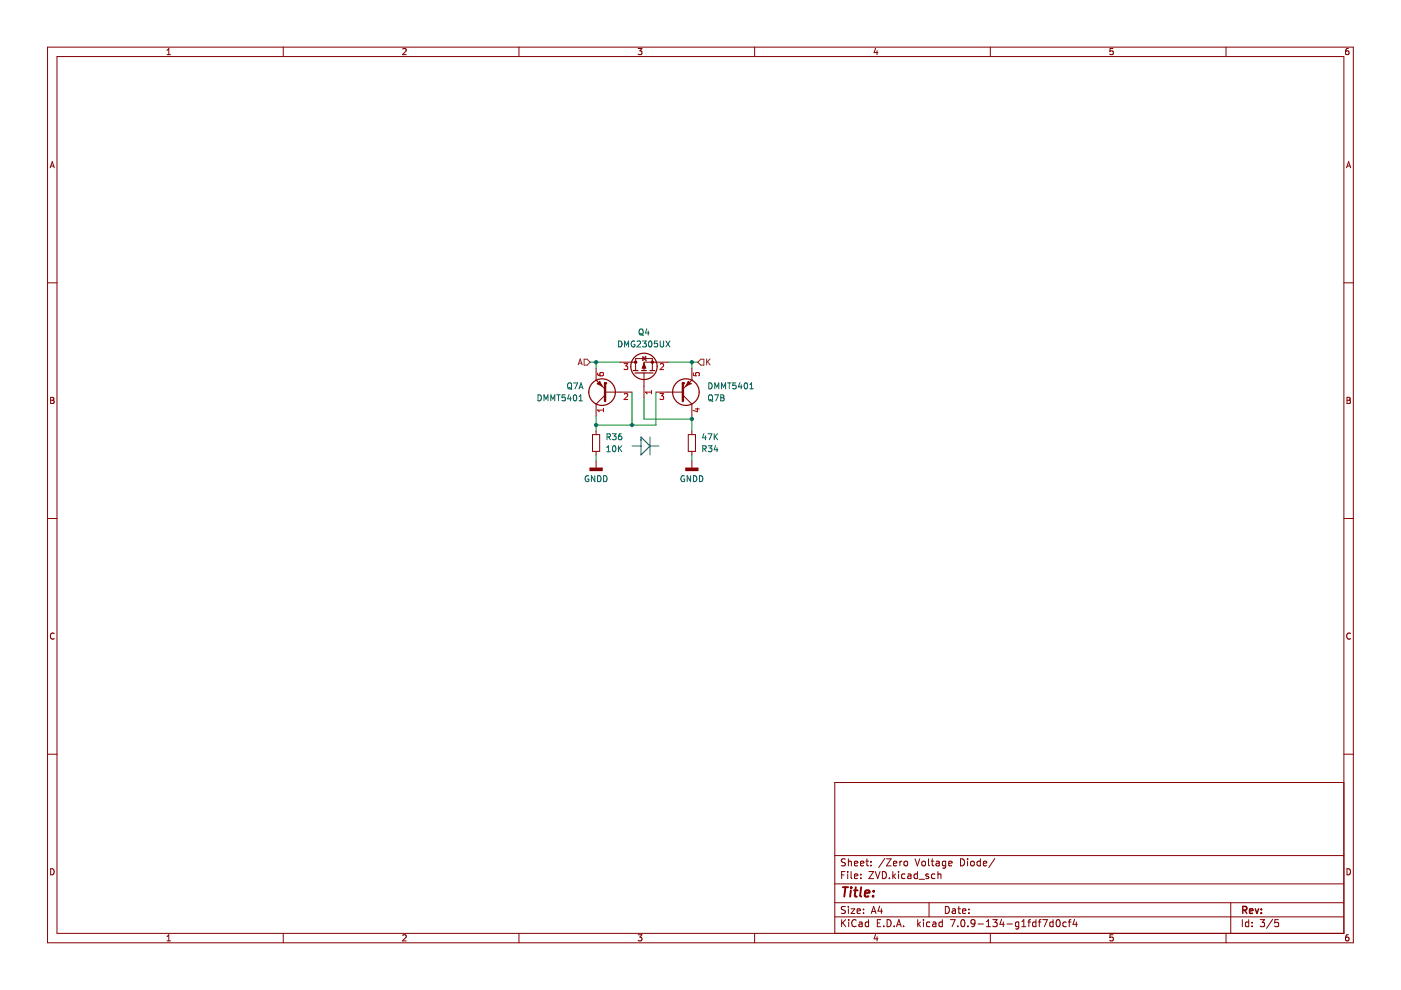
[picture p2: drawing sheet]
<svg xmlns="http://www.w3.org/2000/svg" width="297mm" height="210mm" viewBox="0 0 297 210" stroke-linecap="round" stroke-linejoin="round" font-family="sans-serif">
<g fill="none" stroke="#840000" stroke-width=".21">
<path d="M10.1 10h276.8v189.9h-276.8zM12.1 12h272.8v185.9h-272.8zM35.4 11.6h.8M35.4 10.7l.4-.4v1.3M60.1 10v2M85.4 10.4l.5-.1 .2 .4-.8 .9h.8M110 10v2M135.3 10.3h.8l-.4 .5 .3 .1v.6l-.1 .1-.6-.1M160 10v2M185.6 10.2l-.3 1h.8M185.9 10.7v.9M210 10v2"/>
<path d="M236 10.3h-.6l-.1 .6 .6-.1 .1 .7-.2 .1-.5-.1M259.9 10v2M285.9 10.3h-.4l-.2 .3v.7l.2 .3 .5-.1-.1-.7h-.4l-.2 .2M10.6 35.6l.5-1.3 .4 1.3M10.8 35.2h.6M285.5 35.6l.4-1.3 .5 1.3M285.6 35.2h.6M10.1 60h2M284.9 60h2M134 76.8h.8M134.8 78.6v-2.6h3.5v2.6M136.5 79.1v2.8"/>
<path d="M139.1 76.8h-2.6v1.8M10.7 84.2h.5l.2 .3-.2 .4 .2 .1 .1 .3-.3 .2h-.5zM10.7 84.9h.5M285.6 84.2h.4l.3 .3-.3 .4 .3 .1v.3l-.2 .2h-.5zM285.6 84.9h.4M10.1 109.9h2M284.9 109.9h2M11.5 134.3a.58 .58 0 0 0-.8 .6 .58 .58 0 0 0 .8 .5M286.3 134.3a.58 .58 0 0 0-.8 .6 .58 .58 0 0 0 .8 .5M10.1 159.9h2M284.9 159.9h2M284.9 165.9h-107.9v32"/>
<path d="M10.7 184.2a.66 .66 0 0 1 .8 .6 .66 .66 0 0 1-.8 .7zM35.4 198.6l.4-.4v1.3M35.4 199.5h.8M60.1 197.9v2M85.4 198.3l.5-.1 .2 .4-.8 .9h.8M110 197.9v2M135.3 198.2h.8l-.4 .5 .3 .1v.6l-.1 .1-.6-.1M160 197.9v2M177 194.4h107.9M177 191.4h107.9M177 187.4h107.9M177 181.4h107.9"/>
<path d="M178.4 195v1.5M178.4 185.5h.5M178.7 195.6l.6 .9M179.2 184.8h-.8v1.5M179.2 192.3l-.5-.1-.3 .1v.5l.7 .2 .1 .4-.3 .3-.5-.1M179.2 182.2l-.5-.1-.3 .1v.5l.7 .2 .1 .4-.3 .3-.5-.1M179.3 195l-.9 .8M179.7 184.8v.1M179.7 185.3v1M179.9 182.1v1.5M179.9 192.2v.1M179.9 192.7v1"/>
<path d="M179.9 182.7l.2-.1 .3 .1 .1 .9M179.9 195v.1M179.9 195.5v1M180.4 192.7h.8l-.8 1h.8M180.4 184.8v1.3l.3 .2M181.2 185.8l.7-.2-.1-.2-.4-.1-.2 .2v.7h.6M181.2 183.1l.7-.2-.1-.2-.4-.1-.2 .2v.7h.6M181.5 195.1a.71 .71 0 0 0-1 .5 .71 .71 0 0 0 .7 .9l.3-.2M181.7 193.2l.7-.2v-.2l-.5-.1-.2 .2 .1 .7h.6M182.2 195.6h.5l.1 .9M182.4 183.1l.8-.2-.1-.2-.4-.1-.3 .2 .1 .7h.6M182.5 186.1v.2"/>
<path d="M182.5 185.4v.1M182.8 195.8l-.5 .1-.2 .2 .2 .4 .5-.1M183.1 193.5v.2M183.1 192.8v.1M183.6 182.6h.6M183.8 182.1v1.3l.4 .2M184.2 195.6l-.5-.1-.3 .3 .2 .6h.6M184.2 195v1.5M184.2 184.8h1l-1 1.5h1M184.7 183.4v.2M184.7 182.7v.1M184.7 193.7l.5-1.5 .5 1.5"/>
<path d="M184.9 193.3h.7M185.6 184.8l.5 1.5 .5-1.5M185.6 198.1l-.3 1h.8M185.9 198.6v.9M186 195.7h.5M186.5 192.1l-.3 1.1h.9M186.7 195h-.7v1.5h.7M186.9 192.7v1M187.1 184.8a.76 .76 0 0 1 .8 .7 .76 .76 0 0 1-.8 .8zM187.4 196.3v.2M187.6 182l-1.3 1.9M187.9 182.1h1l-1 1.5h1"/>
<path d="M188.1 195a.76 .76 0 0 1 .8 .7 .76 .76 0 0 1-.8 .8zM188.6 186.1v.2M189.3 184.8v1.5M189.4 183.1l.8-.2-.1-.2-.4-.1-.3 .2 .1 .7h.6M189.4 185.7l.5 .6M189.6 196.3v.2M189.9 185.3l-.6 .6M190.1 196.5l.5-1.5 .5 1.5M190.2 196.1h.7M190.5 184.8v.1M190.5 185.3v1M190.8 182.6v1"/>
<path d="M191.2 182.6l-.4 .3M191.6 196.3v.2M191.7 182.7l.2-.1 .5 .1v.6l-.1 .2-.4 .1-.2-.2zM191.9 185.4l-.5-.1-.2 .3 .1 .6h.6M192.5 185.4h.6l.1 .9M193.2 185.6l-.5 .1-.3 .2 .3 .4 .5-.1M194 182.1l.5 1.5 .5-1.5M194.5 185.4l-.4-.1-.3 .3 .1 .6h.6M194.5 184.8v1.5M194.6 195v1.5M194.7 195.9l.5 .6M194.9 186.4h1.1"/>
<path d="M195.2 195.5l-.6 .6M195.5 182.7l.2-.1 .4 .1 .1 .6-.1 .2-.4 .1-.2-.2zM195.8 195v.1M195.8 195.5v1M196.9 182.1v1.3l.2 .2M196.9 185.4l-.4-.1-.2 .2 .1 .2 .5 .2v.3h-.6M197 191.4v3M197.1 195.6l-.4-.1-.3 .3 .2 .6h.5M197.4 182.6h.6M197.6 182.1v1.3l.4 .2M197.8 195.6h.6v.9M198.2 185.4l-.4-.1-.3 .3 .1 .6h.6"/>
<path d="M198.4 195.8l-.5 .1-.2 .2 .2 .4 .5-.1M198.5 182.7h.6v.9M198.9 185.4l.2-.1 .3 .1 .1 .9M198.9 184.8v1.5M199.1 182.9l-.5 .1-.2 .2 .2 .4 .5-.1M199.8 195.6l-.4-.1-.3 .3 .1 .6h.6M199.8 195v1.5M200.4 192.2a.76 .76 0 0 1 .9 .7 .76 .76 0 0 1-.9 .8zM200.5 182.7l-.4-.1-.3 .3 .1 .6h.6M200.5 182.6v1.2l-.3 .3-.3-.1M201.1 183.1l.8-.2-.1-.2-.4-.1-.3 .2 .1 .7h.6M201.5 195h1l-.6 1.5"/>
<path d="M201.9 192.8h.6l.1 .9M202.6 193l-.5 .1-.2 .2 .2 .4 .5-.1M203.1 192.7h.5M203.1 196.3v.2M203.3 192.2v1.3l.3 .2M203.6 182.1a.76 .76 0 0 1 .9 .7 .76 .76 0 0 1-.9 .8zM203.9 195.1l.2-.1a.8 .8 0 0 1 .5 .7 .8 .8 0 0 1-.5 .8l-.4-.6zM204.1 193.2l.7-.2-.1-.2-.4-.1-.2 .2v.7h.6M205.1 182.1v.1M205.1 182.6v1M205.2 196.3v.2M205.4 193.5v.2"/>
<path d="M205.4 192.8v.1M205.9 182.7l.2-.1 .4 .1 .1 .6-.2 .2-.3 .1-.2-.2zM206.7 195.6l-.3 .3h-.3l-.2-.3v-.3l.2-.3 .5 .1 .1 .2a1 1 0 0 1-.4 1.2h-.3M207.4 195.9h1.1M207.9 182.7l-.5-.1-.3 .3 .2 .6h.6M207.9 182.1v1.5M208.5 183.1l.7-.2-.1-.2-.4-.1-.2 .2 .1 .7h.5M209.1 196.5h.9M209.1 195.4l.5-.4v1.5M210 197.9v2M210.5 195h.9l-.5 .6 .5 .1v.6l-.3 .2-.6-.2M210.9 182l-1.3 1.9"/>
<path d="M212.4 194.9l-.4 1.1h.9M212.7 195.5v1M213.5 195.9h1.1M216 195.6l-.4-.1-.3 .3 .1 .6h.6M216 195.5v1.2l-.3 .3-.3-.1M216.6 196.5h.9M216.6 195.4l.5-.4v1.5M217.9 195.5h.6M218.5 195l-.4 .2v1.3M219.6 195.6l-.4-.1-.3 .3 .2 .6h.5M219.6 195v1.5M220.1 195.5h.6"/>
<path d="M220.7 195l-.3 .2v1.3M221.1 195h1l-.7 1.5M223.3 195.6l-.5-.1-.2 .3 .1 .6h.6M223.3 195v1.5M224.1 195.1l.2-.1a.8 .8 0 0 1 .5 .7 .8 .8 0 0 1-.5 .8l-.4-.6zM226.1 195.6l-.5-.1-.3 .3 .2 .6h.6M226.5 195.5h.6M227.1 195l-.4 .2v1.3M227.8 194.9l-.3 1.1h.9M228.2 195.5v1M236 198.2h-.6l-.1 .6 .6-.1 .1 .7-.2 .1-.5-.1M259.9 197.9v2"/>
<path d="M260.9 191.4v6.5M263.4 195v1.5M264.8 195.6l-.5-.1-.3 .3 .2 .6h.6M264.8 195v1.5M265.5 196.3v.2M265.5 195.6v.1M267.2 195h.9l-.5 .6 .4 .1v.6l-.2 .2-.6-.2M269.8 194.9l-1.3 1.9M271 195h-.7v.7l.2-.1h.5l.1 .2-.1 .5-.2 .2-.5-.2M285.6 184.2a.66 .66 0 0 1 .7 .6 .66 .66 0 0 1-.7 .7zM285.9 198.2l-.4 .1-.2 .2v.7l.2 .3 .5-.1-.1-.7h-.4l-.2 .2"/>
</g>
<path d="M263.5 193l.7-.1 .2-.2-.1-.4-.8-.1v1.5M263.9 193l.5 .7M264.9 193.2l.7-.2v-.3h-.5l-.2 .2 .1 .7h.6M266.1 192.7l.4 1 .4-1M267.4 193.5v.2M267.4 192.7v.2" fill="none" stroke="#840000" stroke-width=".3"/>
<path d="M178.7 188.1h1.1M179.3 188.1l-.3 2M180.4 188.8l-.2 1.3M180.5 188.1v.2M181.1 188.8h.7M181.4 188.1l-.2 1.7 .1 .2 .4 .1M182.6 188.1l-.2 1.7 .2 .3M183.4 189.4l.9-.2v-.3h-.8l-.2 .9 .3 .3 .6-.1M185.1 189.9v.2M185.2 188.9v.2" fill="none" stroke="#840000" stroke-width=".4"/>
<path d="M134 94.6h1.9M135.9 92.7l1.9 1.9-1.9 1.9zM137.8 94.6h1.9M137.8 92.7v3.8" fill="none" stroke="#0000c2" stroke-width=".21"/>
<path d="M125.1 76.8h6.4M126.4 76.8v1.3M141.6 76.8h6.4M146.7 76.8v1.3M126.4 88.2v3.2M126.4 96.5v1.2M134 83.1v7M136.5 84.4v4.4h10.2M139.1 83.1v7h-12.7M146.7 88.2v3.2M146.7 96.5v1.2" fill="none" stroke="#009600" stroke-width=".21"/>
<path d="M122.6 77.4l.4-1.3 .4 1.3M122.7 77h.6M123.8 76.2h.7l.6 .6-.6 .6h-.7zM148.6 76.2h.6v1.2h-.6l-.6-.6zM149.8 76.1v1.3M150 76.6l.5 .8M150.5 76.1l-.7 .7" fill="none" stroke="#725600" stroke-width=".21"/>
<path d="M134.3 78.6h1M134.6 79.1h3.8M136 78.6h1M137.8 78.6h1" fill="none" stroke="#840000" stroke-width=".25"/>
<path d="M136.5 77l.4 1.1h-.7z" fill="#840000"/>
<path d="M136.3 75.6l.6 .4-.6 .4zM136.5 77l.4 1.1h-.7zM136.8 75.5l.2 1" fill="none" stroke="#840000" stroke-width=".21"/>
<circle cx="136.5" cy="77.7" r="2.79" fill="none" stroke="#840000" stroke-width=".25"/>
<circle cx="138.3" cy="76.8" r=".25" fill="#840000"/>
<circle cx="138.3" cy="76.8" r=".25" fill="none" stroke="#840000" stroke-width=".21"/>
<circle cx="134.8" cy="76.8" r=".25" fill="#840000"/>
<g fill="none" stroke="#840000" stroke-width=".21">
<path d="M131.5 76.8h2.5M139.1 76.8h2.5M136.5 81.9v2.5M141.6 83.1h3.2M144.8 83.8l1.9 1.9M146.7 80.6h.1M146.7 80.6l-1.9 1.9"/>
<circle cx="134.8" cy="76.8" r=".25"/>
</g>
<path d="M132.3 77.1h.8l-.4 .5 .3 .1v.5l-.2 .2-.5-.2M140 77.2l.5-.1 .2 .4-.8 .9h.8M138.1 82.8v.7M138.1 83.1h-1.3l.4 .4" fill="none" stroke="#a90000" stroke-width=".21"/>
<g fill="none" stroke="#006464" stroke-width=".21">
<path d="M131.2 72.3a.64 .64 0 0 1 .7 .6 .64 .64 0 0 1-.7 .7zM132.4 73.6v-1.3l.4 .9 .5-.9v1.3M134.5 72.4a.58 .58 0 0 0-.7 .5 .58 .58 0 0 0 .8 .5v-.4h-.2M135.1 72.4l.5-.1 .2 .4-.8 .9h.8M135.6 69.9l.2-.1a.43 .43 0 0 1 .6 .4v.4a.42 .42 0 0 1-.5 .4 .42 .42 0 0 1-.4-.4zM135.8 70.7l.6 .4M136.2 72.3h.8l-.4 .5 .4 .1v.5l-.2 .2-.6-.2M137.1 69.7l-.3 .9h.8M137.4 70.2v.8M137.6 72.4l.2-.1a.68 .68 0 0 1 .4 .6 .68 .68 0 0 1-.4 .7l-.3-.5zM139.4 72.3h-.6l-.1 .6 .6-.1 .1 .6-.2 .2-.5-.2M140 72.3v1l.2 .3 .4-.1 .1-.2v-1"/>
<path d="M141.2 72.3l.8 1.3M142 72.3l-.8 1.3"/>
</g>
<path d="M144.8 81.2v3.8" fill="none" stroke="#840000" stroke-width=".51"/>
<circle cx="144.8" cy="81.2" r=".25" fill="#840000"/>
<path d="M145.9 80.9l.5 .5-1 .5z" fill-rule="evenodd" fill="#840000"/>
<path d="M146.7 78.1v2.5M125.6 92.1h1.5v3.6h-1.5zM126.4 91.4v.7M126.4 95.7v.8M139.1 83.1h2.5M145.9 80.9l.5 .5-1 .5zM146.4 81.4h.1M146.7 85.7v2.5" fill="none" stroke="#840000" stroke-width=".21"/>
<circle cx="145.4" cy="83.1" r="2.82" fill="none" stroke="#840000" stroke-width=".25"/>
<path d="M147 79v.6l.6 .1-.1-.6 .6-.1 .2 .2-.2 .5M139.9 83.4h.8l-.4 .5 .3 .1v.6l-.1 .1-.6-.1M147.4 86.7h.9M147.8 86.5v.8l-.9-.3" fill="none" stroke="#a90000" stroke-width=".21"/>
<g fill="none" stroke="#006464" stroke-width=".21">
<path d="M128.6 95.8h.8M128.6 94.9l.4-.4v1.3M128.7 92.6h.6l.1-.5-.7-.1v1.2M129 92.6l.4 .6M129.8 92h.8l-.4 .5 .4 .1v.5l-.2 .1-.6-.1M130 94.6l.1-.1a.68 .68 0 0 1 .5 .6 .68 .68 0 0 1-.5 .7l-.3-.5zM131.1 94.5v1.3M131.3 95.1l.5 .7M131.7 92h-.3l-.2 .3-.1 .7 .3 .2 .4-.1-.1-.6h-.3l-.3 .2M131.8 94.5l-.7 .7M150.3 83.9l.2-.2a.43 .43 0 0 1 .6 .4v.5a.42 .42 0 0 1-.5 .4 .42 .42 0 0 1-.4-.4zM150.3 81.2a.64 .64 0 0 1 .7 .6 .64 .64 0 0 1-.7 .6z"/>
<path d="M150.5 84.7l.6 .4M151.5 83.7h.8l-.5 1.3M151.5 82.4v-1.2l.5 .9 .4-.9v1.2M152.8 83.7h.4l.3 .3-.3 .3 .3 .1v.3l-.2 .3h-.5zM152.8 84.3h.4M153 82.4v-1.2l.4 .9 .4-.9v1.2M154.3 81.2h.7M154.6 81.2v1.2M156 81.2h-.6v.6l.6-.1v.6l-.2 .1-.4-.1M156.9 81.1l-.3 .9h.7M157.2 81.6v.8M158 81.2h.1a.68 .68 0 0 1 .4 .6 .68 .68 0 0 1-.4 .6 .84 .84 0 0 1-.1-1.2z"/>
<path d="M159 82.4h.7M159 81.5l.3-.3v1.2"/>
</g>
<path d="M125.1 99.3h2.6v.5h-2.6z" fill-rule="evenodd" fill="#840000"/>
<path d="M125.1 99.3h2.6v.5h-2.6z" fill="none" stroke="#840000" stroke-width=".25"/>
<path d="M126.4 80.6h.1M126.4 97.7v1.6M126.4 80.6l1.9 1.9M128.3 83.1h3.2M128.3 83.8l-1.9 1.9" fill="none" stroke="#840000" stroke-width=".21"/>
<path d="M124.8 100.9a.58 .58 0 0 0-.8 .6 .58 .58 0 0 0 .8 .5v-.4h-.2M126.1 100.9v1.2l-.7-1.2v1.2M126.7 100.9a.64 .64 0 0 1 .7 .6 .64 .64 0 0 1-.7 .6zM128 100.9a.64 .64 0 0 1 .7 .6 .64 .64 0 0 1-.7 .6z" fill="none" stroke="#006464" stroke-width=".21"/>
<path d="M128.3 81.2v3.8" fill="none" stroke="#840000" stroke-width=".51"/>
<circle cx="128.3" cy="81.2" r=".25" fill="#840000"/>
<path d="M127.1 80.9l.6 1-1.1-.5z" fill-rule="evenodd" fill="#840000"/>
<path d="M126.4 78.1v2.5M126.4 85.7v2.5M126.6 81.4h.1M127.1 80.9l.6 1-1.1-.5zM131.5 83.1h2.5M145.9 92.1h1.6v3.6h-1.6zM146.7 91.4v.7M146.7 95.7v.8" fill="none" stroke="#840000" stroke-width=".21"/>
<circle cx="127.7" cy="83.1" r="2.82" fill="none" stroke="#840000" stroke-width=".25"/>
<path d="M126.7 79.1v.4l.3 .1 .7 .1 .3-.2-.2-.5-.6 .1v.4l.2 .2M128 86.6v.7M128 86.9h-1.3l.4 .4M132.4 83.6l.4-.2 .3 .4-.8 .9h.8" fill="none" stroke="#a90000" stroke-width=".21"/>
<g fill="none" stroke="#006464" stroke-width=".21">
<path d="M114.1 83.7a.64 .64 0 0 1 .7 .7 .64 .64 0 0 1-.7 .6zM115.3 85v-1.3l.5 .9 .4-.9v1.3M116.8 85v-1.3l.4 .9 .4-.9v1.3M118.1 83.7h.7M118.4 83.7v1.3M119.8 83.7h-.6l-.1 .6h.6l.1 .6-.2 .1-.5-.1M120.4 81.4l.2-.2a.43 .43 0 0 1 .6 .4v.4a.42 .42 0 0 1-.4 .5 .42 .42 0 0 1-.5-.5zM120.6 82.1l.7 .5M120.6 83.7l-.3 .9h.8M121 84.1v.9M121.6 81.2h.9l-.6 1.2M121.7 83.8l.2-.1a.68 .68 0 0 1 .4 .7 .68 .68 0 0 1-.4 .6l-.3-.5z"/>
<path d="M122.8 82.4l.4-1.2 .4 1.2M122.8 85h.7M122.8 84.1l.3-.4v1.3M122.9 82.1h.6M149 95.2l.6-.1 .1-.5-.7-.1v1.3M149.2 91.9l-.3 .9h.8M149.3 95.2l.4 .6M149.6 92.4v.8M150.1 92h.8l-.5 1.2M150.2 94.5h.7l-.4 .5 .4 .1v.6l-.2 .1-.5-.1M151.4 92v1.2M151.6 92.5l.6 .7"/>
<path d="M151.7 94.4l-.3 1h.8M152 94.9v.9M152.2 92l-.8 .7"/>
</g>
<path d="M145.4 99.3h2.6v.5h-2.6z" fill-rule="evenodd" fill="#840000"/>
<path d="M145.4 99.3h2.6v.5h-2.6z" fill="none" stroke="#840000" stroke-width=".25"/>
<path d="M146.7 97.7v1.6" fill="none" stroke="#840000" stroke-width=".21"/>
<path d="M145.1 100.9a.58 .58 0 0 0-.7 .6 .58 .58 0 0 0 .7 .5v-.4h-.2M146.4 100.9v1.2l-.7-1.2v1.2M147 100.9a.64 .64 0 0 1 .8 .6 .64 .64 0 0 1-.8 .6zM148.3 100.9a.64 .64 0 0 1 .7 .6 .64 .64 0 0 1-.7 .6z" fill="none" stroke="#006464" stroke-width=".21"/>
<g fill="#009600">
<circle cx="126.4" cy="90.1" r=".46"/>
<circle cx="134" cy="90.1" r=".46"/>
<circle cx="146.7" cy="88.8" r=".46"/>
<circle cx="146.7" cy="76.8" r=".46"/>
<circle cx="126.4" cy="76.8" r=".46"/>
</g>
</svg>
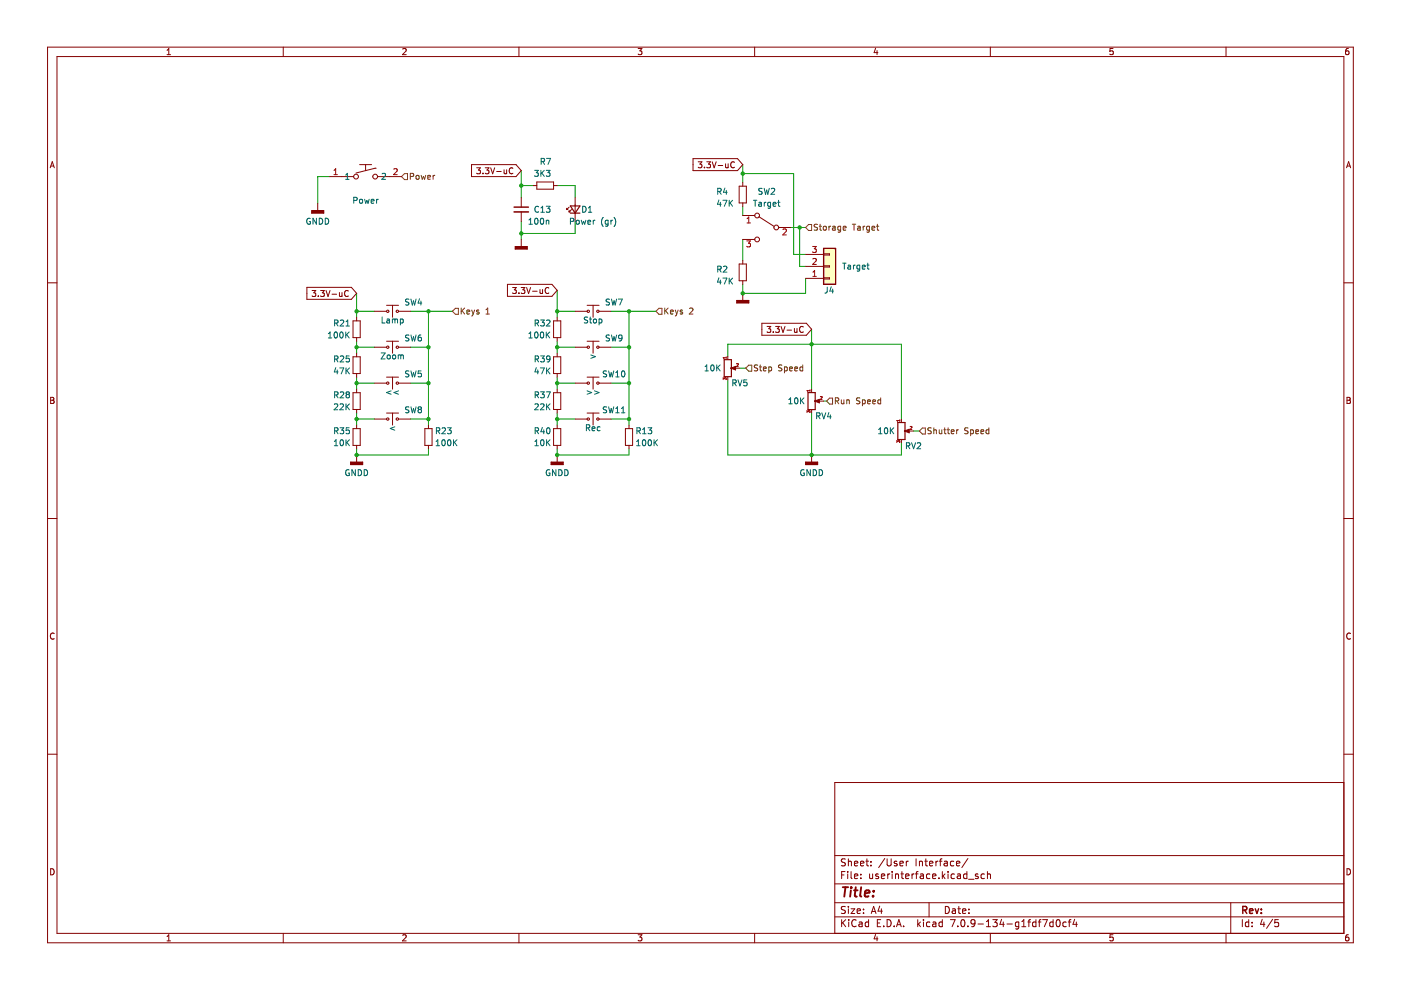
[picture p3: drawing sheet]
<svg xmlns="http://www.w3.org/2000/svg" width="297mm" height="210mm" viewBox="0 0 297 210" stroke-linecap="round" stroke-linejoin="round" font-family="sans-serif">
<g fill="none" stroke="#840000" stroke-width=".21">
<path d="M10.1 10h276.8v189.9h-276.8zM12.1 12h272.8v185.9h-272.8zM35.4 11.6h.8M35.4 10.7l.4-.4v1.3M60.1 10v2M85.4 10.4l.5-.1 .2 .4-.8 .9h.8M110 10v2M135.3 10.3h.8l-.4 .5 .3 .1v.6l-.1 .1-.6-.1M160 10v2M185.6 10.2l-.3 1h.8M185.9 10.7v.9M210 10v2"/>
<path d="M236 10.3h-.6l-.1 .6 .6-.1 .1 .7-.2 .1-.5-.1M259.9 10v2M285.9 10.3h-.4l-.2 .3v.7l.2 .3 .5-.1-.1-.7h-.4l-.2 .2M10.6 35.6l.5-1.3 .4 1.3M10.8 35.2h.6M285.5 35.6l.4-1.3 .5 1.3M285.6 35.2h.6M10.1 60h2M284.9 60h2M10.7 84.2h.5l.2 .3-.2 .4 .2 .1 .1 .3-.3 .2h-.5zM10.7 84.9h.5M285.6 84.2h.4l.3 .3-.3 .4 .3 .1v.3l-.2 .2h-.5z"/>
<path d="M285.6 84.9h.4M10.1 109.9h2M284.9 109.9h2M11.5 134.3a.58 .58 0 0 0-.8 .6 .58 .58 0 0 0 .8 .5M286.3 134.3a.58 .58 0 0 0-.8 .6 .58 .58 0 0 0 .8 .5M10.1 159.9h2M284.9 159.9h2M284.9 165.9h-107.9v32M10.7 184.2a.66 .66 0 0 1 .8 .6 .66 .66 0 0 1-.8 .7zM35.4 198.6l.4-.4v1.3M35.4 199.5h.8M60.1 197.9v2"/>
<path d="M85.4 198.3l.5-.1 .2 .4-.8 .9h.8M110 197.9v2M135.3 198.2h.8l-.4 .5 .3 .1v.6l-.1 .1-.6-.1M160 197.9v2M177 194.4h107.9M177 191.4h107.9M177 187.4h107.9M177 181.4h107.9M178.4 195v1.5M178.4 185.5h.5M178.7 195.6l.6 .9M179.2 184.8h-.8v1.5"/>
<path d="M179.2 192.3l-.5-.1-.3 .1v.5l.7 .2 .1 .4-.3 .3-.5-.1M179.2 182.2l-.5-.1-.3 .1v.5l.7 .2 .1 .4-.3 .3-.5-.1M179.3 195l-.9 .8M179.7 184.8v.1M179.7 185.3v1M179.9 182.1v1.5M179.9 192.2v.1M179.9 192.7v1M179.9 182.7l.2-.1 .3 .1 .1 .9M179.9 195v.1M179.9 195.5v1M180.4 192.7h.8l-.8 1h.8"/>
<path d="M180.4 184.8v1.3l.3 .2M181.2 185.8l.7-.2-.1-.2-.4-.1-.2 .2v.7h.6M181.2 183.1l.7-.2-.1-.2-.4-.1-.2 .2v.7h.6M181.5 195.1a.71 .71 0 0 0-1 .5 .71 .71 0 0 0 .7 .9l.3-.2M181.7 193.2l.7-.2v-.2l-.5-.1-.2 .2 .1 .7h.6M182.2 195.6h.5l.1 .9M182.4 183.1l.8-.2-.1-.2-.4-.1-.3 .2 .1 .7h.6M182.5 186.1v.2M182.5 185.4v.1M182.8 195.8l-.5 .1-.2 .2 .2 .4 .5-.1M183.1 193.5v.2M183.1 192.8v.1"/>
<path d="M183.6 182.6h.6M183.8 182.1v1.3l.4 .2M184.2 195.6l-.5-.1-.3 .3 .2 .6h.6M184.2 195v1.5M184.4 185.3v.9l.4 .1 .2-.2M184.7 183.4v.2M184.7 182.7v.1M184.7 193.7l.5-1.5 .5 1.5M184.9 193.3h.7M185 185.3v1M185.6 198.1l-.3 1h.8M185.9 198.6v.9"/>
<path d="M186 195.7h.5M186.2 185.4l-.3-.1-.2 .2v.2l.5 .2v.3h-.5M186.5 192.1l-.3 1.1h.9M186.7 195h-.7v1.5h.7M186.9 185.8l.7-.2-.1-.2-.4-.1-.2 .2v.7h.6M186.9 192.7v1M187.4 196.3v.2M187.6 182l-1.3 1.9M188.1 195a.76 .76 0 0 1 .8 .7 .76 .76 0 0 1-.8 .8zM188.1 182.1v1.2l.3 .3 .4-.1 .1-.2v-1.2M188.2 185.3v1M188.7 185.3l-.5 .3"/>
<path d="M189.2 184.8v.1M189.2 185.3v1M189.6 196.3v.2M189.9 185.4l.2-.1 .3 .1 .1 .9M189.9 185.3v1M190.1 196.5l.5-1.5 .5 1.5M190.2 182.7l-.4-.1-.2 .2 .1 .2 .5 .2v.3h-.6M190.2 196.1h.7M190.8 183.1l.7-.2-.1-.2-.4-.1-.2 .2 .1 .7h.5M191 185.3h.6M191.2 184.8v1.3l.4 .2M191.6 196.3v.2"/>
<path d="M192 185.8l.7-.2v-.2l-.5-.1-.2 .2 .1 .7h.6M192.2 182.6v1M192.6 182.6l-.4 .3M193.4 185.3v1M193.8 185.3l-.4 .3M194.1 185.3h.6M194.2 182.1v1.5M194.6 195v1.5M194.7 184.8l-.4 .2v1.3M194.7 195.9l.5 .6M194.9 182.7l.3-.1 .3 .1 .1 .9M194.9 182.6v1"/>
<path d="M195.2 185.4h.5l.1 .9M195.2 195.5l-.6 .6M195.8 185.6l-.5 .1-.2 .2 .2 .4 .5-.1M195.8 195v.1M195.8 195.5v1M196.1 182.6h.5M196.3 182.1v1.3l.3 .2M197 191.4v3M197.1 183.1l.7-.2-.1-.2-.4-.1-.2 .2v.7h.6M197.1 185.4l-.4-.1-.3 .3 .2 .6h.5M197.1 195.6l-.4-.1-.3 .3 .2 .6h.5M197.7 185.8l.7-.2v-.2l-.5-.1-.2 .2 .1 .7h.6"/>
<path d="M197.8 195.6h.6v.9M198.4 182.6v1M198.4 195.8l-.5 .1-.2 .2 .2 .4 .5-.1M198.9 182.6l-.5 .3M199.1 186.1v.2M199.1 182.6h.6M199.7 182.1l-.3 .2v1.3M199.8 184.8v1.5M199.8 195.6l-.4-.1-.3 .3 .1 .6h.6M199.8 195v1.5M199.9 185.7l.5 .6M200.2 182.7h.6l.1 .9"/>
<path d="M200.4 185.3l-.6 .6M200.4 192.2a.76 .76 0 0 1 .9 .7 .76 .76 0 0 1-.9 .8zM200.9 182.9l-.5 .1-.3 .2 .3 .4 .5-.1M201 184.8v.1M201 185.3v1M201.5 195h1l-.6 1.5M201.9 192.8h.6l.1 .9M202.2 182.7l-.4-.1-.3 .3 .1 .6h.6M202.4 185.4l-.5-.1-.3 .3 .2 .6h.6M202.6 193l-.5 .1-.2 .2 .2 .4 .5-.1M202.8 183.1l.7-.2-.1-.2-.4-.1-.2 .2 .1 .7h.5M203 185.4h.6v.9"/>
<path d="M203.1 192.7h.5M203.1 196.3v.2M203.3 192.2v1.3l.3 .2M203.6 185.6l-.5 .1-.2 .2 .2 .4 .5-.1M203.9 195.1l.2-.1a.8 .8 0 0 1 .5 .7 .8 .8 0 0 1-.5 .8l-.4-.6zM204.1 193.2l.7-.2-.1-.2-.4-.1-.2 .2v.7h.6M205 185.4l-.4-.1-.3 .3 .1 .6h.6M205 184.8v1.5M205.2 182l-1.3 1.9M205.2 196.3v.2M205.4 186.4h1.1M205.4 193.5v.2"/>
<path d="M205.4 192.8v.1M206.7 195.6l-.3 .3h-.3l-.2-.3v-.3l.2-.3 .5 .1 .1 .2a1 1 0 0 1-.4 1.2h-.3M207.4 185.4l-.4-.1-.2 .2 .1 .2 .5 .2v.3h-.6M207.4 195.9h1.1M208.7 185.4l-.4-.1-.3 .3 .1 .6h.6M209.1 196.5h.9M209.1 195.4l.5-.4v1.5M209.4 185.4l.2-.1 .3 .1 .1 .9M209.4 184.8v1.5M210 197.9v2M210.5 195h.9l-.5 .6 .5 .1v.6l-.3 .2-.6-.2M212.4 194.9l-.4 1.1h.9"/>
<path d="M212.7 195.5v1M213.5 195.9h1.1M216 195.6l-.4-.1-.3 .3 .1 .6h.6M216 195.5v1.2l-.3 .3-.3-.1M216.6 196.5h.9M216.6 195.4l.5-.4v1.5M217.9 195.5h.6M218.5 195l-.4 .2v1.3M219.6 195.6l-.4-.1-.3 .3 .2 .6h.5M219.6 195v1.5M220.1 195.5h.6M220.7 195l-.3 .2v1.3"/>
<path d="M221.1 195h1l-.7 1.5M223.3 195.6l-.5-.1-.2 .3 .1 .6h.6M223.3 195v1.5M224.1 195.1l.2-.1a.8 .8 0 0 1 .5 .7 .8 .8 0 0 1-.5 .8l-.4-.6zM226.1 195.6l-.5-.1-.3 .3 .2 .6h.6M226.5 195.5h.6M227.1 195l-.4 .2v1.3M227.8 194.9l-.3 1.1h.9M228.2 195.5v1M236 198.2h-.6l-.1 .6 .6-.1 .1 .7-.2 .1-.5-.1M259.9 197.9v2M260.9 191.4v6.5"/>
<path d="M263.4 195v1.5M264.8 195.6l-.5-.1-.3 .3 .2 .6h.6M264.8 195v1.5M265.5 196.3v.2M265.5 195.6v.1M267.6 194.9l-.3 1.1h.9M268 195.5v1M269.8 194.9l-1.3 1.9M271 195h-.7v.7l.2-.1h.5l.1 .2-.1 .5-.2 .2-.5-.2M285.6 184.2a.66 .66 0 0 1 .7 .6 .66 .66 0 0 1-.7 .7zM285.9 198.2l-.4 .1-.2 .2v.7l.2 .3 .5-.1-.1-.7h-.4l-.2 .2"/>
</g>
<path d="M263.5 193l.7-.1 .2-.2-.1-.4-.8-.1v1.5M263.9 193l.5 .7M264.9 193.2l.7-.2v-.3h-.5l-.2 .2 .1 .7h.6M266.1 192.7l.4 1 .4-1M267.4 193.5v.2M267.4 192.7v.2" fill="none" stroke="#840000" stroke-width=".3"/>
<path d="M178.7 188.1h1.1M179.3 188.1l-.3 2M180.4 188.8l-.2 1.3M180.5 188.1v.2M181.1 188.8h.7M181.4 188.1l-.2 1.7 .1 .2 .4 .1M182.6 188.1l-.2 1.7 .2 .3M183.4 189.4l.9-.2v-.3h-.8l-.2 .9 .3 .3 .6-.1M185.1 189.9v.2M185.2 188.9v.2" fill="none" stroke="#840000" stroke-width=".4"/>
<path d="M174.6 52.7h2.6v7.6h-2.6z" fill-rule="evenodd" fill="#ffffc2"/>
<path d="M174.6 52.7h2.6v7.6h-2.6z" fill="none" stroke="#840000" stroke-width=".25"/>
<g fill="none" stroke="#009600" stroke-width=".21">
<path d="M69.9 37.4h-2.5v5.8M110.5 36.2v5.7M110.5 39.3h2.6M118.1 39.3h3.8v2.6M157.5 34.9v3.8M157.5 36.8h10.8v17.1h2.5M110.5 47v3.8M121.9 47v2.5h-11.4M157.5 43.8v1.9M157.5 50.8v4.4M167.6 48.2h3.2M169.5 48.2v8.3h1.3"/>
<path d="M170.8 59v3.2h-13.3v-1.9M75.6 62.2v5.1M75.6 72.3v2.6M75.6 80v2.5M75.6 66h3.8M75.6 73.6h3.8M87 66h8.9M87 73.6h3.8M90.8 66v24.1M118.1 66h3.8M118.1 73.6h3.8M118.1 61.6v5.7"/>
<path d="M118.1 72.3v2.6M118.1 80v2.5M129.6 66h9.5M129.6 73.6h3.8M133.4 66v24.1M154.3 75.5v-2.5h36.8v15.8M156.8 78.1h1.3M172.1 69.8v12.7M75.6 87.6v2.5M75.6 95.2v1.3h15.2v-1.3M75.6 81.2h3.8M75.6 88.8h3.8"/>
<path d="M87 81.2h3.8M87 88.8h3.8M118.1 81.2h3.8M118.1 95.2v1.3h15.3v-1.3M118.1 88.8h3.8M118.1 87.6v2.5M129.6 81.2h3.8M129.6 88.8h3.8M154.3 80.6v15.9h36.8v-2.6M172.1 87.6v8.9M174.6 85h.6M193.7 91.4h1.2"/>
</g>
<g fill="none" stroke="#840000" stroke-width=".21">
<path d="M69.9 37.4h5.1M76.2 34.9h2.6M77.5 34.9v1.3M79.5 35.7h.1M79.5 35.7l-4 1M80.1 37.4h5M100 34.9h9.4l1.1 1.3-1.1 1.2h-9.4zM101.1 35.6h.8l-.5 .5 .4 .1v.5l-.2 .1-.5-.1M102.4 36.7v.1M102.9 35.6h.8l-.5 .5 .4 .1v.5l-.2 .1-.5-.1M104 35.6l.5 1.2 .4-1.2M105.3 36.4h1"/>
<path d="M106.9 36v.8l.5-.1M107.4 36v.8M108.7 35.7a.56 .56 0 0 0-.7 .5 .56 .56 0 0 0 .7 .5M146.9 33.6h9.5l1.1 1.3-1.1 1.3h-9.5zM148 34.3h.8l-.4 .5 .4 .1v.6l-.2 .1-.6-.1M149.4 35.5v.1M149.8 34.3h.8l-.4 .5 .4 .1v.6l-.2 .1-.6-.1M151 34.3l.4 1.3 .4-1.3M152.3 35.1h.9M153.8 34.7l.1 .8h.5M154.4 34.7v.9M155.7 34.4a.56 .56 0 0 0-.8 .5 .56 .56 0 0 0 .8 .6"/>
<path d="M65.1 60.9h9.4l1.1 1.3-1.1 1.3h-9.4zM66.2 61.6h.8l-.5 .5 .4 .1v.5l-.2 .2-.5-.2M67.5 62.7v.2M68 61.6h.8l-.5 .5 .4 .1v.5l-.2 .2-.5-.2M69.1 61.6l.4 1.3 .5-1.3M70.4 62.4h1M72 62v.8l.5-.1M72.5 62v.9M73.8 61.7a.56 .56 0 0 0-.8 .5 .56 .56 0 0 0 .8 .5M107.6 60.3h9.4l1.1 1.3-1.1 1.2h-9.4zM108.7 61h.8l-.5 .4 .4 .2v.5l-.2 .1-.5-.1M110 62.1v.1"/>
<path d="M110.5 61h.8l-.4 .4 .3 .2v.5l-.2 .1-.5-.1M111.6 61l.5 1.2 .4-1.2M112.9 61.7h1M114.5 61.4v.8l.5-.1M115 61.4v.8M116.4 61.1a.56 .56 0 0 0-.8 .5 .56 .56 0 0 0 .8 .5M161.5 68.5h9.5l1.1 1.3-1.1 1.3h-9.5zM162.6 69.2h.8l-.4 .5 .4 .1v.6l-.2 .1-.6-.1M164 70.4v.1M164.4 69.2h.8l-.4 .5 .4 .1v.6l-.2 .1-.6-.1M165.6 69.2l.4 1.3 .4-1.3M166.9 70h.9"/>
<path d="M168.4 69.6l.1 .8h.5M169 69.6v.9M170.3 69.3a.56 .56 0 0 0-.8 .5 .56 .56 0 0 0 .8 .6"/>
<circle cx="75.5" cy="37.4" r=".51"/>
<circle cx="79.5" cy="37.4" r=".51"/>
</g>
<g fill="none" stroke="#725600" stroke-width=".21">
<path d="M85.8 36.8h.6v1.3h-.6l-.7-.7zM87 37.4h.6l.1-.5-.7-.1v1.2M88.3 37.3l.1-.1 .4 .1-.1 .7-.4-.1zM89.3 37.2l.2 .8 .3-.6 .2 .6 .3-.8M90.7 37.6l.6-.1-.1-.3h-.3l-.2 .2v.6h.5M91.8 37.2v.8M92.2 37.2l-.4 .2M171.4 47.6h.7v1.3h-.7l-.6-.7zM173.3 47.6l-.6 .1v.3l.5 .3 .1 .3-.2 .2h-.5M173.7 48h.5M173.9 47.5v1.1l.3 .2M174.6 48.1l.2-.1 .3 .1v.7l-.5-.1z"/>
<path d="M175.8 48v.8M176.1 48l-.3 .2M176.5 48h.5l.1 .8M177.1 48.3l-.6 .2 .2 .3h.4M178.2 48h-.3l-.3 .2 .1 .6h.5M178.2 48v1l-.2 .2h-.3M178.8 48.4l.6-.1-.1-.3h-.3l-.2 .1v.7h.5M180.7 47.5h.7M181.1 47.5v1.3M181.9 48h.4l.1 .8M182.4 48.3l-.6 .2 .2 .3h.4M183 48v.8"/>
<path d="M183.4 48l-.4 .2M184.3 48h-.3l-.3 .2 .2 .6h.4M184.3 48v1l-.2 .2h-.3M184.9 48.4l.6-.1-.1-.3h-.3l-.2 .1v.7h.5M185.8 48h.5M186 47.5v1.1l.3 .2M96.6 65.4h.6v1.2h-.6l-.7-.6zM97.8 65.3v1.3M98 65.9l.5 .7M98.5 65.3l-.7 .7M99 66.2l.6-.2-.1-.2-.3-.1-.2 .2 .1 .6h.4M100 65.7l.3 .9"/>
<path d="M100.3 66.6l-.3 .4M100.6 65.7l-.3 .9M101.5 65.8l-.3-.1-.2 .2 .1 .2 .4 .1v.3h-.5M103 66.6h.8M103 65.7l.4-.4v1.3M139.7 65.4h.6v1.2h-.6l-.6-.6zM140.9 65.3v1.3M141.1 65.9l.6 .7M141.7 65.3l-.8 .7M142.1 66.2l.6-.2v-.2l-.4-.1-.2 .2 .1 .6h.5M143.2 65.7l.3 .9M143.5 66.6l-.3 .4"/>
<path d="M143.8 65.7l-.3 .9M144.7 65.8l-.3-.1-.2 .2 .1 .2 .4 .1v.3h-.5M146.2 65.4l.5-.1 .2 .4-.8 .9h.8M158.7 77.4h.7v1.3h-.7l-.6-.6zM160.6 77.4l-.6 .1v.4l.5 .2 .1 .3-.2 .2h-.5M161 77.8h.5M161.2 77.4v1.1l.3 .1M161.8 78.2l.7-.1-.1-.2-.4-.1-.2 .2 .1 .6h.5M163 77.9l.4-.1 .2 .2-.1 .6h-.5M163 77.8v1.3M165.8 77.4l-.7 .1v.4l.6 .2 .1 .3-.3 .2h-.4M166.3 77.9l.4-.1 .2 .2-.1 .6h-.5"/>
<path d="M166.3 77.8v1.3M167.4 78.2l.6-.1v-.2l-.4-.1-.2 .2 .1 .6h.5M168.5 78.2l.6-.1-.1-.2-.3-.1-.2 .2 .1 .6h.4M170.2 77.9l-.4-.1-.2 .2 .1 .6h.5M170.2 77.4v1.2M175.9 84.4h.6v1.3h-.6l-.7-.7zM177.1 85h.6l.1-.5-.7-.1v1.2M177.4 85l.4 .6M178.4 84.8v.8l.5-.1M178.9 84.8v.8M179.5 84.9l.5-.1 .1 .8M179.5 84.8v.8"/>
<path d="M182.3 84.4l-.7 .1v.3l.6 .3 .1 .3-.2 .2h-.5M182.9 84.8h.3l.3 .2-.2 .6h-.4M182.9 84.8v1.2M183.9 85.2l.6-.1v-.3h-.4l-.2 .2 .1 .6h.5M185 85.2l.6-.1v-.3h-.4l-.2 .2 .1 .6h.5M186.7 84.8h-.3l-.3 .2 .1 .6h.5M186.7 84.4v1.2M195.6 90.8h.6v1.2h-.6l-.7-.6zM197.4 90.8h-.6v.4l.5 .2 .1 .3-.2 .3-.5-.1M198 91.2h.5v.8M198 90.7v1.3M199.1 91.1l.1 .8 .5-.1"/>
<path d="M199.7 91.1v.9M200.1 91.1h.5M200.3 90.7v1.1l.3 .2M200.8 91.1h.5M201 90.7v1.1l.3 .2M201.7 91.5l.6-.1-.1-.2-.3-.1-.2 .2v.6h.5M202.8 91.1v.9M203.2 91.1l-.4 .3M205.2 90.8h-.6v.4l.5 .2 .1 .3-.2 .3-.5-.1M205.8 91.2l.4-.1 .2 .3-.1 .5h-.5M205.8 91.1v1.3M206.9 91.5l.6-.1-.1-.2-.3-.1-.2 .2v.6h.5"/>
<path d="M208 91.5l.6-.1-.1-.2-.4-.1-.1 .2v.6h.5M209.7 91.2l-.4-.1-.2 .3 .1 .5h.5M209.7 90.7v1.3"/>
</g>
<path d="M73.3 38h.7M73.3 37.1l.3-.3v1.2M81 36.9l.5-.1 .2 .3-.7 .9h.7M75 42.5l.6-.1 .1-.4-.7-.2v1.3M76.3 42.4l.2-.1 .3 .1v.6h-.5zM77.3 42.3l.2 .8 .3-.6 .2 .6 .3-.8M78.7 42.7l.6-.1-.1-.3h-.3l-.2 .1 .1 .6h.4M79.8 42.3v.8M80.2 42.3l-.4 .2" fill="none" stroke="#006464" stroke-width=".21"/>
<path d="M70.8 37h.7M70.8 36.1l.4-.3v1.2M83.5 35.9l.5-.1 .2 .3-.8 .9h.8" fill="none" stroke="#a90000" stroke-width=".21"/>
<path d="M66.1 44.7h2.5v.5h-2.5z" fill-rule="evenodd" fill="#840000"/>
<path d="M66.1 44.7h2.5v.5h-2.5z" fill="none" stroke="#840000" stroke-width=".25"/>
<g fill="none" stroke="#840000" stroke-width=".21">
<path d="M113.1 39.3h.7M113.8 38.6h3.6v1.5h-3.6zM117.4 39.3h.7M67.4 43.2v1.5M74.8 68h1.6v3.6h-1.6zM74.8 75.6h1.6v3.6h-1.6zM75.6 67.3v.7M75.6 71.6v.7M75.6 74.9v.7M75.6 79.2v.8M79.4 66h2.6M79.4 73.6h2.6"/>
<path d="M82 80h2.5M82 64.7h2.5M82 72.3h2.5M83.2 64.7v2.6M83.2 72.3v2.6M83.2 80v2.5M84.5 66h2.5M84.5 73.6h2.5M79.4 81.2h2.6M79.4 88.8h2.6M82 87.6h2.5M83.2 87.6v2.5"/>
<path d="M84.5 81.2h2.5M84.5 88.8h2.5M90.1 90.9h1.5v3.5h-1.5zM90.8 90.1v.8M90.8 94.4v.8M121.9 88.8h2.6M124.5 87.6h2.5M125.7 87.6v2.5M127 88.8h2.6"/>
<circle cx="82.2" cy="73.6" r=".25"/>
<circle cx="82.2" cy="66" r=".25"/>
<circle cx="84.2" cy="73.6" r=".25"/>
<circle cx="84.2" cy="66" r=".25"/>
<circle cx="82.2" cy="81.2" r=".25"/>
<circle cx="82.2" cy="88.8" r=".25"/>
<circle cx="84.2" cy="81.2" r=".25"/>
<circle cx="84.2" cy="88.8" r=".25"/>
<circle cx="124.7" cy="88.8" r=".25"/>
<circle cx="126.8" cy="88.8" r=".25"/>
</g>
<g fill="none" stroke="#006464" stroke-width=".21">
<path d="M113.3 36.1h.8l-.4 .5 .4 .1v.6l-.2 .1-.6-.1M114.7 36.1v1.3M114.7 34.2h.6l.1-.5-.7-.1v1.2M114.9 36.7l.5 .7M115 34.2l.5 .6M115.4 36.1l-.7 .7M115.8 36.1h.8l-.4 .5 .4 .1v.6l-.2 .1-.6-.1M115.9 33.6h.8l-.5 1.2M65.8 46.3a.58 .58 0 0 0-.8 .6 .58 .58 0 0 0 .8 .5v-.4h-.2M67.1 46.3v1.2l-.7-1.2v1.2M67.7 46.3a.64 .64 0 0 1 .7 .6 .64 .64 0 0 1-.7 .6zM69 46.3a.64 .64 0 0 1 .7 .6 .64 .64 0 0 1-.7 .6z"/>
<path d="M69.6 71.7h.7M69.6 70.8l.4-.4v1.3M70.9 70.5l.2-.1a.68 .68 0 0 1 .5 .6 .68 .68 0 0 1-.5 .7l-.3-.5zM70.9 76.1h.7v-.5l-.7-.1v1.2M70.9 68.5h.7v-.5l-.7-.1v1.2M71.2 77.9l-.3 1h.8M71.2 68.5l.5 .6M71.2 76.1l.5 .6M71.5 78.4v.9M72 78h.9l-.6 1.3M72.2 70.5l.1-.1a.68 .68 0 0 1 .5 .6 .68 .68 0 0 1-.5 .7l-.3-.5zM72.2 68l.4-.1 .3 .3-.8 .9h.8"/>
<path d="M72.2 75.6l.4-.1 .3 .3-.8 .9h.8M73.3 70.4v1.3M73.4 78v1.3M73.4 69.1h.7M73.4 68.2l.3-.3v1.2M73.5 70.9l.5 .8M73.5 78.5l.6 .8M74 70.4l-.7 .7M74 75.5h-.6v.6l.6-.1v.6l-.2 .1-.4-.1M74.1 78l-.7 .7M80.8 74.8h.9l-.9 1.3h.9M81 67.2v1.3h.6"/>
<path d="M82 67.7h.5l.1 .8M82.1 75.4l.2-.1 .4 .1-.1 .6h-.5zM82.6 67.9l-.6 .3 .2 .3 .4-.1M83.2 67.8l.4-.2 .1 .2M83.2 67.6v.9M83.3 75.4l.2-.1 .3 .1v.6h-.5zM83.7 67.8l.2-.2 .3 .1 .1 .8M83.7 67.8v.7M84.4 75.4l.4-.1 .2 .1M84.4 75.3v.8M84.9 67.7l.4-.1 .2 .3-.1 .5h-.5M84.9 67.6v1.3"/>
<path d="M85 75.4l.2-.1h.3v.8M85 75.4v.7M86.7 78.7l-.7 .1v.3l.6 .3 .1 .3-.2 .2-.5-.1M86.7 63.5h-.7v.4l.6 .2 .1 .3-.2 .3-.5-.1M86.7 71.1h-.7v.4l.6 .2 .1 .4-.2 .2-.5-.1M87.1 78.6l.3 1.3 .3-.9 .2 .9 .3-1.3M87.1 63.4l.3 1.3 .3-.9 .2 .9 .3-1.3M87.1 71l.3 1.3 .3-.9 .2 .9 .3-1.3M88.9 63.3l-.3 1h.8M89.2 71l-.3 .1-.2 .2-.1 .8 .3 .2 .4-.1-.1-.6-.3-.1-.3 .2M89.2 63.8v.9M89.3 78.6h-.6l-.1 .6h.6l.1 .6-.2 .1-.5-.1"/>
<path d="M82.9 82.9l-.9 .3 .9 .4M83.7 90.5l-1 .3 1 .4M84.5 82.9l-1 .3 1 .4M86.7 86.3l-.7 .1v.3l.6 .3 .1 .3-.2 .2h-.5M87.1 86.3l.3 1.2 .3-.9 .2 .9 .3-1.2M88.9 86.8l-.3-.2 .3-.3h.2l.3 .2-.3 .3M88.9 86.8l-.3 .2 .1 .4 .2 .1h.3l.2-.2v-.3l-.3-.2M88.9 86.8h.2M92.5 94.5h.7M92.5 93.6l.3-.4v1.3M92.5 91.4l.6-.1 .1-.5-.7-.1v1.3M92.8 91.4l.4 .6"/>
<path d="M93.7 90.8l.5-.1 .3 .4-.8 .9h.8M93.8 93.4l.2-.2a.68 .68 0 0 1 .4 .7 .68 .68 0 0 1-.4 .6l-.3-.5zM94.9 90.7h.8l-.5 .5 .4 .1v.5l-.2 .2-.5-.2M95.1 93.3l.1-.1a.68 .68 0 0 1 .4 .7 .68 .68 0 0 1-.4 .6 .84 .84 0 0 1-.1-1.2zM96.2 93.2v1.3M96.3 93.8l.6 .7M96.9 93.2l-.7 .8M124.3 90.7h.6l.1-.5-.7-.1v1.2M124.6 90.7l.5 .6M125.5 90.9l.6-.1v-.3h-.4l-.2 .2 .1 .6h.5M127.2 90.5h-.3l-.3 .2 .1 .6h.5M128.6 86.3l-.6 .1v.3l.5 .3 .1 .3-.2 .2h-.5"/>
<path d="M129 86.3l.3 1.2 .3-.9 .2 .9 .3-1.2M130.6 87.5h.7M130.6 86.6l.3-.3v1.2M131.8 87.5h.7M131.8 86.6l.3-.3v1.2"/>
</g>
<path d="M116.9 98h2.5v.5h-2.5z" fill-rule="evenodd" fill="#840000"/>
<path d="M116.9 98h2.5v.5h-2.5z" fill="none" stroke="#840000" stroke-width=".25"/>
<path d="M74.8 83.3h1.6v3.5h-1.6zM75.6 82.5v.8M75.6 86.8v.8M118.1 96.5v1.5" fill="none" stroke="#840000" stroke-width=".21"/>
<g fill="none" stroke="#006464" stroke-width=".21">
<path d="M70.9 85.7l.5-.1 .2 .4-.8 .9h.8M70.9 83.7h.7v-.5l-.7-.1v1.3M71.2 83.7l.5 .7M72.1 85.7l.5-.1 .2 .4-.8 .9h.8M72.2 83.2l.4-.1 .3 .3-.8 1h.8M73.4 85.6v1.3M73.5 86.2l.6 .7M73.6 83.6l-.2-.2 .2-.3h.2l.3 .2-.3 .3M73.6 83.6l-.2 .3v.3l.2 .2 .4-.1 .1-.2v-.2l-.3-.3M73.6 83.6h.2M74.1 85.6l-.7 .7M116.5 99.6a.58 .58 0 0 0-.7 .6 .58 .58 0 0 0 .8 .5v-.4h-.3"/>
<path d="M117.9 99.6v1.3l-.8-1.3v1.3M118.5 99.6a.64 .64 0 0 1 .7 .6 .64 .64 0 0 1-.7 .7zM119.7 99.6a.64 .64 0 0 1 .8 .6 .64 .64 0 0 1-.8 .7z"/>
</g>
<path d="M74.3 98h2.6v.5h-2.6z" fill-rule="evenodd" fill="#840000"/>
<path d="M174.6 52.7h2.6v7.6h-2.6zM74.3 98h2.6v.5h-2.6z" fill="none" stroke="#840000" stroke-width=".25"/>
<g fill="none" stroke="#840000" stroke-width=".21">
<path d="M156.7 39.5h1.5v3.5h-1.5zM157.5 38.7v.8M157.5 43v.8M157.5 45.7h2.5M157.5 50.8h2.5M160.9 45.9l3.2 2.1M165.1 48.2h2.5M170.8 59h3.8M170.8 56.5h3.8M170.8 53.9h3.8M174.6 53.8h1.3v.3h-1.3zM174.6 56.4h1.3v.2h-1.3z"/>
<path d="M174.6 58.9h1.3v.2h-1.3zM74.8 90.9h1.6v3.5h-1.6zM75.6 90.1v.8M75.6 94.4v.8M75.6 96.5v1.5M117.4 90.9h1.5v3.5h-1.5zM117.4 83.3h1.5v3.5h-1.5zM118.1 82.5v.8M118.1 86.8v.8M118.1 90.1v.8M118.1 94.4v.8"/>
<circle cx="160.5" cy="50.8" r=".51"/>
<circle cx="160.5" cy="45.7" r=".51"/>
<circle cx="164.6" cy="48.2" r=".51"/>
</g>
<g fill="none" stroke="#006464" stroke-width=".21">
<path d="M153.7 39.9l-.3 .9h.8M161.6 40h-.7v.4l.6 .3 .1 .3-.3 .2-.4-.1M162 39.9l.3 1.3 .3-.9 .2 .9 .3-1.3M152.2 40.6l.6-.1v-.5l-.6-.1v1.3M152.4 42.4l-.3 .9h.8M152.5 40.6l.4 .6M152.7 42.9v.8M153.3 42.5h.8l-.5 1.2M154 40.4v.8M154.6 42.5v1.2M154.8 43l.5 .7M155.3 42.5l-.7 .7"/>
<path d="M159.7 42.5h.8M160.1 42.5v1.2M160.9 42.9h.5v.8M161.4 43.2l-.6 .2 .2 .3h.4M162 42.9v.8M162.4 42.9l-.4 .2M163.4 42.9h-.4l-.2 .2 .1 .6h.5M163.4 42.9v1l-.3 .3-.3-.1M163.5 40l.5-.1 .2 .4-.7 .9h.7M163.9 43.3l.6-.1v-.3h-.4l-.2 .2 .1 .6h.5M164.9 42.9h.5M165.1 42.5v1.1l.3 .1"/>
<path d="M178.7 55.8h.7M179 55.8v1.3M179.8 56.3h.5v.8M180.3 56.5l-.6 .3 .2 .3 .4-.1M181 56.2v.9M181.3 56.2l-.3 .3M182.3 56.3l-.4-.1-.2 .3 .1 .5h.5M182.3 56.2v1l-.3 .3-.3-.1M182.8 56.6l.6-.1v-.2l-.4-.1-.2 .2 .1 .6h.5M183.8 56.2h.5M184 55.8v1.1l.3 .2M175.4 60.9l-.1 1.1-.4 .1"/>
<path d="M176.2 60.8l-.3 .9h.8M176.5 61.3v.8M70.9 94.5h.7M70.9 93.6l.3-.4v1.3M70.9 91.4l.7-.1v-.5l-.7-.1v1.3M71.2 91.4l.5 .6M72.1 90.7h.8l-.4 .5 .3 .1v.5l-.2 .2-.5-.2M72.3 93.3l.1-.1a.68 .68 0 0 1 .4 .7 .68 .68 0 0 1-.4 .6 .84 .84 0 0 1-.1-1.2zM73.4 93.2v1.3M73.5 93.8l.6 .7M74 99.6a.58 .58 0 0 0-.7 .6 .58 .58 0 0 0 .8 .5v-.4h-.3M74 90.7h-.6v.6l.6-.1v.6l-.2 .2-.4-.2"/>
<path d="M74.1 93.2l-.7 .8M75.3 99.6v1.3l-.7-1.3v1.3M75.9 99.6a.64 .64 0 0 1 .8 .6 .64 .64 0 0 1-.8 .7zM77.2 99.6a.64 .64 0 0 1 .7 .6 .64 .64 0 0 1-.7 .7zM113.4 94.5h.7M113.4 85.7l.5-.1 .2 .4-.8 .9h.8M113.4 93.6l.4-.4v1.3M113.5 91.4l.6-.1v-.5l-.6-.1v1.3M113.5 83.7h.6v-.5l-.6-.1v1.3M113.8 83.7l.4 .7M113.8 91.4l.4 .6M114.6 83.1h.8l-.4 .5 .3 .1v.5l-.1 .2-.6-.2"/>
<path d="M114.6 85.7l.5-.1 .2 .4-.7 .9h.7M114.8 93.3l.1-.1a.68 .68 0 0 1 .5 .7 .68 .68 0 0 1-.5 .6 .84 .84 0 0 1-.1-1.2zM115 90.6l-.3 .9h.8M115.3 91.1v.9M115.8 83.1h.9l-.6 1.3M115.9 85.6v1.3M115.9 93.2v1.3M116 90.8l.2-.1a.68 .68 0 0 1 .4 .6 .68 .68 0 0 1-.4 .7l-.3-.5zM116.1 86.2l.5 .7M116.1 93.8l.5 .7M116.6 85.6l-.7 .7M116.6 93.2l-.7 .8"/>
</g>
<path d="M158.3 51.1h.8l-.4 .5 .4 .1v.5l-.2 .1-.6-.1M158.4 47.3h.7M158.4 46.4l.3-.4v1.3M166 48.7l.5-.2 .2 .4-.8 .9h.8M172.3 52.3h.8l-.4 .4 .3 .2v.5l-.2 .1-.5-.1M172.3 58.6h.8M172.3 57.7l.4-.4v1.3M172.3 54.9l.5-.1 .3 .4-.8 .9h.8" fill="none" stroke="#a90000" stroke-width=".21"/>
<path d="M156.2 63.7h2.5v.5h-2.5z" fill-rule="evenodd" fill="#840000"/>
<path d="M156.2 63.7h2.5v.5h-2.5z" fill="none" stroke="#840000" stroke-width=".25"/>
<g fill="none" stroke="#840000" stroke-width=".21">
<path d="M156.7 56h1.5v3.5h-1.5zM157.5 55.2v.8M157.5 59.5v.8M117.4 68h1.5v3.6h-1.5zM117.4 75.6h1.5v3.6h-1.5zM118.1 67.3v.7M118.1 71.6v.7M118.1 74.9v.7M118.1 79.2v.8M121.9 66h2.6M121.9 73.6h2.6M124.5 80h2.5"/>
<path d="M124.5 64.7h2.5M124.5 72.3h2.5M125.7 64.7v2.6M125.7 72.3v2.6M125.7 80v2.5M127 66h2.6M127 73.6h2.6M157.5 62.2v1.5M121.9 81.2h2.6M127 81.2h2.6M132.6 90.9h1.5v3.5h-1.5zM133.4 90.1v.8"/>
<path d="M133.4 94.4v.8"/>
<circle cx="124.7" cy="73.6" r=".25"/>
<circle cx="124.7" cy="66" r=".25"/>
<circle cx="126.8" cy="66" r=".25"/>
<circle cx="126.8" cy="73.6" r=".25"/>
<circle cx="124.7" cy="81.2" r=".25"/>
<circle cx="126.8" cy="81.2" r=".25"/>
</g>
<g fill="none" stroke="#006464" stroke-width=".21">
<path d="M152.2 57.1l.6-.1v-.5l-.6-.1v1.3M152.4 58.9l-.3 .9h.8M152.5 57.1l.4 .6M152.7 59.4v.8M153.3 59h.8l-.5 1.2M153.4 56.5l.5-.1 .2 .4-.8 .9h.8M154.6 59v1.2M154.8 59.5l.5 .7M155.3 59l-.7 .7M112.1 71.7h.8M112.1 70.8l.4-.4v1.3M113.5 68.5h.6v-.5l-.6-.1v1.2"/>
<path d="M113.5 76.1h.6v-.5l-.6-.1v1.2M113.5 70.5l.1-.1a.68 .68 0 0 1 .5 .6 .68 .68 0 0 1-.5 .7l-.3-.5zM113.7 77.9l-.3 1h.8M113.8 68.5l.4 .6M113.8 76.1l.4 .6M114 78.4v.9M114.6 78h.8l-.5 1.3M114.6 67.9h.8l-.4 .4 .3 .2v.5l-.1 .1-.6-.1M114.6 75.5h.8l-.4 .5 .3 .1v.5l-.1 .1-.6-.1M114.7 70.5l.2-.1a.68 .68 0 0 1 .4 .6 .68 .68 0 0 1-.4 .7l-.3-.5zM115.8 70.4v1.3M115.9 78v1.3"/>
<path d="M115.9 68l.5-.1 .2 .3-.8 .9h.8M116 70.9l.5 .8M116.1 78.5l.5 .8M116.5 70.4l-.7 .7M116.6 78l-.7 .7M116.6 76l-.2 .3-.4-.1-.1-.6 .5-.1 .2 .2v.7l-.2 .3h-.4M124.6 67.3h-.7v.4l.6 .2 .1 .3-.2 .3-.5-.1M125 67.6h.4M125.1 67.2v1.1l.3 .2M125.3 75.3l.9 .3-.9 .4M125.9 67.8l.1-.2 .4 .2v.6h-.5zM127 67.7l.4-.1 .2 .3-.1 .5h-.5"/>
<path d="M127 67.6v1.3M128.6 78.7l-.6 .1v.3l.5 .3 .1 .3-.2 .2-.5-.1M129 78.6l.3 1.3 .3-.9 .2 .9 .3-1.3M129.2 63.5h-.6v.4l.5 .2 .1 .3-.2 .3-.5-.1M129.2 71.1h-.6v.4l.5 .2 .1 .4-.2 .2-.5-.1M129.6 63.4l.3 1.3 .3-.9 .2 .9 .3-1.3M129.6 71l.3 1.3 .3-.9 .2 .9 .3-1.3M130.6 79.9h.7M130.6 79l.3-.4v1.3M131.1 63.4h.8l-.5 1.3M131.9 78.8l.2-.2a.68 .68 0 0 1 .4 .7 .68 .68 0 0 1-.4 .6l-.3-.5zM131.9 71.6l-.3 .2-.3-.1-.1-.6 .4-.1 .3 .3-.1 .7-.2 .2-.3 .1"/>
<path d="M124.5 82.9l.9 .3-.9 .4M126 82.9l1 .3-1 .4M135 94.5h.7M135 93.6l.3-.4v1.3M135 91.4l.6-.1 .1-.5-.7-.1v1.3M135.3 91.4l.5 .6M136.3 92h.7M136.3 91.1l.3-.4v1.3M136.4 93.3l.1-.1a.68 .68 0 0 1 .4 .7 .68 .68 0 0 1-.4 .6 .84 .84 0 0 1-.1-1.2zM137.4 90.7h.8l-.4 .5 .3 .1v.5l-.2 .2-.5-.2M137.5 93.4l.2-.2a.68 .68 0 0 1 .4 .7 .68 .68 0 0 1-.4 .6l-.3-.5zM138.7 93.2v1.3"/>
<path d="M138.9 93.8l.5 .7M139.4 93.2l-.7 .8"/>
</g>
<path d="M154.9 78.1l1.1-.4v.7z" fill-rule="evenodd" fill="#840000"/>
<path d="M110.5 41.9v2M110.5 44.9v2.1M154.3 75.5v.7M154.3 80v.6M154.9 78.1h.3M154.9 78.1l1.1-.4v.7zM155.9 78.1h.9" fill="none" stroke="#840000" stroke-width=".21"/>
<path d="M153.5 76.3h1.6v3.6h-1.6z" fill="none" stroke="#840000" stroke-width=".25"/>
<path d="M154 75.7v.3M154 75.8h-.7l.2 .2M156.2 77.1h.2l.1 .2-.4 .4h.4M153.6 80.2v.1l-.3-.2v.4M153.6 80.1v.1M153.6 80.1h.3M153.9 80.1v.1M153.9 80.2v.3" fill="none" stroke="#a90000" stroke-width=".21"/>
<g fill="none" stroke="#006464" stroke-width=".21">
<path d="M112.1 46.6l.4-.3v1.2M112.1 47.5h.8M113.5 46.4l.1-.1a.68 .68 0 0 1 .5 .6 .68 .68 0 0 1-.5 .6l-.3-.4zM114.2 43.9a.56 .56 0 0 0-.8 .5 .56 .56 0 0 0 .8 .5M114.7 46.4l.2-.1a.68 .68 0 0 1 .4 .6 .68 .68 0 0 1-.4 .6l-.3-.4zM114.7 45h.7M114.7 44.1l.3-.4v1.3M115.8 46.7v.8M115.8 46.8h.5l.1 .7M115.8 43.7h.8l-.4 .5 .4 .1v.6l-.2 .1-.6-.1M149.5 78.6h.7M149.5 77.7l.3-.3v1.2"/>
<path d="M150.8 77.5l.2-.1a.68 .68 0 0 1 .4 .6 .68 .68 0 0 1-.4 .6l-.3-.4zM152 77.4v1.2M152.1 77.9l.6 .7M152.7 77.4l-.7 .7M155.4 81.2l.6-.1v-.4l-.6-.2v1.3M155.7 81.2l.4 .6M156.5 80.5l.4 1.3 .4-1.3M158.3 80.5h-.6v.6h.6v.6l-.1 .1-.5-.1"/>
</g>
<path d="M109 44.9h3" fill="none" stroke="#840000" stroke-width=".33"/>
<path d="M109 43.9h3" fill="none" stroke="#840000" stroke-width=".3"/>
<path d="M109.2 52.3h2.6v.5h-2.6z" fill-rule="evenodd" fill="#840000"/>
<path d="M109.2 52.3h2.6v.5h-2.6zM120.9 45.2h2.1M120.9 43.7h2.1l-1.1 1.5z" fill="none" stroke="#840000" stroke-width=".25"/>
<path d="M110.5 50.8v1.5M120.2 44.2v.2M120.2 44.4h.2M120.7 44.7v.2M120.7 44.9h.2M120.7 43.9l-.5 .5M121.2 44.4l-.5 .5M121.9 41.9v5.1" fill="none" stroke="#840000" stroke-width=".21"/>
<g fill="none" stroke="#006464" stroke-width=".21">
<path d="M120.9 46.9h.6l.1-.5-.7-.1v1.2M122.2 46.8l.2-.1 .4 .1-.1 .7-.5-.1zM123.2 46.7l.3 .8 .2-.6 .3 .6 .2-.8M123.5 43.7a.64 .64 0 0 1 .8 .7 .64 .64 0 0 1-.8 .6zM124.6 47.1l.6-.1v-.2l-.4-.1-.2 .2 .1 .6h.5M124.7 44.1l.4-.4v1.3M124.7 45h.8M125.8 46.7v.8M126.1 46.7l-.3 .2M127.9 46.1a1.46 1.46 0 0 0 0 1.9M128.9 46.8l-.3-.1-.3 .2 .1 .6h.5M128.9 46.7v1l-.2 .3-.3-.1"/>
<path d="M129.5 46.7v.8M129.9 46.7l-.4 .2M130.2 46.1a1.46 1.46 0 0 1 0 1.9"/>
</g>
<path d="M172.7 85l1-.3v.7z" fill-rule="evenodd" fill="#840000"/>
<path d="M172.1 82.5v.6M172.1 86.9v.7M172.7 85h.3M172.7 85l1-.3v.7zM173.6 85h1" fill="none" stroke="#840000" stroke-width=".21"/>
<path d="M171.3 83.2h1.5v3.6h-1.5z" fill="none" stroke="#840000" stroke-width=".25"/>
<path d="M171.7 87.4v-.3h-.3l-.1 .2-.2-.2v.4M171.7 87.4v.1M171.7 82.6v.4M171.7 82.8h-.6l.2 .2M174 84.1h-.1M174 84.1h.2l.1 .1-.4 .5h.4" fill="none" stroke="#a90000" stroke-width=".21"/>
<path d="M167.3 85.6h.7M167.3 84.7l.3-.3v1.2M168.6 84.5l.2-.1a.68 .68 0 0 1 .4 .6 .68 .68 0 0 1-.4 .6l-.3-.5zM169.7 84.4v1.2M169.9 84.9l.6 .7M170.5 84.4l-.8 .7M173.1 88.2l.6-.1 .1-.5-.7-.1v1.3M173.4 88.2l.5 .6M174.2 87.5l.5 1.3 .4-1.3M175.7 87.5l-.3 .9h.8M176 87.9v.9" fill="none" stroke="#006464" stroke-width=".21"/>
<path d="M170.8 98h2.5v.5h-2.5z" fill-rule="evenodd" fill="#840000"/>
<path d="M170.8 98h2.5v.5h-2.5z" fill="none" stroke="#840000" stroke-width=".25"/>
<path d="M172.1 96.5v1.5" fill="none" stroke="#840000" stroke-width=".21"/>
<path d="M170.5 99.6a.58 .58 0 0 0-.8 .6 .58 .58 0 0 0 .8 .5v-.4h-.2M171.8 99.6v1.3l-.7-1.3v1.3M172.4 99.6a.64 .64 0 0 1 .7 .6 .64 .64 0 0 1-.7 .7zM173.7 99.6a.64 .64 0 0 1 .7 .6 .64 .64 0 0 1-.7 .7z" fill="none" stroke="#006464" stroke-width=".21"/>
<path d="M191.7 91.4l1.1-.4v.8z" fill-rule="evenodd" fill="#840000"/>
<path d="M191.1 88.8v.7M191.1 93.3v.6M191.7 91.4h.3M191.7 91.4l1.1-.4v.8zM192.7 91.4h1" fill="none" stroke="#840000" stroke-width=".21"/>
<path d="M190.4 89.6h1.5v3.6h-1.5z" fill="none" stroke="#840000" stroke-width=".25"/>
<path d="M190.1 93.8v-.4l.3 .2v-.1h.3v.3M190.8 89v.3M190.8 89.2h-.7l.2 .1M193 90.5l.2-.1 .1 .2-.4 .4h.4" fill="none" stroke="#a90000" stroke-width=".21"/>
<path d="M186.3 92h.7M186.3 91.1l.4-.4v1.3M187.6 90.8l.2-.1a.68 .68 0 0 1 .4 .6 .68 .68 0 0 1-.4 .7l-.3-.5zM188.8 90.7v1.3M188.9 91.2l.6 .8M189.5 90.7l-.7 .7M192.2 94.5h.6v-.5l-.6-.1v1.2M192.5 94.5l.4 .6M193.3 93.9l.4 1.2 .4-1.2M194.5 94l.5-.1 .2 .3-.8 .9h.8" fill="none" stroke="#006464" stroke-width=".21"/>
<g fill="#009600">
<circle cx="75.6" cy="88.8" r=".46"/>
<circle cx="90.8" cy="73.6" r=".46"/>
<circle cx="90.8" cy="66" r=".46"/>
<circle cx="75.6" cy="66" r=".46"/>
<circle cx="75.6" cy="81.2" r=".46"/>
<circle cx="75.6" cy="73.6" r=".46"/>
<circle cx="110.5" cy="39.3" r=".46"/>
<circle cx="110.5" cy="49.5" r=".46"/>
<circle cx="133.4" cy="88.8" r=".46"/>
<circle cx="90.8" cy="88.8" r=".46"/>
<circle cx="90.8" cy="81.2" r=".46"/>
<circle cx="118.1" cy="96.5" r=".46"/>
<circle cx="75.6" cy="96.5" r=".46"/>
<circle cx="118.1" cy="81.2" r=".46"/>
<circle cx="118.1" cy="88.8" r=".46"/>
<circle cx="157.5" cy="36.8" r=".46"/>
<circle cx="169.5" cy="48.2" r=".46"/>
<circle cx="157.5" cy="62.2" r=".46"/>
<circle cx="133.4" cy="81.2" r=".46"/>
<circle cx="118.1" cy="73.6" r=".46"/>
<circle cx="118.1" cy="66" r=".46"/>
<circle cx="133.4" cy="66" r=".46"/>
<circle cx="133.4" cy="73.6" r=".46"/>
<circle cx="172.1" cy="96.5" r=".46"/>
<circle cx="172.1" cy="73" r=".46"/>
</g>
</svg>
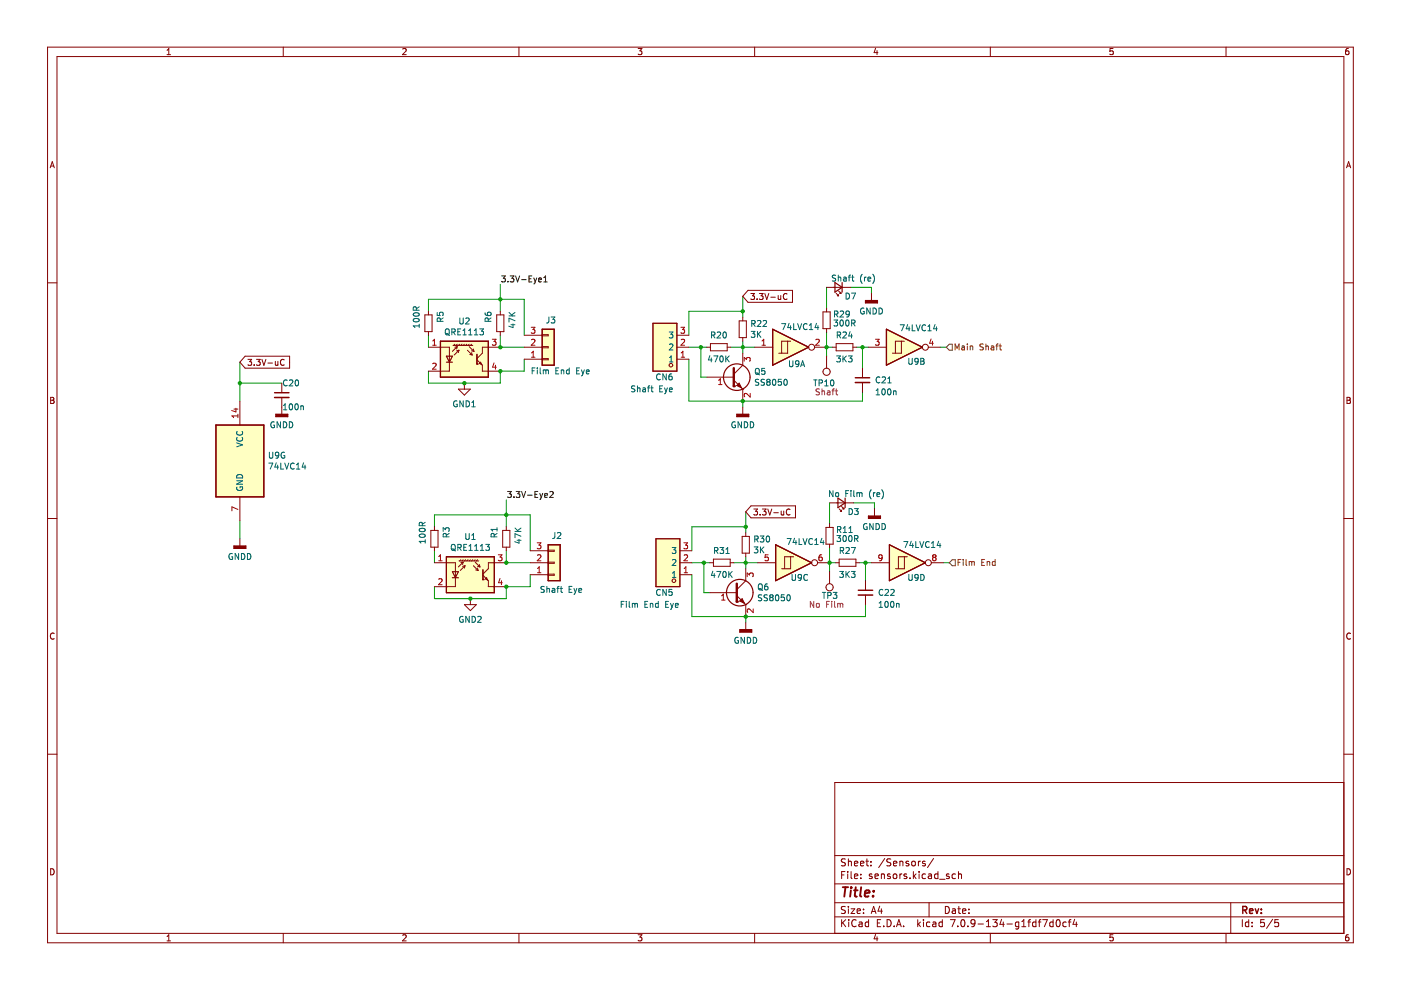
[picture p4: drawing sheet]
<svg xmlns="http://www.w3.org/2000/svg" width="297mm" height="210mm" viewBox="0 0 297 210" stroke-linecap="round" stroke-linejoin="round" font-family="sans-serif">
<g fill="none" stroke="#840000" stroke-width=".21">
<path d="M10.1 10h276.8v189.9h-276.8zM12.1 12h272.8v185.9h-272.8zM35.4 11.6h.8M35.4 10.7l.4-.4v1.3M60.1 10v2M85.4 10.4l.5-.1 .2 .4-.8 .9h.8M110 10v2M135.3 10.3h.8l-.4 .5 .3 .1v.6l-.1 .1-.6-.1M160 10v2M185.6 10.2l-.3 1h.8M185.9 10.7v.9M210 10v2"/>
<path d="M236 10.3h-.6l-.1 .6 .6-.1 .1 .7-.2 .1-.5-.1M259.9 10v2M285.9 10.3h-.4l-.2 .3v.7l.2 .3 .5-.1-.1-.7h-.4l-.2 .2M10.6 35.6l.5-1.3 .4 1.3M10.8 35.2h.6M285.5 35.6l.4-1.3 .5 1.3M285.6 35.2h.6M10.1 60h2M284.9 60h2M10.7 84.2h.5l.2 .3-.2 .4 .2 .1 .1 .3-.3 .2h-.5zM10.7 84.9h.5M285.6 84.2h.4l.3 .3-.3 .4 .3 .1v.3l-.2 .2h-.5z"/>
<path d="M285.6 84.9h.4M10.1 109.9h2M284.9 109.9h2M11.5 134.3a.58 .58 0 0 0-.8 .6 .58 .58 0 0 0 .8 .5M286.3 134.3a.58 .58 0 0 0-.8 .6 .58 .58 0 0 0 .8 .5M10.1 159.9h2M284.9 159.9h2M284.9 165.9h-107.9v32M10.7 184.2a.66 .66 0 0 1 .8 .6 .66 .66 0 0 1-.8 .7zM35.4 198.6l.4-.4v1.3M35.4 199.5h.8M60.1 197.9v2"/>
<path d="M85.4 198.3l.5-.1 .2 .4-.8 .9h.8M110 197.9v2M135.3 198.2h.8l-.4 .5 .3 .1v.6l-.1 .1-.6-.1M160 197.9v2M177 194.4h107.9M177 191.4h107.9M177 187.4h107.9M177 181.4h107.9M178.4 195v1.5M178.4 185.5h.5M178.7 195.6l.6 .9M179.2 184.8h-.8v1.5"/>
<path d="M179.2 192.3l-.5-.1-.3 .1v.5l.7 .2 .1 .4-.3 .3-.5-.1M179.2 182.2l-.5-.1-.3 .1v.5l.7 .2 .1 .4-.3 .3-.5-.1M179.3 195l-.9 .8M179.7 184.8v.1M179.7 185.3v1M179.9 182.1v1.5M179.9 192.2v.1M179.9 192.7v1M179.9 182.7l.2-.1 .3 .1 .1 .9M179.9 195v.1M179.9 195.5v1M180.4 192.7h.8l-.8 1h.8"/>
<path d="M180.4 184.8v1.3l.3 .2M181.2 185.8l.7-.2-.1-.2-.4-.1-.2 .2v.7h.6M181.2 183.1l.7-.2-.1-.2-.4-.1-.2 .2v.7h.6M181.5 195.1a.71 .71 0 0 0-1 .5 .71 .71 0 0 0 .7 .9l.3-.2M181.7 193.2l.7-.2v-.2l-.5-.1-.2 .2 .1 .7h.6M182.2 195.6h.5l.1 .9M182.4 183.1l.8-.2-.1-.2-.4-.1-.3 .2 .1 .7h.6M182.5 186.1v.2M182.5 185.4v.1M182.8 195.8l-.5 .1-.2 .2 .2 .4 .5-.1M183.1 193.5v.2M183.1 192.8v.1"/>
<path d="M183.6 182.6h.6M183.8 182.1v1.3l.4 .2M184.2 195.6l-.5-.1-.3 .3 .2 .6h.6M184.2 195v1.5M184.7 183.4v.2M184.7 182.7v.1M184.7 193.7l.5-1.5 .5 1.5M184.9 185.4l-.4-.1-.2 .2 .1 .2 .5 .2v.3h-.6M184.9 193.3h.7M185.5 185.8l.7-.2v-.2l-.5-.1-.2 .2 .1 .7h.6M185.6 198.1l-.3 1h.8M185.9 198.6v.9"/>
<path d="M186 195.7h.5M186.5 192.1l-.3 1.1h.9M186.7 195h-.7v1.5h.7M186.9 185.3v1M186.9 185.4l.2-.1 .3 .1 .1 .9M186.9 192.7v1M187.4 196.3v.2M187.6 182l-1.3 1.9M188.1 195a.76 .76 0 0 1 .8 .7 .76 .76 0 0 1-.8 .8zM188.7 185.4l-.3-.1-.2 .2v.2l.5 .2v.3h-.5M188.9 182.2l-.6-.1-.2 .1v.5l.6 .2 .2 .4-.3 .3-.6-.1M189.4 185.4l.3-.1 .4 .1 .1 .6-.2 .2-.3 .1-.3-.2z"/>
<path d="M189.4 183.1l.8-.2-.1-.2-.4-.1-.3 .2 .1 .7h.6M189.6 196.3v.2M190.1 196.5l.5-1.5 .5 1.5M190.2 196.1h.7M190.8 182.6v1M190.8 185.3v1M190.8 182.7l.2-.1 .4 .1v.9M191.2 185.3l-.4 .3M191.6 196.3v.2M192.2 185.4l-.3-.1-.2 .2v.2l.5 .2v.3h-.5M192.7 182.7l-.4-.1-.2 .2 .1 .2 .5 .2v.3h-.6M192.9 186.1v.2"/>
<path d="M193.4 182.7l.2-.1 .4 .1 .1 .6-.2 .2-.3 .1-.2-.2zM193.7 184.8v1.5M193.8 185.7l.4 .6M194.2 185.3l-.5 .6M194.6 195v1.5M194.7 182.6v1M194.7 195.9l.5 .6M194.9 184.8v.1M194.9 185.3v1M195.2 182.6l-.5 .3M195.2 195.5l-.6 .6M195.8 195v.1"/>
<path d="M195.8 195.5v1M196.1 182.7l-.3-.1-.2 .2v.2l.5 .2v.3h-.5M196.2 185.4l-.4-.1-.3 .3 .1 .6h.6M196.9 185.4h.5l.1 .9M197 191.4v3M197.1 195.6l-.4-.1-.3 .3 .2 .6h.5M197.5 185.6l-.5 .1-.2 .2 .2 .4 .5-.1M197.8 195.6h.6v.9M197.9 182l-1.3 1.9M198.4 195.8l-.5 .1-.2 .2 .2 .4 .5-.1M198.9 185.4l-.5-.1-.3 .3 .2 .6h.6M198.9 184.8v1.5"/>
<path d="M199.2 186.4h1.2M199.8 195.6l-.4-.1-.3 .3 .1 .6h.6M199.8 195v1.5M200.4 192.2a.76 .76 0 0 1 .9 .7 .76 .76 0 0 1-.9 .8zM201.2 185.4l-.3-.1-.3 .2 .1 .2 .5 .2v.3h-.6M201.5 195h1l-.6 1.5M201.9 192.8h.6l.1 .9M202.6 193l-.5 .1-.2 .2 .2 .4 .5-.1M202.6 185.4l-.5-.1-.2 .3 .1 .6h.6M203.1 192.7h.5M203.1 196.3v.2M203.2 185.4l.2-.1 .4 .1 .1 .9"/>
<path d="M203.2 184.8v1.5M203.3 192.2v1.3l.3 .2M203.9 195.1l.2-.1a.8 .8 0 0 1 .5 .7 .8 .8 0 0 1-.5 .8l-.4-.6zM204.1 193.2l.7-.2-.1-.2-.4-.1-.2 .2v.7h.6M205.2 196.3v.2M205.4 193.5v.2M205.4 192.8v.1M206.7 195.6l-.3 .3h-.3l-.2-.3v-.3l.2-.3 .5 .1 .1 .2a1 1 0 0 1-.4 1.2h-.3M207.4 195.9h1.1M209.1 196.5h.9M209.1 195.4l.5-.4v1.5M210 197.9v2"/>
<path d="M210.5 195h.9l-.5 .6 .5 .1v.6l-.3 .2-.6-.2M212.4 194.9l-.4 1.1h.9M212.7 195.5v1M213.5 195.9h1.1M216 195.6l-.4-.1-.3 .3 .1 .6h.6M216 195.5v1.2l-.3 .3-.3-.1M216.6 196.5h.9M216.6 195.4l.5-.4v1.5M217.9 195.5h.6M218.5 195l-.4 .2v1.3M219.6 195.6l-.4-.1-.3 .3 .2 .6h.5M219.6 195v1.5"/>
<path d="M220.1 195.5h.6M220.7 195l-.3 .2v1.3M221.1 195h1l-.7 1.5M223.3 195.6l-.5-.1-.2 .3 .1 .6h.6M223.3 195v1.5M224.1 195.1l.2-.1a.8 .8 0 0 1 .5 .7 .8 .8 0 0 1-.5 .8l-.4-.6zM226.1 195.6l-.5-.1-.3 .3 .2 .6h.6M226.5 195.5h.6M227.1 195l-.4 .2v1.3M227.8 194.9l-.3 1.1h.9M228.2 195.5v1M236 198.2h-.6l-.1 .6 .6-.1 .1 .7-.2 .1-.5-.1"/>
<path d="M259.9 197.9v2M260.9 191.4v6.5M263.4 195v1.5M264.8 195.6l-.5-.1-.3 .3 .2 .6h.6M264.8 195v1.5M265.5 196.3v.2M265.5 195.6v.1M268 195h-.7v.7l.2-.1h.5l.1 .2-.1 .5-.2 .2-.5-.2M269.8 194.9l-1.3 1.9M271 195h-.7v.7l.2-.1h.5l.1 .2-.1 .5-.2 .2-.5-.2M285.6 184.2a.66 .66 0 0 1 .7 .6 .66 .66 0 0 1-.7 .7zM285.9 198.2l-.4 .1-.2 .2v.7l.2 .3 .5-.1-.1-.7h-.4l-.2 .2"/>
</g>
<path d="M263.5 193l.7-.1 .2-.2-.1-.4-.8-.1v1.5M263.9 193l.5 .7M264.9 193.2l.7-.2v-.3h-.5l-.2 .2 .1 .7h.6M266.1 192.7l.4 1 .4-1M267.4 193.5v.2M267.4 192.7v.2" fill="none" stroke="#840000" stroke-width=".3"/>
<path d="M178.7 188.1h1.1M179.3 188.1l-.3 2M180.4 188.8l-.2 1.3M180.5 188.1v.2M181.1 188.8h.7M181.4 188.1l-.2 1.7 .1 .2 .4 .1M182.6 188.1l-.2 1.7 .2 .3M183.4 189.4l.9-.2v-.3h-.8l-.2 .9 .3 .3 .6-.1M185.1 189.9v.2M185.2 188.9v.2" fill="none" stroke="#840000" stroke-width=".4"/>
<path d="M93.4 72.3h10.1v7.7h-10.1z" fill-rule="evenodd" fill="#ffffc2"/>
<path d="M93.4 72.3h10.1v7.7h-10.1z" fill="none" stroke="#840000" stroke-width=".25"/>
<path d="M45.8 90.1h10.1v15.3h-10.1z" fill-rule="evenodd" fill="#ffffc2"/>
<path d="M45.8 90.1h10.1v15.3h-10.1z" fill="none" stroke="#840000" stroke-width=".25"/>
<path d="M94.6 118h10.2v7.7h-10.2z" fill-rule="evenodd" fill="#ffffc2"/>
<path d="M94.6 118h10.2v7.7h-10.2z" fill="none" stroke="#840000" stroke-width=".25"/>
<path d="M187.9 69.8l7.7 3.8-7.7 3.8z" fill="#ffffc2"/>
<path d="M187.9 69.8l7.7 3.8-7.7 3.8z" fill="none" stroke="#840000" stroke-width=".25"/>
<path d="M163.8 69.8l7.6 3.8-7.6 3.8z" fill="#ffffc2"/>
<path d="M163.8 69.8l7.6 3.8-7.6 3.8z" fill="none" stroke="#840000" stroke-width=".25"/>
<path d="M164.5 115.5l7.6 3.8-7.6 3.8z" fill="#ffffc2"/>
<path d="M164.5 115.5l7.6 3.8-7.6 3.8z" fill="none" stroke="#840000" stroke-width=".25"/>
<path d="M188.6 115.5l7.6 3.8-7.6 3.8z" fill="#ffffc2"/>
<path d="M188.6 115.5l7.6 3.8-7.6 3.8z" fill="none" stroke="#840000" stroke-width=".25"/>
<path d="M115 69.8h2.5v7.6h-2.5z" fill-rule="evenodd" fill="#ffffc2"/>
<path d="M115 69.8h2.5v7.6h-2.5z" fill="none" stroke="#840000" stroke-width=".25"/>
<path d="M138.4 68.5h5.1v10.2h-5.1z" fill-rule="evenodd" fill="#ffffc2"/>
<path d="M138.4 68.5h5.1v10.2h-5.1z" fill="none" stroke="#840000" stroke-width=".21"/>
<path d="M139.1 114.2h5.1v10.2h-5.1z" fill-rule="evenodd" fill="#ffffc2"/>
<path d="M139.1 114.2h5.1v10.2h-5.1z" fill="none" stroke="#840000" stroke-width=".21"/>
<path d="M116.2 115.5h2.6v7.6h-2.6z" fill-rule="evenodd" fill="#ffffc2"/>
<path d="M94.6 76.8h1.3M116.2 115.5h2.6v7.6h-2.6z" fill="none" stroke="#840000" stroke-width=".25"/>
<g fill="none" stroke="#009600" stroke-width=".21">
<path d="M50.9 76.8v8.2M90.8 66v-2.5h20.4v7.6M90.8 71.1v2.5M106.1 60.3v5.7M106.1 71.1v2.5h5.1M111.2 76.2v2.5h-5.1v2.5h-15.3v-2.5M146.1 73.6h3.8M146.1 76.2v8.8h36.8v-1.9M148.6 73.6v6.4h1.3M154.9 73.6h5.1M157.5 62.8v4.5M157.5 72.3v2.6"/>
<path d="M157.5 66h-11.4v5.1M175.2 73.6h1.3M175.2 60.9v4.5M175.2 70.4v5.1M180.3 60.9h4.5v1.3M181.6 73.6h2.5M182.9 73.6v4.5M199.4 73.6h1.2M50.9 81.2h8.8M157.5 85v1.3M50.9 110.4v3.8M92.1 111.7v-2.5h20.3v7.6"/>
<path d="M92.1 116.8v2.5M107.3 106v5.7M107.3 116.8v2.5h5.1M146.7 119.3h3.8M149.2 119.3v6.4h1.3M155.6 119.3h5.1M158.1 108.5v4.5M158.1 118v2.6M158.1 111.7h-11.4v5.1M175.9 119.3h1.3M175.9 106.6v4.5M175.9 116.1v5.1"/>
<path d="M181 106.6h4.4v1.3M182.2 119.3h2.6M183.5 119.3v3.8M200 119.3h1.3M112.4 121.9v2.5h-5.1v2.5h-15.2v-2.5M146.7 121.9v8.8h36.8v-2.5M158.1 130.7v1.3"/>
</g>
<g fill="none" stroke="#0f0f0f" stroke-width=".21">
<path d="M106.4 58.5h.7l-.4 .5 .4 .1v.6l-.2 .1-.5-.1M107.7 59.7v.1M108.2 58.5h.8l-.5 .5 .4 .1v.6l-.2 .1-.5-.1M109.3 58.5l.4 1.3 .5-1.3M110.6 59.3h1M112.2 59.1h.4M112.8 58.5h-.6v1.3h.6M113.2 58.9l.3 .9M113.5 59.8l-.3 .4M113.8 58.9l-.3 .9M114.2 59.4l.6-.2v-.2l-.4-.1-.2 .2 .1 .6h.5M115.3 59.8h.7"/>
<path d="M115.3 58.9l.4-.4v1.3M107.6 104.2h.8l-.4 .5 .3 .1v.6l-.1 .1-.6-.1M109 105.4v.1M109.4 104.2h.8l-.4 .5 .4 .1v.6l-.2 .1-.6-.1M110.6 104.2l.4 1.3 .4-1.3M111.9 105h.9M113.4 104.8h.4M114 104.2h-.6v1.3h.6M114.5 104.6l.3 .9M114.8 105.5l-.3 .4M115.1 104.6l-.3 .9M115.5 105l.6-.1-.1-.2-.3-.1-.2 .2v.6h.5"/>
<path d="M116.6 104.3l.5-.1 .2 .4-.8 .9h.8"/>
</g>
<g fill="none" stroke="#840000" stroke-width=".21">
<path d="M52 75.5h9.4v2.6h-9.4l-1.1-1.3zM52.6 76.2h.8l-.5 .5 .4 .1v.5l-.2 .2-.5-.2M53.9 77.3v.2M54.4 76.2h.8l-.5 .5 .4 .1v.5l-.2 .2-.5-.2M55.5 76.2l.5 1.3 .4-1.3M56.8 77h1M58.4 76.6v.8l.5-.1M58.9 76.6v.9M60.2 76.3a.56 .56 0 0 0-.7 .5 .56 .56 0 0 0 .7 .5M96 73.2h4.2M96.4 73l-.2 .2M96.9 73l-.2 .2"/>
<path d="M96.9 73.5l-.1 .5M96.9 73.5l-1 1M96.9 73.5l-.5 .1M97.3 74.3l-.1 .5M97.3 74.3l-1 1M97.3 74.3l-.5 .1M97.4 73l-.2 .2M97.9 73l-.2 .2M98.5 73l-.3 .2M99 73l-.3 .2M99.1 74.3l1 1M99.5 73l-.3 .2"/>
<path d="M99.5 73.5l1 1M99.6 75.1l.5 .2M100 73l-.3 .2M100 74.4l.5 .1M100 74.8l.1 .5M100.4 74l.1 .5M101.1 76.3l1.2 1.1M102.3 74.9l-1.2 1.1M158.6 61.6h9.4v2.5h-9.4l-1.1-1.3zM159.2 62.2h.8l-.4 .5 .3 .1v.6l-.2 .1-.5-.1M160.5 63.4v.1M161 62.2h.8l-.4 .5 .3 .1v.6l-.2 .1-.5-.1"/>
<path d="M162.2 62.2l.4 1.3 .4-1.3M163.4 63h1M165 62.7l.1 .7h.4M165.5 62.7v.8M166.9 62.4a.56 .56 0 0 0-.8 .5 .56 .56 0 0 0 .8 .5M159.2 107.3h9.5v2.5h-9.5l-1.1-1.3zM159.8 107.9h.8l-.4 .5 .3 .1v.6l-.1 .1-.6-.1M161.2 109.1v.1M161.6 107.9h.8l-.4 .5 .4 .1v.6l-.2 .1-.6-.1M162.8 107.9l.4 1.3 .4-1.3M164.1 108.7h.9M165.6 108.3l.1 .8h.5"/>
<path d="M166.2 108.3v.9M167.5 108a.56 .56 0 0 0-.8 .6 .56 .56 0 0 0 .8 .5"/>
</g>
<g fill="none" stroke="#725600" stroke-width=".21">
<path d="M201.3 73h.6v1.3h-.6l-.7-.7zM202.5 74.2v-1.3l.4 .9 .4-.9v1.3M203.9 73.4h.5l.1 .8M204.5 73.7l-.6 .2 .2 .3 .4-.1M205.1 72.9v.1M205.1 73.4v.8M205.7 73.5l.5-.1v.8M205.7 73.4v.8M208.5 73h-.7v.4l.6 .3 .1 .3-.3 .2-.4-.1M209 73.5l.5-.1 .1 .8M209 72.9v1.3M210.2 73.4h.5v.8"/>
<path d="M210.7 73.7l-.6 .2 .2 .3 .4-.1M211.1 73.4h.5M211.6 72.9l-.3 .2v1.1M211.9 73.4h.4M212 72.9v1.1l.3 .2M201.9 118.7h.6v1.2h-.6l-.6-.6zM203.1 119.2h.5M203.7 118.6h-.6v1.3M204.2 118.6v.1M204.2 119v.9M204.8 118.6v1.1l.2 .2M205.5 119v.9"/>
<path d="M205.5 119.2l.4-.2 .1 .2M206 119.2l.2-.2 .3 .1 .1 .8M206 119.2v.7M208.1 119.2h.5M208.8 118.6h-.7v1.3h.7M209.3 119.2l.5-.1v.8M209.3 119v.9M211 119.1l-.4-.1-.2 .3 .1 .5h.5M211 118.6v1.3"/>
</g>
<path d="M101.1 75.1v2.1" fill="none" stroke="#840000" stroke-width=".36"/>
<circle cx="101.1" cy="77.2" r=".18" fill="#840000"/>
<g fill="none" stroke="#840000" stroke-width=".21">
<path d="M90.1 66.8h1.5v3.5h-1.5zM90.8 73.6h4.5v5.1h-4.5M90.8 66v.8M90.8 70.3v.8M101.9 76.8l.2 .5-.5-.3zM102.3 77.4v1.3h3.8M105.3 66.8h1.5v3.5h-1.5zM106.1 73.6h-3.8v1.3M106.1 66v.8M106.1 70.3v.8M59.7 81.2v2.1M59.7 84.3v2"/>
<path d="M97.2 82.5h2.5l-1.2 1.3zM98.5 81.2v1.3"/>
</g>
<path d="M93.4 72.3h10.1v7.7h-10.1zM94.6 75.5h1.3l-.6 1.3z" fill="none" stroke="#840000" stroke-width=".25"/>
<path d="M91.7 73.2h.8M91.7 72.3l.4-.4v1.3M91.7 77.1l.5-.1 .3 .4-.8 .9h.8M104.4 71.9h.8l-.5 .5 .4 .1v.6l-.2 .1-.5-.1M104.7 76.9l-.3 1h.8M105 77.4v.9" fill="none" stroke="#a90000" stroke-width=".21"/>
<g fill="none" stroke="#006464" stroke-width=".21">
<path d="M87.7 66.5a.75 .75 0 0 1 1.2 .2 .72 .72 0 0 1-1.3-.1zM87.7 67.7a.75 .75 0 0 1 1.2 .2 .72 .72 0 0 1-1.3-.1zM88.3 65.8l-.1-.6-.5-.1-.1 .7h1.3M88.9 68.7v.8M88.9 69.1h-1.3l.4 .4M88.9 65l-.6 .5M92.7 66.3v.6h.6l-.1-.6h.6l.2 .1-.2 .5M93.4 68.1l-.1-.6h-.5l-.1 .6h1.3M94 67.4l-.6 .4M94.5 69.9l.2-.2a.43 .43 0 0 1 .6 .5v.4a.42 .42 0 0 1-.5 .4 .42 .42 0 0 1-.4-.4zM94.6 70.7l.7 .4M95.8 70.4l.6-.1 .1-.4-.7-.2v1.3"/>
<path d="M96.1 70.4l.4 .6M97.1 70.3h.4M97.5 67.4v1l.2 .3 .4-.1 .1-.2v-1M97.7 69.7h-.6v1.3h.6M98.2 71h.7M98.2 70.1l.3-.4v1.3M98.8 67.5l.4-.1 .3 .4-.8 .9h.8M99.4 71h.7M99.4 70.1l.3-.4v1.3M100.6 71h.7M100.6 70.1l.3-.4v1.3M101.7 69.7h.8l-.4 .5 .3 .1v.6l-.1 .1-.6-.1"/>
<path d="M102.8 66.3l.1 .4 .2 .2h.8l.2-.2-.1-.4h-.6l-.1 .4 .3 .2M103.5 68.1l-.1-.6h-.4l-.2 .6h1.3M104.1 67.4l-.6 .4M107.9 67h1.3M107.9 66.3l.7 .7M108.3 68.9h.9M108.8 68.7v.8l-.9-.3M109.2 68l-1.3-.5v.8M109.2 66.3l-.7 .5M60.1 86.9h.7M60.1 86l.4-.4v1.3M60.9 80.7a.56 .56 0 0 0-.8 .5 .56 .56 0 0 0 .8 .5"/>
<path d="M61.4 80.7l.5-.2 .2 .4-.8 .9h.8M61.5 85.7l.1-.1a.68 .68 0 0 1 .4 .7 .68 .68 0 0 1-.4 .6 .84 .84 0 0 1-.1-1.2zM62.7 85.7l.1-.1a.68 .68 0 0 1 .5 .7 .68 .68 0 0 1-.5 .6 .84 .84 0 0 1-.1-1.2zM62.7 80.7l.2-.2a.68 .68 0 0 1 .4 .7 .68 .68 0 0 1-.4 .6l-.3-.5zM63.8 86.2l.5-.1v.8M63.8 86v.9M96.9 85a.58 .58 0 0 0-.7 .6 .58 .58 0 0 0 .7 .5v-.4h-.2M98.2 85v1.3l-.7-1.3v1.3M98.8 85a.64 .64 0 0 1 .8 .6 .64 .64 0 0 1-.8 .7zM100 86.3h.8M100 85.3l.4-.3v1.3"/>
</g>
<path d="M58.2 84.3h3.1" fill="none" stroke="#840000" stroke-width=".33"/>
<path d="M58.2 83.3h3.1" fill="none" stroke="#840000" stroke-width=".3"/>
<path d="M58.5 87.8h2.5v.5h-2.5z" fill-rule="evenodd" fill="#840000"/>
<path d="M45.8 90.1h10.1v15.3h-10.1zM58.5 87.8h2.5v.5h-2.5z" fill="none" stroke="#840000" stroke-width=".25"/>
<path d="M50.9 85v5.1M59.7 86.3v1.5M50.9 105.4v5" fill="none" stroke="#840000" stroke-width=".21"/>
<g fill="none" stroke="#006464" stroke-width=".21">
<path d="M50.2 93.9l1.2 .4-1.2 .4M50.3 92.7a.56 .56 0 0 0 .5 .8 .56 .56 0 0 0 .5-.8M50.3 91.5a.56 .56 0 0 0 .5 .8 .56 .56 0 0 0 .5-.8M57 98.2h.8l-.5 1.3M57.1 95.9v1l.3 .2h.3l.1-.2v-1M58.1 89.5a.58 .58 0 0 0-.7 .6 .58 .58 0 0 0 .8 .5v-.4h-.2M58.6 98.1l-.3 .9h.7M58.9 98.6v.9M59.1 96.4l-.2 .3-.4-.1-.1-.6 .5-.1 .2 .2-.1 .7-.1 .3h-.4M59.5 89.4v1.3l-.8-1.3v1.3M59.5 98.2v1.3h.6M60.1 89.4a.64 .64 0 0 1 .7 .7 .64 .64 0 0 1-.7 .6z"/>
<path d="M60.3 95.9a.58 .58 0 0 0-.7 .6 .58 .58 0 0 0 .8 .5v-.4h-.3M60.4 98.2l.4 1.3 .4-1.3M61.3 89.4a.64 .64 0 0 1 .8 .7 .64 .64 0 0 1-.8 .6zM62.4 98.3a.56 .56 0 0 0-.8 .5 .56 .56 0 0 0 .8 .5M62.9 99.5h.7M62.9 98.5l.3-.3v1.3M64.4 98.1l-.3 .9h.7M64.7 98.6v.9M50.2 101.9h1.2l-1.2 .8h1.2M50.2 100.9a.68 .68 0 0 1 .8-.3 .68 .68 0 0 1 .4 .7h-1.2zM50.2 103.3a.58 .58 0 0 0 .6 .7 .58 .58 0 0 0 .5-.8h-.4v.2"/>
</g>
<path d="M49.6 86.7h.8M50 86.6v.7l-.9-.3M50.4 87.8v.7M50.4 88.2h-1.2l.3 .3M50.4 108l-1.2-.5v.8" fill="none" stroke="#a90000" stroke-width=".21"/>
<path d="M49.6 115.8h2.5v.5h-2.5z" fill-rule="evenodd" fill="#840000"/>
<path d="M49.6 115.8h2.5v.5h-2.5zM95.9 122.5h1.3" fill="none" stroke="#840000" stroke-width=".25"/>
<g fill="none" stroke="#840000" stroke-width=".21">
<path d="M50.9 114.2v1.6M91.3 112.5h1.6v3.5h-1.6zM92.1 111.7v.8M92.1 116v.8M97.3 118.9h4.2M97.7 118.7l-.3 .2M98.2 118.7l-.3 .2M98.2 119.2l-.1 .5M98.2 119.2l-1 1M98.2 119.2l-.5 .1M98.6 119.9l-.1 .6M98.6 119.9l-1 1.1"/>
<path d="M98.6 119.9l-.5 .2M98.7 118.7l-.2 .2M99.2 118.7l-.2 .2M99.7 118.7l-.2 .2M100.2 118.7l-.2 .2M100.4 119.9l1 1.1M100.7 118.7l-.2 .2M100.7 119.2l1.1 1M101.2 118.7l-.2 .2M101.6 119.7l.2 .5M106.6 112.5h1.5v3.5h-1.5zM107.3 111.7v.8"/>
<path d="M107.3 116v.8M100.9 120.8l.5 .2M101.2 120.1l.6 .1M101.2 120.5l.2 .5M102.4 122l1.1 1.1M103.5 120.6l-1.1 1.1"/>
</g>
<g fill="none" stroke="#006464" stroke-width=".21">
<path d="M49.3 117.4a.58 .58 0 0 0-.8 .6 .58 .58 0 0 0 .8 .5v-.4h-.2M50.6 117.4v1.2l-.7-1.2v1.2M51.2 117.4a.64 .64 0 0 1 .7 .6 .64 .64 0 0 1-.7 .6zM52.5 117.4a.64 .64 0 0 1 .7 .6 .64 .64 0 0 1-.7 .6zM88.9 112.2a.75 .75 0 0 1 1.3 .2 .72 .72 0 0 1-1.3-.1zM88.9 113.4a.75 .75 0 0 1 1.3 .2 .72 .72 0 0 1-1.3-.1zM89.5 111.5v-.6l-.5-.1-.1 .7h1.3M90.2 114.4v.8M90.2 114.8h-1.3l.3 .4M90.2 110.7l-.7 .5M94 112.7v-.8l.4 .4 .2-.4h.5l.1 .2-.1 .6M94.6 113.8v-.6h-.5l-.1 .6h1.2"/>
<path d="M95.2 113.1l-.6 .4M104.8 113.8l-.1-.6h-.5l-.1 .6h1.3M105.4 113.1l-.6 .4M105.4 111.9v.7M105.4 112.3h-1.3l.4 .3M109.2 112.7h1.3M109.2 111.9l.7 .8M109.6 114.5h.9M110 114.4v.8l-.9-.4M110.5 113.7l-1.3-.5v.8M110.5 111.9l-.8 .6"/>
</g>
<path d="M102.4 120.8v2.1" fill="none" stroke="#840000" stroke-width=".36"/>
<circle cx="102.4" cy="122.9" r=".18" fill="#840000"/>
<path d="M92.1 119.3h4.5v5.1h-4.5M107.3 119.3h-3.8v1.3M98.5 128.2h2.5l-1.3 1.3zM99.7 126.9v1.3M103.2 122.5l.2 .5-.5-.3zM103.5 123.1v1.3h3.8" fill="none" stroke="#840000" stroke-width=".21"/>
<path d="M94.6 118h10.2v7.7h-10.2zM95.9 121.2h1.3l-.6 1.3z" fill="none" stroke="#840000" stroke-width=".25"/>
<path d="M93 118.9h.7M93 118l.4-.4v1.3M105.7 117.6h.7l-.4 .5 .4 .1v.6l-.2 .1-.5-.1M93 122.8l.5-.1 .2 .4-.7 .9h.7M106 122.6l-.3 .9h.8M106.3 123.1v.9" fill="none" stroke="#a90000" stroke-width=".21"/>
<g fill="none" stroke="#006464" stroke-width=".21">
<path d="M95.7 115.6l.3-.2a.43 .43 0 0 1 .5 .4v.5a.42 .42 0 0 1-.4 .4 .42 .42 0 0 1-.4-.4zM95.9 116.4l.7 .4M97.1 116.1l.6-.1v-.5l-.6-.1v1.3M97.4 116.1l.4 .6M98.3 116h.5M98.8 113.1v1l.2 .3 .4-.1 .1-.2v-1M98.9 115.4h-.6v1.3h.6M99.4 116.7h.7M99.4 115.8l.4-.4v1.3M100 114.4h.8M100 113.5l.4-.4v1.3M100.6 116.7h.8"/>
<path d="M100.6 115.8l.4-.4v1.3M101.8 116.7h.8M101.8 115.8l.4-.4v1.3M103 115.4h.8l-.4 .5 .3 .1v.6l-.2 .1-.5-.1M98.2 130.7a.58 .58 0 0 0-.8 .6 .58 .58 0 0 0 .8 .5v-.4h-.2M99.5 130.7v1.2l-.7-1.2v1.2M100.1 130.7a.64 .64 0 0 1 .7 .6 .64 .64 0 0 1-.7 .6zM101.3 130.8l.5-.1 .2 .3-.8 .9h.8"/>
</g>
<path d="M156.2 87.8h2.5v.5h-2.5z" fill-rule="evenodd" fill="#840000"/>
<path d="M187.9 69.8l7.7 3.8-7.7 3.8zM156.2 87.8h2.5v.5h-2.5zM177.7 105.6l1.5 1-1.5 1zM179.2 105.6v2" fill="none" stroke="#840000" stroke-width=".25"/>
<g fill="none" stroke="#840000" stroke-width=".21">
<path d="M157.5 77.4l-1.9 1.9M174.5 66.1h1.5v3.6h-1.5zM175.2 65.4v.7M175.2 69.7v.7M182.9 78.1v2M184.1 73.6h3.8M191.1 72.3v2.6h-1.9M191.7 72.3h-1.9v2.6M196.8 73.6h2.6M155.6 80.6l1.9 1.9M157.5 82.5h.1M157.5 86.3v1.5"/>
<path d="M182.9 81.1v2M175.9 106.6h5.1M177.9 107.9l.5 .5M178.2 108.4h.2M178.4 107.4l.5 .5M178.4 108.1v.3M178.7 107.9h.2M178.9 107.6v.3"/>
<circle cx="196.2" cy="73.6" r=".63"/>
</g>
<g fill="none" stroke="#006464" stroke-width=".21">
<path d="M176.8 67.9h.8l-.4 .4 .3 .2v.5l-.1 .1-.6-.1M176.9 66.6h.6l.1-.5-.7-.2v1.3M177.2 66.6l.5 .6M178.1 66.1l.5-.2 .3 .4-.8 .9h.8M178.3 67.9h.1a.68 .68 0 0 1 .4 .6 .68 .68 0 0 1-.4 .6 .84 .84 0 0 1-.1-1.2zM179.4 68l.2-.1a.68 .68 0 0 1 .4 .6 .68 .68 0 0 1-.4 .6l-.3-.5zM180.1 66.5l-.3 .2h-.3l-.1-.6 .4-.2 .3 .3-.1 .7-.2 .3h-.3M180.6 68.5h.6v-.5l-.6-.1v1.2M180.9 68.5l.4 .6M190.9 68.9h.8l-.5 1.2M192.4 68.8l-.3 .9h.8M192.7 76v1l.2 .2h.4l.1-.2v-1"/>
<path d="M192.7 69.3v.8M193.4 68.9v1.2h.6M194.3 68.9l.4 1.2 .4-1.2M194.7 76.5l-.3 .3-.3-.1-.1-.6 .4-.1 .3 .2-.1 .7-.2 .3h-.3M195.2 76h.4l.3 .2-.3 .4 .3 .1 .1 .3-.3 .2h-.5zM195.2 76.6h.4M196.2 69a.56 .56 0 0 0-.7 .5 .56 .56 0 0 0 .7 .5M196.7 70.1h.8M196.7 69.2l.4-.3v1.2M198.2 68.8l-.3 .9h.8M198.5 69.3v.8M155.9 89.5a.58 .58 0 0 0-.8 .6 .58 .58 0 0 0 .8 .5v-.4h-.2"/>
<path d="M157.2 89.4v1.3l-.7-1.3v1.3M157.8 89.4a.64 .64 0 0 1 .7 .7 .64 .64 0 0 1-.7 .6zM159.1 89.4a.64 .64 0 0 1 .7 .7 .64 .64 0 0 1-.7 .6zM185.8 83.7h.7M185.8 82.8l.3-.4v1.3M186.5 80a.56 .56 0 0 0-.8 .5 .56 .56 0 0 0 .8 .6M187 80l.5-.1 .3 .4-.8 .9h.8M187.1 82.6l.2-.2a.68 .68 0 0 1 .4 .7 .68 .68 0 0 1-.4 .6l-.3-.5zM188.2 81.2h.8M188.2 80.3l.4-.4v1.3M188.3 82.6l.2-.2a.68 .68 0 0 1 .4 .7 .68 .68 0 0 1-.4 .6l-.3-.5zM189.4 82.9v.8"/>
<path d="M189.4 83l.5-.1 .1 .8M176.6 104v1.3l-.7-1.3v1.3M177.2 104.6l.2-.2 .4 .2-.1 .6h-.5zM179.3 104.6h.5M179.9 104h-.6v1.3M180 107.8a.64 .64 0 0 1 .8 .7 .64 .64 0 0 1-.8 .6zM180.4 104v.1M180.4 104.4v.9M181 104v1.1l.2 .2M181.2 107.8h.8l-.5 .5 .4 .1v.6l-.2 .1-.5-.1M181.7 104.6l.3-.2 .2 .2M181.7 104.4v.9"/>
<path d="M182.2 104.6l.2-.2 .3 .1 .1 .8M182.2 104.6v.7M184.7 103.8a1.46 1.46 0 0 0 0 2M185.2 104.4v.9M185.6 104.4l-.4 .3M185.9 104.9l.6-.1v-.3l-.4-.1-.2 .2 .1 .6h.5M186.9 103.8a1.46 1.46 0 0 1 0 2"/>
</g>
<path d="M181.3 81.1h3.1" fill="none" stroke="#840000" stroke-width=".33"/>
<path d="M181.3 80.1h3.1" fill="none" stroke="#840000" stroke-width=".3"/>
<path d="M185.6 71.9h.8l-.4 .5 .3 .1v.6l-.1 .1-.6-.1M197.4 71.9l-.3 .9h.8M197.7 72.4v.8" fill="none" stroke="#a90000" stroke-width=".21"/>
<path d="M155.6 78.1v3.8" fill="none" stroke="#840000" stroke-width=".51"/>
<circle cx="155.6" cy="81.9" r=".25" fill="#840000"/>
<path d="M156.2 81.7l.5-.5 .5 1z" fill-rule="evenodd" fill="#840000"/>
<g fill="none" stroke="#840000" stroke-width=".21">
<path d="M149.9 80h5.7M149.9 73.6h.7M150.6 72.9h3.6v1.5h-3.6zM154.2 73.6h.7M156.7 68h1.5v3.6h-1.5zM157.5 67.3v.7M157.5 71.6v.7M157.5 74.9v2.5M160 73.6h3.8M167 72.3v2.6h-1.9M167.6 72.3h-1.9v2.6M172.7 73.6h2.5"/>
<path d="M175.2 75.5v2.6M175.2 60.9h5.1M176.5 73.6h.8M177.3 72.9h3.5v1.5h-3.5zM177.3 62.2l.5 .5M177.5 62.7h.3M177.8 61.7l.5 .5M177.8 62.4v.3M178 62.2h.3M178.3 61.9v.3M180.8 73.6h.8M156.2 81.7h.1"/>
<path d="M156.7 81.2l.5 1-1-.5zM157.5 82.5v2.5"/>
<circle cx="172.1" cy="73.6" r=".63"/>
<circle cx="175.2" cy="78.8" r=".76"/>
</g>
<g fill="none" stroke="#840000" stroke-width=".25">
<path d="M177 59.9l1.5 1-1.5 1zM178.5 59.9v2M163.8 69.8l7.6 3.8-7.6 3.8z"/>
<circle cx="156.2" cy="80" r="2.82"/>
</g>
<path d="M157.8 76.6v-.8l.5 .4 .1-.3h.5l.2 .1-.2 .6M161.6 73.2h.7M161.6 72.3l.3-.4v1.3M173 72.1l.5-.2 .2 .4-.8 .9h.8M152.4 81.5h.7M152.4 80.6l.3-.3v1.2M159.1 83.4v.8l-1-.8-.3 .3 .1 .4" fill="none" stroke="#a90000" stroke-width=".21"/>
<g fill="none" stroke="#006464" stroke-width=".21">
<path d="M177.2 58.4l-.7 .1v.3l.6 .3 .1 .3-.3 .2-.4-.1M177.7 58.9l.5-.1 .1 .8M177.7 58.3v1.3M178.9 58.8h.5v.8M179.4 59.1l-.6 .2 .2 .3 .4-.1M179.8 58.8h.5M180.3 58.3l-.3 .2v1.1M180.6 58.8h.5M180.7 58.3v1.1l.4 .2M182.8 58.2a1.46 1.46 0 0 0 0 1.9M183.3 58.8v.8M183.7 58.8l-.4 .2"/>
<path d="M184 59.2l.6-.1v-.3h-.4l-.2 .1 .1 .6h.5M185 58.2a1.46 1.46 0 0 1 0 1.9M150.5 75.4l-.3 .9h.8M150.8 75.9v.8M150.9 71.1l.6-.1v-.5l-.6-.1v1.3M151.2 71.1l.4 .6M151.3 75.5h.9l-.6 1.2M152.1 70.5l.5-.1 .2 .4-.8 .9h.8M152.7 75.6l.2-.1a.68 .68 0 0 1 .5 .6 .68 .68 0 0 1-.5 .6l-.3-.4zM153.4 70.5l.2-.1a.68 .68 0 0 1 .4 .6 .68 .68 0 0 1-.4 .7l-.3-.5zM153.9 75.5v1.2M154.1 76l.5 .7"/>
<path d="M154.6 75.5l-.7 .7M159.3 70.3h.8l-.5 .4 .4 .2v.5l-.2 .1-.5-.1M159.4 68.6h.6l.1-.5-.7-.1v1.2M159.7 68.6l.4 .6M160.3 78.2l.1-.1a.43 .43 0 0 1 .6 .4v.5a.42 .42 0 0 1-.4 .4 .42 .42 0 0 1-.5-.4zM160.4 79.1l.6 .4M160.6 70.3v1.2M160.6 68.1l.5-.1 .2 .3-.8 .9h.8M160.8 70.8l.5 .7M161.3 70.3l-.7 .7M161.8 68.1l.5-.1 .2 .3-.8 .9h.8M162.1 78.1h-.6v.6h.6v.6l-.1 .1-.5-.1"/>
<path d="M165.7 68.6h.9l-.6 1.3M167.3 68.6l-.3 .9h.8M167.4 76.5v1l.2 .3 .4-.1 .1-.2v-1M167.6 69v.9M168.3 68.6v1.3h.6M169.1 68.6l.4 1.3 .5-1.3M169.4 77l-.3 .3-.3-.1-.1-.6 .4-.1 .3 .2-.1 .7-.2 .3-.3 .1M169.7 77.8l.5-1.3 .4 1.3M169.9 77.4h.6M171.1 68.7a.56 .56 0 0 0-.8 .5 .56 .56 0 0 0 .8 .6M171.6 69.9h.7M171.6 69l.4-.4v1.3"/>
<path d="M173.1 68.6l-.3 .9h.8M173.4 69v.9M177.4 75.5h.8l-.4 .5 .3 .1v.5l-.2 .1-.5-.1M177.5 71.1l.6-.1 .1-.5-.7-.1v1.3M177.8 71.1l.4 .6M178.7 75.5v1.2M178.7 70.5l.5-.1 .2 .4-.7 .9h.7M178.9 76l.5 .7M179.4 62.1a.64 .64 0 0 1 .7 .7 .64 .64 0 0 1-.7 .6zM179.4 75.5l-.7 .7M179.9 75.5h.8l-.5 .5 .4 .1v.5l-.2 .1-.5-.1M180.2 70.3l-.3 .9h.8"/>
<path d="M180.5 70.8v.9M180.5 62.1h.9l-.6 1.3M160.9 80.5h-.7v.4l.5 .2 .2 .3-.3 .3-.5-.1M162.1 80.5h-.7v.4l.6 .2 .1 .3-.3 .3-.4-.1M162.8 81l-.2 .2v.4l.2 .1 .4-.1 .1-.2v-.2l-.3-.2M162.8 81l-.2-.3 .2-.3h.2l.3 .3-.3 .3M162.8 81h.2M163.9 80.5l.2-.1a.68 .68 0 0 1 .4 .7 .68 .68 0 0 1-.4 .6 .84 .84 0 0 1-.2-1.2zM165.6 80.4h-.6v.6h.6v.6l-.1 .1-.5-.1M166.4 80.5l.1-.1a.68 .68 0 0 1 .4 .7 .68 .68 0 0 1-.4 .6 .84 .84 0 0 1-.1-1.2zM172.5 80.5h.7M172.9 80.5v1.3"/>
<path d="M173.7 81.2l.6-.1v-.4l-.6-.2v1.3M174.9 81.8h.7M174.9 80.9l.3-.4v1.3M176.2 80.7l.2-.2a.68 .68 0 0 1 .4 .7 .68 .68 0 0 1-.4 .6l-.3-.5z"/>
</g>
<path d="M173.7 82.5l-.6 .1v.3l.5 .3 .1 .3-.2 .2h-.5M174.3 83l.5-.1v.8M174.3 82.4v1.3M175.4 82.9h.5l.1 .8M176 83.2l-.6 .2 .2 .3h.4M176.4 82.9h.5M176.9 82.4l-.3 .2v1.1M177.1 82.9h.5M177.3 82.4v1.1l.3 .2" fill="none" stroke="#840084" stroke-width=".21"/>
<path d="M183.5 63.7h2.5v.5h-2.5z" fill-rule="evenodd" fill="#840000"/>
<path d="M183.5 63.7h2.5v.5h-2.5z" fill="none" stroke="#840000" stroke-width=".25"/>
<path d="M184.8 62.2v1.5" fill="none" stroke="#840000" stroke-width=".21"/>
<path d="M183.2 65.4a.58 .58 0 0 0-.8 .6 .58 .58 0 0 0 .8 .5v-.5h-.2M184.5 65.3v1.3l-.7-1.3v1.3M185.1 65.3a.64 .64 0 0 1 .7 .6 .64 .64 0 0 1-.7 .7zM186.4 65.3a.64 .64 0 0 1 .7 .6 .64 .64 0 0 1-.7 .7z" fill="none" stroke="#006464" stroke-width=".21"/>
<path d="M184.1 109.4h2.6v.5h-2.6z" fill-rule="evenodd" fill="#840000"/>
<path d="M184.1 109.4h2.6v.5h-2.6z" fill="none" stroke="#840000" stroke-width=".25"/>
<path d="M175.1 111.8h1.5v3.6h-1.5zM175.9 111.1v.7M175.9 115.4v.7M185.4 107.9v1.5M156.2 126.3l1.9 1.9M158.1 128.2h.1M158.1 123.1l-1.9 1.9" fill="none" stroke="#840000" stroke-width=".21"/>
<g fill="none" stroke="#006464" stroke-width=".21">
<path d="M177.4 113.5h.8l-.4 .5 .4 .1v.6l-.2 .1-.6-.1M177.6 112.3l.6-.1v-.4l-.6-.2v1.3M177.9 112.3l.4 .6M178.8 112.9h.7M178.8 112l.3-.4v1.3M178.8 113.7l.2-.2a.68 .68 0 0 1 .5 .7 .68 .68 0 0 1-.5 .6l-.3-.5zM180 112.9h.7M180 112l.3-.4v1.3M180 113.7l.2-.2a.68 .68 0 0 1 .5 .7 .68 .68 0 0 1-.5 .6l-.3-.5zM181.2 114.2l.6-.1 .1-.4-.7-.2v1.3M181.5 114.2l.4 .6M183.8 111.1a.58 .58 0 0 0-.7 .6 .58 .58 0 0 0 .8 .5v-.5h-.3"/>
<path d="M185.1 111v1.3l-.7-1.3v1.3M185.7 111a.64 .64 0 0 1 .8 .6 .64 .64 0 0 1-.8 .7zM187 111a.64 .64 0 0 1 .7 .6 .64 .64 0 0 1-.7 .7z"/>
</g>
<path d="M156.2 123.8v3.8" fill="none" stroke="#840000" stroke-width=".51"/>
<circle cx="156.2" cy="127.6" r=".25" fill="#840000"/>
<path d="M156.8 127.4l.6-.5 .5 1z" fill-rule="evenodd" fill="#840000"/>
<path d="M150.5 125.7h5.7M156.8 127.4h.1M157.4 126.9l.5 1-1.1-.5zM158.1 120.6v2.5M158.1 128.2v2.5" fill="none" stroke="#840000" stroke-width=".21"/>
<circle cx="156.8" cy="125.7" r="2.82" fill="none" stroke="#840000" stroke-width=".25"/>
<path d="M153 127.2h.7M153 126.3l.4-.3v1.2M158.4 122.3v-.8l.5 .4 .1-.4h.6l.1 .2-.1 .6M159.7 129.1v.8l-.9-.8-.4 .2 .1 .5" fill="none" stroke="#a90000" stroke-width=".21"/>
<path d="M160.8 124l.3-.2a.43 .43 0 0 1 .5 .4v.4a.42 .42 0 0 1-.4 .5 .42 .42 0 0 1-.4-.5zM161 124.8l.7 .4M161.5 126.2h-.7v.4l.6 .2 .1 .3-.2 .3-.5-.1M162.7 123.8l-.4 .1-.1 .2-.1 .7 .2 .3 .5-.2-.1-.6h-.4l-.2 .2M162.7 126.2h-.7v.4l.6 .2 .1 .3-.2 .3-.5-.1M163.4 126.7l-.2 .2 .1 .4 .1 .1 .4-.1 .1-.2v-.2l-.2-.2M163.4 126.7l-.2-.3 .2-.3h.3l.2 .3-.2 .3M163.4 126.7h.3M164.5 126.2l.2-.1a.68 .68 0 0 1 .4 .6 .68 .68 0 0 1-.4 .7l-.3-.5zM166.3 126.1h-.6l-.1 .6h.6l.1 .6-.2 .1-.5-.1M166.9 126.2l.2-.1a.68 .68 0 0 1 .5 .6 .68 .68 0 0 1-.5 .7l-.3-.5z" fill="none" stroke="#006464" stroke-width=".21"/>
<path d="M156.8 133.5h2.6v.5h-2.6z" fill-rule="evenodd" fill="#840000"/>
<path d="M115 69.8h2.5v7.6h-2.5zM116.2 115.5h2.6v7.6h-2.6zM164.5 115.5l7.6 3.8-7.6 3.8zM188.6 115.5l7.6 3.8-7.6 3.8zM156.8 133.5h2.6v.5h-2.6z" fill="none" stroke="#840000" stroke-width=".25"/>
<g fill="none" stroke="#840000" stroke-width=".21">
<path d="M111.2 76.2h3.8M111.2 73.6h3.8M111.2 71.1h3.8M115 71h1.2v.2h-1.2zM115 73.5h1.2v.2h-1.2zM115 76h1.2v.3h-1.2zM138.4 68.5h5.1v10.2h-5.1zM143.5 76.2h2.6M143.5 73.6h2.6M143.5 71.1h2.6M112.4 119.3h3.8M112.4 116.8h3.8"/>
<path d="M116.2 116.6h1.3v.3h-1.3zM116.2 119.2h1.3v.2h-1.3zM139.1 114.2h5.1v10.2h-5.1zM144.2 119.3h2.5M144.2 116.8h2.5M150.5 119.3h.8M151.3 118.6h3.5v1.5h-3.5zM154.8 119.3h.8M157.4 113.7h1.5v3.6h-1.5zM158.1 113v.7M158.1 117.3v.7M160.7 119.3h3.8"/>
<path d="M167.6 118v2.6h-1.9M168.3 118h-1.9v2.6M173.3 119.3h2.6M177.2 119.3h.7M177.9 118.6h3.6v1.5h-3.6zM181.5 119.3h.7M184.8 119.3h3.8M191.7 118v2.6h-1.9M192.4 118h-1.9v2.6M197.5 119.3h2.5M112.4 121.9h3.8M116.2 121.7h1.3v.3h-1.3z"/>
<path d="M144.2 121.9h2.5M158.1 132v1.5M175.9 121.2v2.6M183.5 123.1v2.1M183.5 126.2v2"/>
<circle cx="142.2" cy="77.4" r=".38"/>
<circle cx="172.7" cy="119.3" r=".63"/>
<circle cx="196.8" cy="119.3" r=".63"/>
<circle cx="142.9" cy="123.1" r=".38"/>
<circle cx="175.9" cy="124.5" r=".76"/>
</g>
<g fill="none" stroke="#006464" stroke-width=".21">
<path d="M112.8 78.6h.5M113.4 78h-.6v1.3M113.9 78v.1M113.9 78.4v.9M114.5 78v1.1l.2 .2M115.2 78.4v.9M115.2 78.5l.4-.1 .1 .2M115.7 78.6l.2-.2 .3 .1 .1 .8M115.7 78.6v.7M116.4 67.2l-.1 1.1-.4 .2M116.9 67.2h.7l-.4 .5 .4 .1v.6l-.2 .1-.5-.1M117.8 78.6h.5"/>
<path d="M118.5 78h-.7v1.3h.7M119 78.5h.5v.8M119 78.4v.9M120.7 78.5l-.4-.1-.2 .3 .1 .5h.5M120.7 78v1.3M122.3 78.6h.4M122.9 78h-.6v1.3h.6M123.3 78.4l.3 .9M123.6 79.3l-.3 .4M123.9 78.4l-.3 .9M124.3 78.9l.6-.2v-.2l-.4-.1-.2 .2 .1 .6h.5M140 79.4a.56 .56 0 0 0-.8 .5 .56 .56 0 0 0 .8 .5"/>
<path d="M141.3 79.3v1.2l-.8-1.2v1.2M141.9 70.4h.8l-.5 .5 .4 .1v.5l-.2 .2-.5-.2M141.9 76.7h.8M141.9 75.8l.4-.3v1.2M141.9 73l.5-.1 .3 .4-.8 .9h.8M142.4 79.3h-.4l-.1 .3-.1 .7 .2 .2 .5-.1-.1-.6h-.4l-.2 .2M134.6 81.9h-.7v.4l.6 .2 .1 .3-.2 .3-.5-.1M135.2 82.4l.4-.1 .1 .8M135.2 81.8v1.3M136.3 82.3h.5v.8M136.8 82.5l-.6 .3 .2 .3 .4-.1M137.3 82.2h.5"/>
<path d="M137.8 81.8l-.3 .2v1.1M138 82.2h.5M138.2 81.8v1.1l.3 .2M139.9 82.4h.4M140.5 81.8h-.6v1.3h.6M140.9 82.2l.3 .9M141.2 83.1l-.3 .4M141.5 82.2l-.3 .9M141.9 82.7l.6-.2v-.2l-.4-.1-.2 .2 .1 .6h.5M117.6 112.9v1.1l-.4 .2M118.2 113l.5-.1 .2 .4-.8 .9h.8M142.5 116.1h.8l-.4 .5 .3 .1v.5l-.1 .2-.6-.2"/>
<path d="M142.6 118.7l.5-.1 .2 .4-.8 .9h.8M151.5 116.7h.6l.1-.5-.7-.1v1.3M151.8 116.7l.4 .7M152.6 116.1h.8l-.4 .5 .4 .1v.5l-.2 .2-.6-.2M153.9 117.4h.7M153.9 116.4l.4-.3v1.3M159.9 116h.8l-.4 .4 .3 .2v.5l-.2 .1-.5-.1M160 114.3h.6l.1-.5-.7-.2v1.3M160.3 114.3l.5 .6M161.2 113.6h.8l-.5 .5 .4 .2v.5l-.2 .1-.5-.1M161.2 116v1.2M161.4 116.5l.6 .7"/>
<path d="M162 116l-.8 .7M162.6 113.8l.1-.2a.68 .68 0 0 1 .5 .7 .68 .68 0 0 1-.5 .6l-.3-.5zM166.9 114.2h.8l-.5 1.2M168.4 114.1l-.3 .9h.8M168.8 114.6v.8M169.4 114.2v1.2h.6M170.3 114.2l.4 1.2 .4-1.2M172.3 114.3a.56 .56 0 0 0-.8 .5 .56 .56 0 0 0 .8 .5M172.7 115.4h.8M172.7 114.5l.4-.3v1.2M174.3 114.1l-.4 .9h.8M174.6 114.6v.8"/>
<path d="M178.2 116.7h.6v-.5l-.6-.1v1.3M178.5 116.7l.4 .7M179.4 116.2l.4-.1 .3 .3-.8 1h.8M180.5 116.1h.9l-.6 1.3M191.6 114.8h.9l-.6 1.3M193.2 114.8l-.3 .9h.8M193.5 115.2v.9M194.2 114.8v1.3h.6M195 114.8l.4 1.3 .5-1.3M197 114.9a.56 .56 0 0 0-.8 .5 .56 .56 0 0 0 .8 .6M197.5 116.1h.7M197.5 115.2l.4-.4v1.3"/>
<path d="M199 114.8l-.3 .9h.8M199.3 115.2v.9M115.4 124.4l-.7 .1v.3l.6 .3 .1 .3-.2 .2-.5-.1M115.9 124.9l.5-.1 .1 .8M115.9 124.3v1.3M117.1 124.8h.5v.8M117.6 125.1l-.6 .2 .2 .3 .4-.1M118.1 124.8h.4M118.5 124.3l-.3 .2v1.1M118.8 124.8h.5M119 124.3v1.1l.3 .2M120.7 124.9h.4"/>
<path d="M121.3 124.3h-.6v1.3h.6M121.7 124.8l.3 .8M122 125.6l-.3 .4M122.3 124.8l-.3 .8M122.7 125.2l.6-.1v-.3h-.4l-.2 .1 .1 .6h.5M131.7 128.1h.4M132.3 127.5h-.6v1.3M132.8 127.5v.1M132.8 127.9v.9M133.4 127.5v1.1l.2 .2M134.1 128.1l.3-.2 .2 .2M134.1 127.9v.9"/>
<path d="M134.6 128.1l.2-.2 .3 .1 .1 .8M134.6 128.1v.7M136.7 128.1h.5M137.3 127.5h-.6v1.3h.6M137.9 128.1l.5-.1v.8M137.9 127.9v.9M139.6 128l-.4-.1-.2 .3 .1 .5h.5M139.6 127.5v1.3M140 125.1a.56 .56 0 0 0-.8 .5 .56 .56 0 0 0 .8 .5M141.1 128.1h.5M141.3 125v1.2l-.8-1.2v1.2M141.7 127.5h-.6v1.3h.6"/>
<path d="M142.2 127.9l.3 .9M142.5 125h-.6l-.1 .6 .6-.1 .1 .6-.2 .1-.5-.1M142.5 128.8l-.3 .4M142.6 122.4h.7M142.6 121.5l.3-.3v1.2M142.8 127.9l-.3 .9M143.2 128.4l.6-.2-.1-.2-.3-.1-.2 .2 .1 .6h.4M151.1 121.1l-.3 .9h.8M151.4 121.6v.8M152 121.2h.8l-.5 1.2M153.4 121.2h.2a.68 .68 0 0 1 .4 .6 .68 .68 0 0 1-.4 .6 .84 .84 0 0 1-.2-1.2zM154.5 121.2v1.2"/>
<path d="M154.7 121.7l.5 .7M155.2 121.2l-.7 .7M156.5 135.2a.58 .58 0 0 0-.7 .6 .58 .58 0 0 0 .8 .5v-.5h-.3M157.8 135.1v1.3l-.7-1.3v1.3M158.4 135.1a.64 .64 0 0 1 .8 .7 .64 .64 0 0 1-.8 .6zM159.7 135.1a.64 .64 0 0 1 .7 .7 .64 .64 0 0 1-.7 .6zM167.9 121.8v1l.3 .3 .3-.1 .2-.2v-1M169.9 122.3l-.2 .3-.4-.1v-.6l.4-.1 .2 .2v.8l-.2 .2-.4 .1M171.2 121.9a.56 .56 0 0 0-.8 .5 .56 .56 0 0 0 .8 .5M174.4 125.6h.7M174.7 125.6v1.3M175.5 126.3l.6-.1 .1-.5-.7-.1v1.3"/>
<path d="M176.6 125.6h.8l-.4 .5 .4 .1v.6l-.2 .1-.6-.1M178 121.2h.8l-.4 .4 .4 .2v.5l-.2 .1-.6-.1M179.4 121.2v1.2M179.5 121.7l.6 .7M180.1 121.2l-.7 .7M180.5 121.2h.8l-.4 .4 .3 .2v.5l-.1 .1-.6-.1M186.4 128.8h.7M186.4 127.9l.4-.4v1.3M187.2 125.1a.56 .56 0 0 0-.8 .5 .56 .56 0 0 0 .8 .5M187.7 125.1l.4-.1 .3 .3-.8 .9h.8M187.7 127.6l.2-.1a.68 .68 0 0 1 .4 .6 .68 .68 0 0 1-.4 .7l-.3-.5zM188.9 125.1l.5-.1 .2 .3-.8 .9h.8"/>
<path d="M188.9 127.6l.2-.1a.68 .68 0 0 1 .5 .6 .68 .68 0 0 1-.5 .7l-.3-.5zM190.1 127.9v.9M190.1 128.1l.5-.1v.8M192.7 121.8v1l.2 .3 .4-.1 .1-.2v-1M194.7 122.3l-.3 .3-.3-.1-.1-.6 .4-.1 .3 .2-.1 .8-.2 .2-.3 .1M195.2 121.8a.64 .64 0 0 1 .8 .6 .64 .64 0 0 1-.8 .7z"/>
</g>
<path d="M172.5 127.5v1.3l-.7-1.3v1.3M173.1 128.1l.2-.2 .4 .2-.1 .6h-.5zM175.2 128.1h.5M175.9 127.5h-.7v1.3M176.3 127.5v.1M176.3 127.9v.9M176.9 127.5v1.1l.2 .2M177.6 128.1l.4-.2 .2 .2M177.6 127.9v.9M178.2 128.1l.1-.2 .3 .1 .1 .8M178.2 128.1v.7" fill="none" stroke="#840084" stroke-width=".21"/>
<g fill="none" stroke="#a90000" stroke-width=".21">
<path d="M112.6 69.4h.8l-.4 .5 .4 .1v.5l-.2 .2-.6-.2M112.7 75.7h.7M112.7 74.8l.4-.3v1.2M112.7 72.1l.5-.2 .2 .4-.8 .9h.8M144.4 69.4h.7l-.4 .5 .4 .1v.5l-.2 .2-.5-.2M144.4 75.7h.7M144.4 72.1l.5-.2 .2 .4-.7 .9h.7M144.4 74.8l.4-.3v1.2M113.9 115.1h.8l-.4 .5 .3 .1v.5l-.2 .2-.5-.2M114 117.7l.4-.1 .3 .4-.8 .9h.8M145 115.1h.8l-.4 .5 .3 .1v.5l-.2 .2-.5-.2M145.1 117.7l.4-.1 .3 .4-.8 .9h.8"/>
<path d="M162.9 117.6h-.6l-.1 .6h.6l.1 .6-.2 .1-.5-.1M174.2 117.6l-.3 .1-.2 .2-.1 .8 .3 .2 .4-.1-.1-.6-.3-.1-.3 .3M187 118.2l-.2 .2h-.4v-.7l.4-.1 .2 .3v.7l-.2 .2-.4 .1M198 118.2l-.3-.3 .3-.3h.2l.3 .3-.3 .3M198 118.2l-.3 .2 .1 .4 .2 .1 .3-.1 .2-.1v-.3l-.3-.2M198 118.2h.2M114 121.4h.7M114 120.5l.3-.3v1.2M145.1 121.4h.7M145.1 120.5l.3-.3v1.2"/>
</g>
<path d="M182 126.2h3" fill="none" stroke="#840000" stroke-width=".33"/>
<path d="M182 125.2h3" fill="none" stroke="#840000" stroke-width=".3"/>
<g fill="#009600">
<circle cx="106.1" cy="78.7" r=".46"/>
<circle cx="50.9" cy="81.2" r=".46"/>
<circle cx="98.5" cy="81.2" r=".46"/>
<circle cx="107.3" cy="124.4" r=".46"/>
<circle cx="99.7" cy="126.9" r=".46"/>
<circle cx="157.5" cy="85" r=".46"/>
<circle cx="182.9" cy="73.6" r=".46"/>
<circle cx="175.2" cy="73.6" r=".46"/>
<circle cx="158.1" cy="130.7" r=".46"/>
<circle cx="158.1" cy="111.7" r=".46"/>
<circle cx="149.2" cy="119.3" r=".46"/>
<circle cx="158.1" cy="119.3" r=".46"/>
<circle cx="183.5" cy="119.3" r=".46"/>
<circle cx="175.9" cy="119.3" r=".46"/>
<circle cx="106.1" cy="73.6" r=".46"/>
<circle cx="157.5" cy="73.6" r=".46"/>
<circle cx="157.5" cy="66" r=".46"/>
<circle cx="148.6" cy="73.6" r=".46"/>
<circle cx="106.1" cy="63.5" r=".46"/>
<circle cx="107.3" cy="109.2" r=".46"/>
<circle cx="107.3" cy="119.3" r=".46"/>
</g>
</svg>
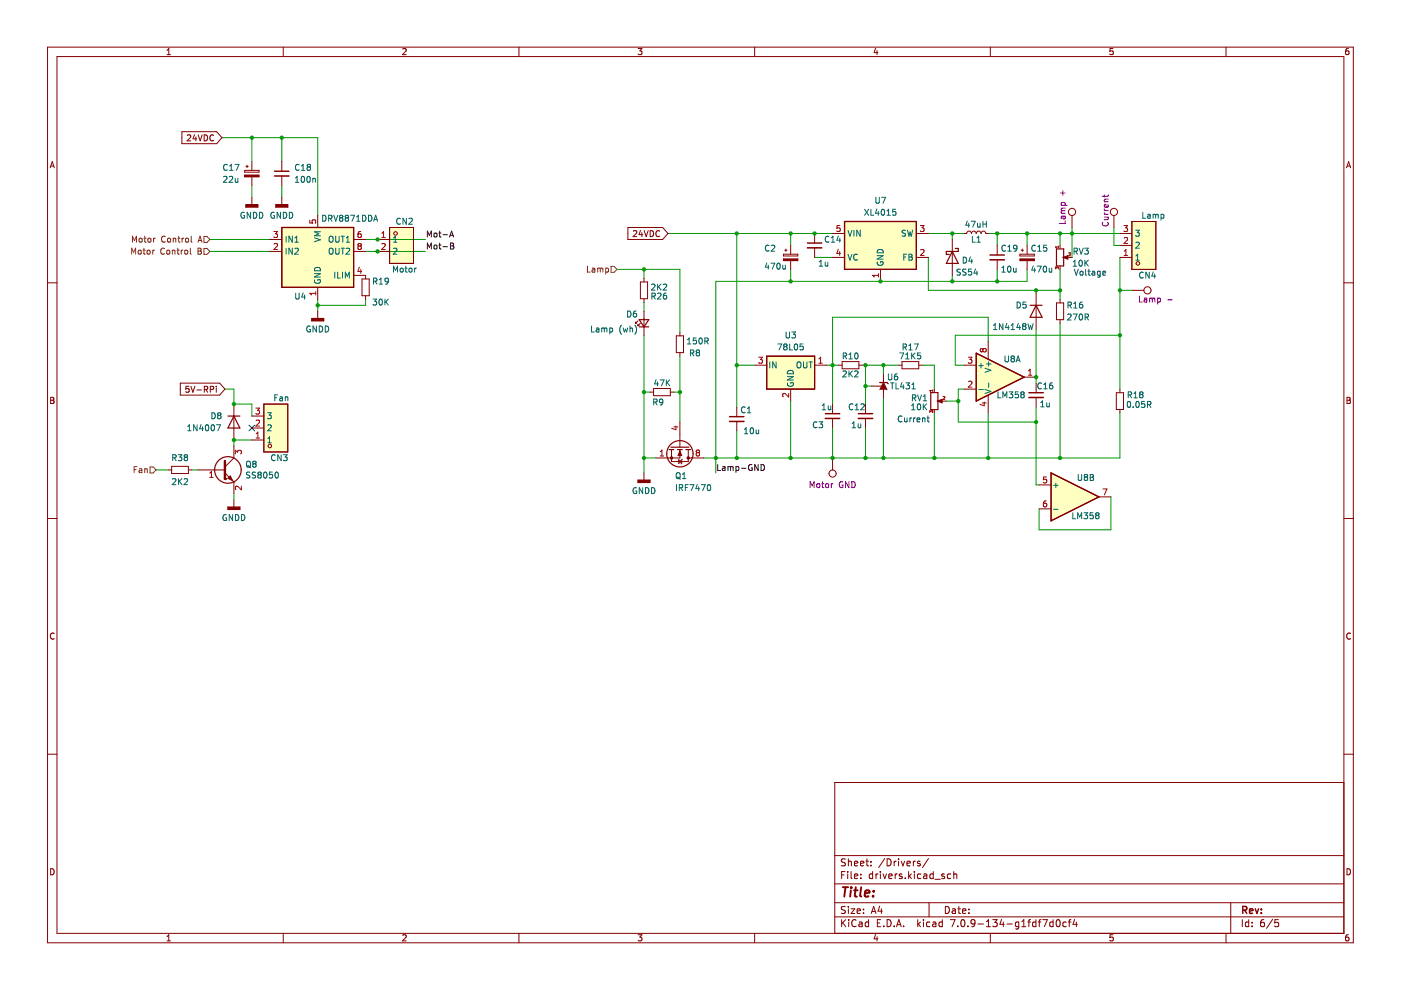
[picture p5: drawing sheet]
<svg xmlns="http://www.w3.org/2000/svg" width="297mm" height="210mm" viewBox="0 0 297 210" stroke-linecap="round" stroke-linejoin="round" font-family="sans-serif">
<g fill="none" stroke="#840000" stroke-width=".21">
<path d="M10.1 10h276.8v189.9h-276.8zM12.1 12h272.8v185.9h-272.8zM35.4 11.6h.8M35.4 10.7l.4-.4v1.3M60.1 10v2M85.4 10.4l.5-.1 .2 .4-.8 .9h.8M110 10v2M135.3 10.3h.8l-.4 .5 .3 .1v.6l-.1 .1-.6-.1M160 10v2M185.6 10.2l-.3 1h.8M185.9 10.7v.9M210 10v2"/>
<path d="M236 10.3h-.6l-.1 .6 .6-.1 .1 .7-.2 .1-.5-.1M259.9 10v2M285.9 10.3h-.4l-.2 .3v.7l.2 .3 .5-.1-.1-.7h-.4l-.2 .2M10.6 35.6l.5-1.3 .4 1.3M10.8 35.2h.6M285.5 35.6l.4-1.3 .5 1.3M285.6 35.2h.6M10.1 60h2M284.9 60h2M10.7 84.2h.5l.2 .3-.2 .4 .2 .1 .1 .3-.3 .2h-.5zM10.7 84.9h.5M285.6 84.2h.4l.3 .3-.3 .4 .3 .1v.3l-.2 .2h-.5z"/>
<path d="M285.6 84.9h.4M10.1 109.9h2M284.9 109.9h2M11.5 134.3a.58 .58 0 0 0-.8 .6 .58 .58 0 0 0 .8 .5M286.3 134.3a.58 .58 0 0 0-.8 .6 .58 .58 0 0 0 .8 .5M10.1 159.9h2M284.9 159.9h2M284.9 165.9h-107.9v32M10.7 184.2a.66 .66 0 0 1 .8 .6 .66 .66 0 0 1-.8 .7zM35.4 198.6l.4-.4v1.3M35.4 199.5h.8M60.1 197.9v2"/>
<path d="M85.4 198.3l.5-.1 .2 .4-.8 .9h.8M110 197.9v2M135.3 198.2h.8l-.4 .5 .3 .1v.6l-.1 .1-.6-.1M160 197.9v2M177 194.4h107.9M177 191.4h107.9M177 187.4h107.9M177 181.4h107.9M178.4 195v1.5M178.4 185.5h.5M178.7 195.6l.6 .9M179.2 184.8h-.8v1.5"/>
<path d="M179.2 192.3l-.5-.1-.3 .1v.5l.7 .2 .1 .4-.3 .3-.5-.1M179.2 182.2l-.5-.1-.3 .1v.5l.7 .2 .1 .4-.3 .3-.5-.1M179.3 195l-.9 .8M179.7 184.8v.1M179.7 185.3v1M179.9 182.1v1.5M179.9 192.2v.1M179.9 192.7v1M179.9 182.7l.2-.1 .3 .1 .1 .9M179.9 195v.1M179.9 195.5v1M180.4 192.7h.8l-.8 1h.8"/>
<path d="M180.4 184.8v1.3l.3 .2M181.2 185.8l.7-.2-.1-.2-.4-.1-.2 .2v.7h.6M181.2 183.1l.7-.2-.1-.2-.4-.1-.2 .2v.7h.6M181.5 195.1a.71 .71 0 0 0-1 .5 .71 .71 0 0 0 .7 .9l.3-.2M181.7 193.2l.7-.2v-.2l-.5-.1-.2 .2 .1 .7h.6M182.2 195.6h.5l.1 .9M182.4 183.1l.8-.2-.1-.2-.4-.1-.3 .2 .1 .7h.6M182.5 186.1v.2M182.5 185.4v.1M182.8 195.8l-.5 .1-.2 .2 .2 .4 .5-.1M183.1 193.5v.2M183.1 192.8v.1"/>
<path d="M183.6 182.6h.6M183.8 182.1v1.3l.4 .2M184.2 195.6l-.5-.1-.3 .3 .2 .6h.6M184.2 195v1.5M184.7 183.4v.2M184.7 182.7v.1M184.7 193.7l.5-1.5 .5 1.5M184.9 193.3h.7M185 185.4l-.4-.1-.3 .3 .1 .6h.6M185 184.8v1.5M185.6 198.1l-.3 1h.8M185.7 185.3v1"/>
<path d="M185.9 198.6v.9M186 195.7h.5M186.2 185.3l-.5 .3M186.5 192.1l-.3 1.1h.9M186.7 184.8v.1M186.7 185.3v1M186.7 195h-.7v1.5h.7M186.9 192.7v1M187.2 185.3l.4 1 .3-1M187.4 196.3v.2M187.6 182l-1.3 1.9M188.1 195a.76 .76 0 0 1 .8 .7 .76 .76 0 0 1-.8 .8z"/>
<path d="M188.1 182.1a.76 .76 0 0 1 .8 .7 .76 .76 0 0 1-.8 .8zM188.4 185.8l.8-.2-.1-.2-.4-.1-.3 .2 .1 .7h.6M189.6 196.3v.2M189.6 182.6v1M189.8 185.3v1M190 182.6l-.4 .3M190.1 196.5l.5-1.5 .5 1.5M190.2 196.1h.7M190.2 185.3l-.4 .3M190.5 182.1v.1M190.5 182.6v1M191.1 182.6l.3 1 .4-1"/>
<path d="M191.2 185.4l-.3-.1-.2 .2v.2l.5 .2v.3h-.5M191.6 196.3v.2M191.9 186.1v.2M192.3 183.1l.7-.2-.1-.2-.4-.1-.2 .2 .1 .7h.5M192.7 184.8v1.5M192.8 185.7l.4 .6M193.2 185.3l-.5 .6M193.7 182.6v1M193.9 184.8v.1M193.9 185.3v1M194.1 182.6l-.4 .3M194.6 195v1.5"/>
<path d="M194.7 195.9l.5 .6M195.1 182.7l-.4-.1-.2 .2 .1 .2 .5 .2v.3h-.6M195.2 195.5l-.6 .6M195.2 185.4l-.4-.1-.3 .3 .2 .6h.5M195.8 195v.1M195.8 195.5v1M195.9 185.4h.5l.1 .9M196.5 185.6l-.5 .1-.2 .2 .2 .4 .5-.1M196.9 182l-1.3 1.9M197 191.4v3M197.1 195.6l-.4-.1-.3 .3 .2 .6h.5M197.8 195.6h.6v.9"/>
<path d="M197.9 185.4l-.5-.1-.3 .3 .2 .6h.6M197.9 184.8v1.5M198.2 186.4h1.2M198.4 195.8l-.5 .1-.2 .2 .2 .4 .5-.1M199.8 195.6l-.4-.1-.3 .3 .1 .6h.6M199.8 195v1.5M200.2 185.4l-.3-.1-.3 .2 .1 .2 .5 .2v.3h-.6M200.4 192.2a.76 .76 0 0 1 .9 .7 .76 .76 0 0 1-.9 .8zM201.5 195h1l-.6 1.5M201.6 185.4l-.5-.1-.2 .3 .1 .6h.6M201.9 192.8h.6l.1 .9M202.2 185.4l.2-.1 .4 .1 .1 .9"/>
<path d="M202.2 184.8v1.5M202.6 193l-.5 .1-.2 .2 .2 .4 .5-.1M203.1 192.7h.5M203.1 196.3v.2M203.3 192.2v1.3l.3 .2M203.9 195.1l.2-.1a.8 .8 0 0 1 .5 .7 .8 .8 0 0 1-.5 .8l-.4-.6zM204.1 193.2l.7-.2-.1-.2-.4-.1-.2 .2v.7h.6M205.2 196.3v.2M205.4 193.5v.2M205.4 192.8v.1M206.7 195.6l-.3 .3h-.3l-.2-.3v-.3l.2-.3 .5 .1 .1 .2a1 1 0 0 1-.4 1.2h-.3M207.4 195.9h1.1"/>
<path d="M209.1 196.5h.9M209.1 195.4l.5-.4v1.5M210 197.9v2M210.5 195h.9l-.5 .6 .5 .1v.6l-.3 .2-.6-.2M212.4 194.9l-.4 1.1h.9M212.7 195.5v1M213.5 195.9h1.1M216 195.6l-.4-.1-.3 .3 .1 .6h.6M216 195.5v1.2l-.3 .3-.3-.1M216.6 196.5h.9M216.6 195.4l.5-.4v1.5M217.9 195.5h.6"/>
<path d="M218.5 195l-.4 .2v1.3M219.6 195.6l-.4-.1-.3 .3 .2 .6h.5M219.6 195v1.5M220.1 195.5h.6M220.7 195l-.3 .2v1.3M221.1 195h1l-.7 1.5M223.3 195.6l-.5-.1-.2 .3 .1 .6h.6M223.3 195v1.5M224.1 195.1l.2-.1a.8 .8 0 0 1 .5 .7 .8 .8 0 0 1-.5 .8l-.4-.6zM226.1 195.6l-.5-.1-.3 .3 .2 .6h.6M226.5 195.5h.6M227.1 195l-.4 .2v1.3"/>
<path d="M227.8 194.9l-.3 1.1h.9M228.2 195.5v1M236 198.2h-.6l-.1 .6 .6-.1 .1 .7-.2 .1-.5-.1M259.9 197.9v2M260.9 191.4v6.5M263.4 195v1.5M264.8 195.6l-.5-.1-.3 .3 .2 .6h.6M264.8 195v1.5M265.5 196.3v.2M265.5 195.6v.1M268 195l-.5 .1a1.01 1.01 0 0 0 0 1.4l.5-.2 .1-.5-.3-.2h-.4l-.1 .2M269.8 194.9l-1.3 1.9"/>
<path d="M271 195h-.7v.7l.2-.1h.5l.1 .2-.1 .5-.2 .2-.5-.2M285.6 184.2a.66 .66 0 0 1 .7 .6 .66 .66 0 0 1-.7 .7zM285.9 198.2l-.4 .1-.2 .2v.7l.2 .3 .5-.1-.1-.7h-.4l-.2 .2"/>
</g>
<path d="M263.5 193l.7-.1 .2-.2-.1-.4-.8-.1v1.5M263.9 193l.5 .7M264.9 193.2l.7-.2v-.3h-.5l-.2 .2 .1 .7h.6M266.1 192.7l.4 1 .4-1M267.4 193.5v.2M267.4 192.7v.2" fill="none" stroke="#840000" stroke-width=".3"/>
<path d="M178.7 188.1h1.1M179.3 188.1l-.3 2M180.4 188.8l-.2 1.3M180.5 188.1v.2M181.1 188.8h.7M181.4 188.1l-.2 1.7 .1 .2 .4 .1M182.6 188.1l-.2 1.7 .2 .3M183.4 189.4l.9-.2v-.3h-.8l-.2 .9 .3 .3 .6-.1M185.1 189.9v.2M185.2 188.9v.2" fill="none" stroke="#840000" stroke-width=".4"/>
<path d="M162.6 75.5h10.1v7h-10.1z" fill-rule="evenodd" fill="#ffffc2"/>
<path d="M162.6 75.5h10.1v7h-10.1z" fill="none" stroke="#840000" stroke-width=".25"/>
<path d="M207 74.9l10.1 5.1-10.1 5z" fill="#ffffc2"/>
<path d="M207 74.9l10.1 5.1-10.1 5z" fill="none" stroke="#840000" stroke-width=".25"/>
<path d="M222.8 100.3l10.2 5.1-10.2 5z" fill="#ffffc2"/>
<path d="M222.8 100.3l10.2 5.1-10.2 5z" fill="none" stroke="#840000" stroke-width=".25"/>
<path d="M82.6 48.2h5.1v7.6h-5.1z" fill-rule="evenodd" fill="#ffffc2"/>
<path d="M82.6 48.2h5.1v7.6h-5.1z" fill="none" stroke="#840000" stroke-width=".21"/>
<path d="M59.7 48.2h15.3v12.7h-15.3z" fill-rule="evenodd" fill="#ffffc2"/>
<path d="M59.7 48.2h15.3v12.7h-15.3z" fill="none" stroke="#840000" stroke-width=".25"/>
<path d="M179.1 47h15.2v10.1h-15.2z" fill-rule="evenodd" fill="#ffffc2"/>
<path d="M179.1 47h15.2v10.1h-15.2z" fill="none" stroke="#840000" stroke-width=".25"/>
<path d="M240 47h5.1v10.1h-5.1z" fill-rule="evenodd" fill="#ffffc2"/>
<path d="M240 47h5.1v10.1h-5.1z" fill="none" stroke="#840000" stroke-width=".21"/>
<path d="M55.9 85.7h5.1v10.1h-5.1z" fill-rule="evenodd" fill="#ffffc2"/>
<g fill="none" stroke="#840000" stroke-width=".21">
<path d="M38.6 27.9h7.3l1.2 1.3-1.2 1.3h-7.3zM39.7 28.7l.5-.1 .2 .4-.7 .9h.7M41.2 28.5l-.3 .9h.8M41.5 29v.9M42 28.6l.4 1.3 .5-1.3M43.3 28.6a.64 .64 0 0 1 .7 .6 .64 .64 0 0 1-.7 .7zM45.3 28.7a.56 .56 0 0 0-.8 .5 .56 .56 0 0 0 .8 .5M133.1 48.2h7.4l1.1 1.3-1.1 1.3h-7.4zM134.3 49l.5-.1 .2 .4-.8 .9h.8M135.8 48.8l-.3 .9h.8M136.1 49.3v.9M136.6 48.9l.4 1.3 .4-1.3"/>
<path d="M137.8 48.9a.64 .64 0 0 1 .8 .6 .64 .64 0 0 1-.8 .7zM139.8 49a.56 .56 0 0 0-.7 .5 .56 .56 0 0 0 .7 .6M38.2 81.2h8.4l1.1 1.3-1.1 1.3h-8.4zM40.1 81.9h-.7v.6l.6-.1 .1 .7-.2 .1-.5-.1M40.5 81.9l.4 1.3 .4-1.3M41.7 82.7h1M43.3 82.6l.6-.1 .1-.5-.7-.1v1.3M43.6 82.6l.4 .6M44.6 82.6l.6-.1 .1-.5-.7-.1v1.3M45.9 81.9v.1M45.9 82.3v.9M55.9 85.7h5.1v10.1h-5.1z"/>
<path d="M176.5 85.7v2M176.5 88.7v2.1M187.3 80.6v2.5"/>
</g>
<path d="M52.8 90.1l1.2 1.3M54 90.1l-1.2 1.3" fill="none" stroke="#000084" stroke-width=".21"/>
<g fill="none" stroke="#009600" stroke-width=".21">
<path d="M47.1 29.2h20.3v16.5M53.4 29.2v5.1M53.4 39.3v2.6M59.7 29.2v5.1M59.7 39.3v2.6M44.5 50.8h12.7M44.5 53.3h12.7M77.5 50.8h12.7M77.5 53.3h12.7M130.8 57.1h13.4v13.3M136.5 57.1v1.9M141.6 49.5h34.9"/>
<path d="M156.2 49.5v36.8M167.6 49.5v2.5M167.6 57.1v2.6M172.7 54.6h3.8M196.8 49.5h7.6M196.8 54.6v7h28M201.9 49.5v1.3M201.9 58.4v1.3M209.5 49.5h27.9M211.4 49.5v2.5M211.4 57.1v2.6M217.8 57.1v2.6h-66v40.6"/>
<path d="M217.8 49.5v2.5M224.8 49.5v2.5M224.8 57.1v6.4M227.3 48.2v6.4M236.2 48.2v3.8h1.2M237.4 54.6v27.9M67.4 63.5v2.5M77.5 63.5v1.2h-10.1M136.5 64.1v1.9M136.5 71.1v29.2M144.2 75.5v14M156.2 77.4h3.8"/>
<path d="M175.2 77.4h2.6M182.9 77.4h7.6M183.5 77.4v8.3M187.3 77.4v1.9M195.6 77.4h2.5v5.1M209.5 72.3v-5h-33v18.4M219.7 61.6v.6M219.7 69.8v11.4M224.8 68.5v28.6M237.4 71.1h-34.9v6.3h1.9M237.4 61.6h2.6M33.1 99.6h2.5"/>
<path d="M40.7 99.6h1.3M47.7 82.5h1.9v3.2h3.8v2.5M53.4 93.3h-3.8v1.3M136.5 97.1h2.6M136.5 83.1h1.3M142.9 83.1h1.3M156.2 91.4v5.7M167.6 85v12.1M176.5 90.8v6.3M183.5 81.9h1.3M183.5 90.8v6.3M187.3 84.4v12.7"/>
<path d="M198.1 87.6v9.5M200.6 85h2.6M204.4 82.5h-1.2v7h16.5M209.5 87.6v9.5M219.7 86.3v16.5h.6M237.4 87.6v9.5h-88.2M49.6 104.7v1.3M235.5 105.4v6.9h-15.2v-4.4"/>
</g>
<g fill="none" stroke="#0000c2" stroke-width=".21">
<path d="M227.8 57.1l.4 1.3 .4-1.3M229 57.6l.2-.1 .4 .1-.1 .7-.5-.1zM230.2 57.1v1.1l.2 .2M230.7 57.5h.4M230.8 57.1v1.1l.3 .2M231.6 57.6h.5v.8M232.1 57.8l-.6 .3 .2 .3 .4-.1M233.3 57.6l-.4-.1-.2 .3 .1 .5h.5M233.3 57.5v1l-.3 .3-.3-.1M233.8 57.9l.6-.1v-.2l-.4-.1-.2 .2 .1 .6h.5M191.2 88.3a.56 .56 0 0 0-.8 .5 .56 .56 0 0 0 .8 .5M191.8 88.6v.8l.5-.1"/>
<path d="M192.3 88.6v.9M192.9 88.6v.9M193.3 88.6l-.4 .2M193.7 88.6v.9M194.1 88.6l-.4 .2M194.4 89l.6-.1v-.2l-.4-.1-.2 .2 .1 .6h.5M195.6 88.7h.5v.8M195.6 88.6v.9M196.5 88.6h.5M196.7 88.2v1.1l.3 .2"/>
</g>
<g fill="none" stroke="#0f0f0f" stroke-width=".21">
<path d="M90.6 50.3v-1.3l.4 .9 .5-.9v1.3M90.6 52.8v-1.3l.4 .9 .5-.9v1.3M92.1 52.1l.1-.1 .4 .1-.1 .6h-.4zM92.1 49.5l.1-.1 .4 .1-.1 .7-.4-.1zM93 52h.5M93 49.4h.5M93.2 51.5v1.1l.3 .2M93.2 49v1.1l.3 .2M93.9 52.3h1M93.9 49.8h1M95.3 50.3l.4-1.3 .5 1.3M95.4 49.9h.6"/>
<path d="M95.5 51.5h.4l.3 .3-.3 .3 .3 .2v.3l-.2 .2h-.5zM95.5 52.1h.4M152.2 98.5v1.3h.6M153.2 99h.5v.8M153.7 99.2l-.6 .3 .2 .3 .4-.1M154.3 99l.4-.1 .2 .2M154.3 98.9v.9M154.9 99.1l.2-.2 .3 .1v.8M154.9 99.1v.7M156 99l.4-.1 .2 .3-.1 .5h-.5M156 98.9v1.3M157.2 99.3h1"/>
<path d="M159.4 98.6a.58 .58 0 0 0-.7 .5 .58 .58 0 0 0 .8 .5v-.4h-.3M160.8 98.5v1.3l-.8-1.3v1.3M161.4 98.5a.64 .64 0 0 1 .7 .6 .64 .64 0 0 1-.7 .7z"/>
</g>
<g fill="none" stroke="#725600" stroke-width=".21">
<path d="M27.9 53.9v-1.3l.4 .9 .4-.9v1.3M28.1 51.4v-1.3l.4 .9 .4-.9v1.3M29.4 53.2l.1-.2 .4 .2-.1 .6h-.4zM29.5 50.6l.2-.1 .4 .1-.1 .7-.5-.1zM30.3 53h.5M30.5 52.6v1.1l.3 .2M30.5 50.5h.5M30.7 50.1v1.1l.3 .2M31.2 53.2l.2-.2 .4 .2-.1 .6h-.5zM31.4 50.6l.2-.1 .4 .1-.1 .7-.5-.1zM32.4 53v.9M32.6 50.5v.9"/>
<path d="M32.7 53l-.3 .3M32.9 50.5l-.3 .2M34.9 52.7a.56 .56 0 0 0-.8 .6 .56 .56 0 0 0 .8 .5M35 50.2a.56 .56 0 0 0-.8 .5 .56 .56 0 0 0 .8 .5M35.4 53.2l.2-.2 .3 .2v.6h-.5zM35.6 50.6l.2-.1 .3 .1v.7l-.5-.1zM36.5 53.2l.5-.1 .1 .8M36.5 53v.9M36.7 50.6h.5l.1 .8M36.7 50.5v.9M37.5 53h.5M37.7 52.6v1.1l.3 .2"/>
<path d="M37.7 50.5h.5M37.9 50.1v1.1l.3 .2M38.4 53v.9M38.6 50.5v.9M38.8 53l-.4 .3M39 50.5l-.4 .2M39.2 53.2l.2-.2 .3 .2v.6h-.5zM39.4 50.6l.2-.1 .3 .1v.7l-.5-.1zM40.4 52.6v1.1l.1 .2M40.5 50.1v1.1l.2 .2M42 52.6h.4l.3 .3-.3 .3 .3 .1v.3l-.2 .3h-.5zM42 53.2h.4"/>
<path d="M42 51.4l.4-1.3 .4 1.3M42.1 51h.6M43.2 52.7h.7l.6 .6-.6 .6h-.7zM43.2 50.1h.7l.6 .7-.6 .6h-.7zM124.5 56.4v1.3h.7M125.6 56.9h.5v.8M126.1 57.2l-.6 .2 .2 .3 .4-.1M126.7 57l.4-.1 .2 .1M126.7 56.9v.8M127.3 57l.2-.1h.3v.8M127.3 57v.7M128.4 56.9h.4l.2 .2-.1 .5h-.5"/>
<path d="M128.4 56.9v1.2M129.6 56.5h.6l.6 .6-.6 .7h-.6zM28.4 99.6h.5M29.1 98.9h-.7v1.3M29.5 99.4h.5l.1 .8M30.1 99.7l-.6 .2 .2 .3h.4M30.7 99.5l.5-.1v.8M30.7 99.4v.8M31.8 99h.7l.6 .6-.6 .7h-.7z"/>
</g>
<path d="M175 88.7h3" fill="none" stroke="#840000" stroke-width=".33"/>
<path d="M175 87.7h3" fill="none" stroke="#840000" stroke-width=".3"/>
<path d="M173.2 89.5a.56 .56 0 0 0-.8 .6 .56 .56 0 0 0 .8 .5M173.6 89.4h.8l-.4 .5 .4 .1v.6l-.2 .1-.6-.1M174.3 86.9h.8M174.3 86l.4-.4v1.3M175.6 86l.1 .8h.4M176.1 86v.9" fill="none" stroke="#006464" stroke-width=".21"/>
<path d="M187.3 81.1l.8 1.5h-1.6z" fill="#840000"/>
<g fill="none" stroke="#840000" stroke-width=".21">
<path d="M177.8 77.4h.7M178.5 76.7h3.6v1.5h-3.6zM182.1 77.4h.8M187.3 79.3v5.1M176.5 97.1v2.5M183.5 85.7v2M183.5 88.7v2.1M184.8 81.9h2.5M186.5 82.6l.8-1.5 .8 1.5"/>
<circle cx="176.5" cy="100.4" r=".76"/>
</g>
<path d="M186.5 81.1h.1M186.5 81.1h1.6l.2 .3" fill="none" stroke="#840000" stroke-width=".25"/>
<g fill="none" stroke="#006464" stroke-width=".21">
<path d="M178.7 78.8l.5-.2 .2 .4-.7 .9h.7M178.8 75.5l.6-.1v-.4l-.6-.2v1.3M179.1 75.5l.4 .6M180 78.6v1.3M180 76.1h.7M180 75.2l.4-.4v1.3M180.2 79.2l.5 .7M180.7 78.6l-.7 .8M181.2 78.8l.5-.2 .2 .4-.8 .9h.8M181.3 75l.2-.2a.68 .68 0 0 1 .4 .7 .68 .68 0 0 1-.4 .6l-.3-.5zM188.4 79.3v1l.2 .2h.4l.1-.2v-1M190.2 79.3h-.3l-.2 .3-.1 .7 .3 .2 .4-.1-.1-.6h-.3l-.3 .2"/>
<path d="M180.7 90.7h.7M180.7 89.8l.3-.4v1.3M180.8 85.7a.56 .56 0 0 0-.8 .6 .56 .56 0 0 0 .8 .5M181.3 86.9h.7M181.3 86l.4-.4v1.3M181.9 89.9l.1 .7h.5M182.5 89.9v.8M182.5 85.7l.5-.1 .2 .4-.7 .9h.7M188.8 81.2h.7M189.2 81.2v1.2M190 81.2v1.2h.6M191.2 81.1l-.3 .9h.8"/>
<path d="M191.5 81.6v.8M192.1 81.2h.8l-.5 .5 .4 .1v.5l-.2 .1-.5-.1M193.3 82.4h.8M193.3 81.5l.4-.3v1.2"/>
</g>
<path d="M182 88.7h3" fill="none" stroke="#840000" stroke-width=".33"/>
<path d="M182 87.7h3" fill="none" stroke="#840000" stroke-width=".3"/>
<path d="M171.8 103.4v-1.3l.4 .9 .4-.9v1.3M173.2 102.7l.2-.2 .4 .2-.1 .6h-.5zM174.2 102.5h.5M174.4 102.1v1.1l.3 .2M175.1 102.7l.2-.2 .3 .2v.6h-.5zM176.2 102.5v.9M176.6 102.5l-.4 .3M178.7 102.2a.58 .58 0 0 0-.8 .6 .58 .58 0 0 0 .8 .5v-.5h-.2M180 102.1v1.3l-.7-1.3v1.3M180.6 102.1a.64 .64 0 0 1 .7 .7 .64 .64 0 0 1-.7 .6z" fill="none" stroke="#840084" stroke-width=".21"/>
<path d="M198.7 85l1-.3v.7z" fill-rule="evenodd" fill="#840000"/>
<g fill="none" stroke="#840000" stroke-width=".21">
<path d="M160 77.4h2.6M172.7 77.4h2.5M137.8 83.1h.8M138.6 82.4h3.5v1.5h-3.5zM142.1 83.1h.8M156.2 86.3v2M156.2 89.4v2M167.6 82.5v2.5M198.1 82.5v.6M198.1 86.9v.7M198.7 85h.3M198.7 85l1-.3v.7z"/>
<path d="M199.6 85h1"/>
</g>
<path d="M162.6 75.5h10.1v7h-10.1zM197.3 83.2h1.6v3.6h-1.6z" fill="none" stroke="#840000" stroke-width=".25"/>
<path d="M160.9 75.7h.7l-.4 .5 .4 .1v.6l-.2 .1-.5-.1M173.6 77h.7M173.6 76.1l.4-.4v1.3M167.2 83.4v.8l-.9-.8-.4 .3 .2 .4M197.7 87.4v-.3h-.3v.2l-.3-.2v.4M197.7 87.4v.1M197.8 82.6v.4M197.8 82.8h-.7l.2 .2M200 84.1h.2l.1 .1-.4 .5h.4" fill="none" stroke="#a90000" stroke-width=".21"/>
<g fill="none" stroke="#006464" stroke-width=".21">
<path d="M163.2 76.7v1.3M164.5 76.7v1.3l-.7-1.3v1.3M164.9 72.9h.8l-.5 1.3M166.4 73.5l-.2-.3 .2-.3h.2l.3 .3-.3 .3M166.4 73.5l-.2 .2v.4l.2 .1 .4-.1 .1-.1v-.3l-.3-.2M166.4 73.5h.2M166.7 70.4v1l.2 .3 .4-.1 .1-.2v-1M166.9 79.9h1.3l-1.3 .7h1.3M167 78.8a.68 .68 0 0 1 .8-.2 .68 .68 0 0 1 .4 .6h-1.3zM167.4 72.9v1.3h.6M167.9 70.4h.8l-.5 .5 .4 .1v.5l-.2 .2-.5-.2M168.5 73l.2-.1a.68 .68 0 0 1 .4 .7 .68 .68 0 0 1-.4 .6l-.3-.5z"/>
<path d="M169 76.9l.3-.2a.43 .43 0 0 1 .5 .5v.4a.42 .42 0 0 1-.4 .4 .42 .42 0 0 1-.4-.4zM170.3 72.9h-.6l-.1 .6h.6l.1 .6-.2 .1-.5-.1M170.4 76.7v1.1l.2 .2 .4-.1 .1-.1v-1.1M171.5 76.7h.7M171.9 76.7v1.3M138.6 85.3l.6-.1 .1-.5-.7-.1v1.3M138.9 85.3l.4 .6M139.1 80.5l-.3 .9h.8M139.4 81v.8M139.9 80.5h.9l-.6 1.3M140.5 85.1l-.2 .3-.4-.1v-.6l.4-.1 .2 .2v.8l-.2 .2-.4 .1M141.3 80.5v1.3"/>
<path d="M141.5 81.1l.5 .7M142 80.5l-.7 .8M157.8 92h.8M157.8 91.1l.4-.4v1.3M158 86.4a.56 .56 0 0 0-.8 .5 .56 .56 0 0 0 .8 .5M158.5 87.5h.7M158.5 86.6l.3-.3v1.2M159.2 90.8l.1-.1a.68 .68 0 0 1 .5 .6 .68 .68 0 0 1-.5 .7 .84 .84 0 0 1-.1-1.2zM160.3 91.1l.1 .8 .5-.1M160.9 91.1v.9M167 81.2a.58 .58 0 0 0 .6 .7 .58 .58 0 0 0 .5-.8h-.4v.3M193.3 86.9h.7"/>
<path d="M193.3 86l.3-.4v1.3M193.5 84.4l.6-.1v-.5l-.6-.1v1.3M193.8 84.4l.4 .6M194.5 83.7l.5 1.3 .4-1.3M194.6 85.7l.2-.1a.68 .68 0 0 1 .4 .7 .68 .68 0 0 1-.4 .6l-.3-.5zM195.7 85.6v1.3M195.7 85h.8M195.7 84.1l.4-.4v1.3M195.9 86.2l.6 .7M196.5 85.6l-.8 .7"/>
</g>
<path d="M154.7 89.4h3" fill="none" stroke="#840000" stroke-width=".33"/>
<path d="M154.7 88.3h3" fill="none" stroke="#840000" stroke-width=".3"/>
<path d="M135.3 101.8h2.5v.5h-2.5z" fill-rule="evenodd" fill="#840000"/>
<path d="M141.9 95.3h1M142.2 94.8h3.9M143.6 95.3h1.1M145.4 95.3h1M135.3 101.8h2.5v.5h-2.5z" fill="none" stroke="#840000" stroke-width=".25"/>
<path d="M142.4 95.3v2.6h3.5v-2.6M144.2 92v2.8M144.2 95.3v1.8h-2.6M145.9 97.1h.8M136.5 100.3v1.5" fill="none" stroke="#840000" stroke-width=".21"/>
<path d="M134.9 103.5a.58 .58 0 0 0-.7 .5 .58 .58 0 0 0 .8 .5v-.4h-.2M136.3 103.4v1.3l-.8-1.3v1.3M136.9 103.4a.64 .64 0 0 1 .7 .6 .64 .64 0 0 1-.7 .7zM138.1 103.4a.64 .64 0 0 1 .8 .6 .64 .64 0 0 1-.8 .7z" fill="none" stroke="#006464" stroke-width=".21"/>
<path d="M144.2 95.6l.3 1h-.7z" fill="#840000"/>
<path d="M143.9 97.5l.6 .4-.6 .3zM144.2 95.6l.3 1h-.7zM144.7 97.4l-.3 1" fill="none" stroke="#840000" stroke-width=".21"/>
<circle cx="144.2" cy="96.2" r="2.79" fill="none" stroke="#840000" stroke-width=".25"/>
<circle cx="142.4" cy="97.1" r=".25" fill="#840000"/>
<circle cx="142.4" cy="97.1" r=".25" fill="none" stroke="#840000" stroke-width=".21"/>
<circle cx="145.9" cy="97.1" r=".25" fill="#840000"/>
<g fill="none" stroke="#840000" stroke-width=".21">
<path d="M59.7 34.3v2M59.7 37.3v2M80.1 50.8h2.5M80.1 53.3h2.5M82.6 48.2h5.1v7.6h-5.1zM135.8 59.8h1.5v3.5h-1.5zM136.5 59v.8M166.1 53.9h3.1v.4h-3.1zM166.1 54.9h3.1v.4h-3.1zM166.4 53.1h.5M166.6 52.8v.5M167.6 52v1.9"/>
<path d="M167.6 55.3v1.8M134.8 68.3v.2M134.8 68.5h.2M135.3 68.8v.2M135.3 69h.2M135.3 68l-.5 .5M135.8 68.5l-.5 .5M136.5 63.3v.8M136.5 66v5.1M143.4 71.2h1.5v3.6h-1.5zM144.2 70.4v.8M144.2 74.8v.7"/>
<path d="M204.4 77.4h2.6M209.5 72.3v3.9M217.1 80h2.6M139.1 97.1h2.5M144.2 89.5v2.5M146.7 97.1h2.5M204.4 82.5h2.6M209.5 83.8v3.8M219.7 81.2v2.1M219.7 84.3v2M236.7 83.3h1.5v3.5h-1.5zM237.4 82.5v.8"/>
<path d="M237.4 86.8v.8M220.3 102.8h2.5M220.3 107.9h2.5M233 105.4h2.5"/>
<circle cx="83.9" cy="49.5" r=".38"/>
<circle cx="145.9" cy="97.1" r=".25"/>
</g>
<g fill="none" stroke="#a90000" stroke-width=".21">
<path d="M81 50.4h.7M81 49.4l.3-.3v1.3M81 51.7l.4-.1 .3 .4-.8 .9h.8M205.3 75.7h.8l-.4 .5 .3 .1v.6l-.2 .1-.5-.1M208.4 74.1l-.3-.2-.3 .2 .1 .4 .2 .1 .3-.2M208.4 74.1l.2-.2 .4 .1 .1 .1-.1 .4-.1 .1h-.4l-.1-.2M208.4 74.1v.3M218 79.5h.8M218 78.6l.4-.3v1.2M140 96.7h.7M140 95.8l.3-.4v1.3M142.9 90.5h.8"/>
<path d="M143.3 90.3v.8l-.9-.3M147.8 96l-.2 .2 .1 .4 .1 .1 .4-.1 .1-.2v-.2l-.2-.2M147.8 96l-.2-.3 .2-.3h.3l.2 .3-.2 .3M147.8 96h.3M205.3 80.9l.5-.1 .3 .4-.8 .9h.8M208.3 85.4h.8M208.7 85.3v.7l-.9-.3M221.8 106.2l-.3 .1-.2 .2-.1 .7 .3 .3 .4-.1-.1-.7h-.3l-.3 .2M221.9 101.1h-.6l-.1 .6h.6l.1 .6-.2 .1-.5-.1M233.8 103.7h.9l-.6 1.2"/>
</g>
<g fill="none" stroke="#006464" stroke-width=".21">
<path d="M62.6 38.7h.8M62.6 37.8l.4-.4v1.3M63.4 35a.56 .56 0 0 0-.8 .5 .56 .56 0 0 0 .8 .5M63.9 36.1h.7M63.9 35.2l.4-.4v1.3M64 37.5l.1-.1a.68 .68 0 0 1 .5 .6 .68 .68 0 0 1-.5 .7l-.3-.5zM65.2 37.5l.2-.1a.68 .68 0 0 1 .4 .6 .68 .68 0 0 1-.4 .7l-.3-.5zM65.4 35.4l-.3-.2 .3-.4h.2l.2 .3-.2 .3M65.4 35.4l-.3 .2 .1 .4 .2 .1h.3l.1-.2v-.3l-.2-.2M65.4 35.4h.2M66.3 37.8v.9M66.3 37.9h.5l.1 .8"/>
<path d="M83.4 57.7v-1.3l.5 .9 .4-.9v1.3M83.4 51.4h.8M83.4 50.4l.4-.3v1.3M83.4 52.7l.5-.1 .3 .4-.8 .9h.8M84.9 46.4a.56 .56 0 0 0-.8 .5 .56 .56 0 0 0 .8 .5M84.9 56.9h.4l.2 .2v.4l-.2 .2-.5-.2zM85.9 56.9h.4M86 56.4v1.1l.3 .2M86.2 46.3v1.2l-.8-1.2v1.2M86.7 46.4l.5-.1 .2 .3-.8 .9h.8M86.8 57l.1-.1 .4 .1-.1 .6h-.4zM87.9 56.9v.8"/>
<path d="M88.3 56.9l-.4 .2M162.6 55.7l-.3 .9h.8M162.9 56.2v.9M163.1 52.1a.56 .56 0 0 0-.8 .5 .56 .56 0 0 0 .8 .5M163.4 55.8h.9l-.6 1.3M163.5 52.1l.5-.1 .3 .3-.8 1h.8M164.8 55.9l.2-.1a.68 .68 0 0 1 .4 .6 .68 .68 0 0 1-.4 .7l-.3-.5zM166 56.2v.8l.5-.1M166.5 56.2v.9M125.4 69.1v1.3h.6M126.4 69.6h.5l.1 .8M127 69.8l-.6 .3 .2 .3 .4-.1"/>
<path d="M127.6 69.7l.4-.2 .1 .2M127.6 69.5v.9M128.1 69.7l.2-.2 .3 .1 .1 .8M128.1 69.7v.7M129.3 69.6l.3-.1 .3 .3-.1 .5h-.5M129.3 69.5v1.3M131.8 68.9a1.46 1.46 0 0 0 0 2M132.1 69.5l.3 .9 .2-.6 .2 .6 .3-.9M133.1 65.9a.64 .64 0 0 1 .7 .7 .64 .64 0 0 1-.7 .6zM133.6 69.7l.5-.1v.8M133.6 69.1v1.3M134.6 68.9a1.46 1.46 0 0 1 0 2"/>
<path d="M134.9 65.9l-.4 .1-.2 .2v.8l.2 .2 .4-.1v-.6l-.4-.1-.2 .3M138.2 60.4l.4-.2 .3 .4-.8 .9h.8M138.2 62.8l.6-.1 .1-.4-.7-.2v1.3M138.5 62.8l.4 .6M139.4 60.2v1.3M139.4 62.3l.5-.2 .3 .4-.8 .9h.8M139.6 60.8l.6 .7M140.2 60.2l-.8 .8M140.6 60.4l.5-.2 .3 .4-.8 .9h.8M141.2 62.1l-.3 .1-.2 .2-.1 .8 .3 .2 .4-.1-.1-.6-.3-.1-.3 .3M145.8 72.9h.7M145.8 72l.3-.3v1.2"/>
<path d="M146.4 74.9l.6-.1 .1-.5-.7-.1v1.3M146.7 74.9l.4 .6M147.6 71.7h-.6v.6l.6-.1v.6l-.2 .1-.4-.1M147.8 74.7l-.2-.2 .2-.3h.3l.2 .2-.2 .3M147.8 74.7l-.2 .3 .1 .3 .1 .2 .4-.1 .1-.2v-.2l-.2-.3M147.8 74.7h.3M148.3 71.8l.2-.1a.68 .68 0 0 1 .4 .6 .68 .68 0 0 1-.4 .6l-.3-.5zM149.4 72.3h.6l.1-.5-.7-.1v1.2M149.7 72.3l.5 .6M207.5 77.5h1M208 77v1M208.8 78.1l1.3 .4-1.3 .4"/>
<path d="M209.1 77.2h1M209.6 76.7v1M213.1 75.5v1l.2 .2h.4l.1-.2v-1M214.6 76l-.2-.2 .2-.3h.2l.3 .2-.3 .3M214.6 76l-.2 .3v.3l.2 .1h.4l.1-.2v-.2l-.3-.3M214.6 76h.2M215.4 76.7l.5-1.2 .4 1.2M215.6 76.4h.6M207.5 82.6h1M208.8 82.6l1.3 .4-1.3 .4M209.6 81.2v1M211.6 83.1v1.3h.6"/>
<path d="M212.6 84.4v-1.3l.4 .9 .5-.9v1.3M214 83.1h.7l-.4 .5 .4 .1v.5l-.2 .2-.5-.2M215.9 83.1h-.6l-.1 .6 .6-.1 .1 .6-.2 .2-.5-.2M216.7 83.6l-.3-.2 .3-.3h.2l.3 .2-.3 .3M216.7 83.6l-.3 .3 .1 .3 .2 .2 .3-.1 .2-.2v-.2l-.3-.3M216.7 83.6h.2M220.7 86.3h.7M220.7 85.3l.3-.3v1.3M220.8 81.3a.56 .56 0 0 0-.8 .5 .56 .56 0 0 0 .8 .5M221.3 82.4h.7M221.3 81.5l.4-.3v1.2M221.9 85.4l.1 .8 .5-.1"/>
<path d="M222.5 85.4v.9M223.1 81.2h-.4l-.1 .3-.1 .7 .2 .2 .5-.1-.1-.6h-.4l-.2 .2M239.1 85.2l.2-.1a.68 .68 0 0 1 .4 .6 .68 .68 0 0 1-.4 .7l-.3-.5zM239.2 83.7h.6l.1-.5-.7-.1v1.3M239.5 83.7l.4 .7M240.3 86.3v.1M240.4 84.4h.7M240.4 83.4l.4-.3v1.3M241 85.2l.1-.1a.68 .68 0 0 1 .5 .6 .68 .68 0 0 1-.5 .7 .84 .84 0 0 1-.1-1.2zM241.9 83.6l-.3 .3 .1 .3 .2 .2 .3-.1 .1-.2v-.2l-.2-.3M241.9 83.6l-.3-.2 .3-.3h.2l.2 .2-.2 .3M241.9 83.6h.2"/>
<path d="M242.7 85.1h-.6l-.1 .6h.6l.1 .6-.2 .1-.5-.1M243.3 85.8l.6-.1 .1-.5-.7-.1v1.3M243.6 85.8l.4 .6M143.4 100.4l.3-.2a.43 .43 0 0 1 .5 .4v.5a.42 .42 0 0 1-.4 .4 .42 .42 0 0 1-.4-.4zM143.4 102.8v1.2M143.6 101.2l.7 .4M144 103.4h.6l.1-.5-.7-.1v1.2M144.3 103.4l.5 .6M144.7 101.5h.7M144.7 100.6l.4-.4v1.3M145.3 103.4h.4M145.9 102.8h-.6v1.2"/>
<path d="M146.3 102.8h.8l-.5 1.2M147.8 102.7l-.3 .9h.8M148.1 103.2v.8M148.7 102.8h.8l-.5 1.2M150.1 102.9l.2-.1a.68 .68 0 0 1 .4 .6 .68 .68 0 0 1-.4 .6l-.3-.5zM223.4 102.9h.9M223.4 108h.9M223.9 102.4v1M227.5 108.7v1.3h.6M228.5 110v-1.3l.4 .9 .4-.9v1.3M228.6 100.6v1l.2 .3 .4-.1 .1-.2v-1M229.8 108.7h.8l-.4 .5 .3 .1v.6l-.1 .1-.6-.1"/>
<path d="M230.1 101.1l-.2 .3v.3l.2 .2 .4-.1 .1-.2v-.2l-.2-.3M230.1 101.1l-.2-.2 .2-.3h.3l.2 .2-.2 .3M230.1 101.1h.3M231.1 101.2h.5M231.1 100.6h.5l.2 .2-.2 .4 .2 .1 .1 .3-.3 .3h-.5zM231.8 108.7h-.7v.6h.6l.1 .6-.2 .1-.5-.1M232.5 109.3l-.2-.3 .2-.3h.3l.2 .3-.2 .3M232.5 109.3l-.2 .2 .1 .4 .1 .1 .4-.1 .1-.2v-.2l-.2-.2M232.5 109.3h.3"/>
</g>
<path d="M135.5 69.3h2.1M135.5 67.8h2.1l-1.1 1.5zM207 74.9l10.1 5.1-10.1 5zM222.8 100.3l10.2 5.1-10.2 5z" fill="none" stroke="#840000" stroke-width=".25"/>
<path d="M166.1 55.1h3.1" fill="none" stroke="#840000" stroke-width=".38"/>
<path d="M58.2 37.3h3.1M218.2 84.3h3" fill="none" stroke="#840000" stroke-width=".33"/>
<path d="M58.2 36.3h3.1M218.2 83.3h3" fill="none" stroke="#840000" stroke-width=".3"/>
<path d="M58.5 43.4h2.5v.5h-2.5z" fill-rule="evenodd" fill="#840000"/>
<path d="M58.5 43.4h2.5v.5h-2.5zM59.7 48.2h15.3v12.7h-15.3z" fill="none" stroke="#840000" stroke-width=".25"/>
<g fill="none" stroke="#840000" stroke-width=".21">
<path d="M51.9 36.1h3v.4h-3zM51.9 37.1h3v.4h-3zM52.1 35.3h.5M52.4 35v.5M53.4 34.3v1.8M53.4 37.5v1.8M57.2 53.3h2.5M57.2 50.8h2.5M59.7 41.9v1.5M67.4 45.7v2.5M75 58.4h2.5v.7M75 53.3h2.5"/>
<path d="M75 50.8h2.5M76.8 59.1h1.5v3.6h-1.5zM67.4 60.9v2.6M77.5 62.7v.8"/>
</g>
<g fill="none" stroke="#006464" stroke-width=".21">
<path d="M47.4 37.5l.5-.1 .2 .4-.8 .9h.8M48.2 35a.56 .56 0 0 0-.8 .5 .56 .56 0 0 0 .8 .5M48.6 37.5l.5-.1 .2 .4-.7 .9h.7M48.7 36.1h.7M48.7 35.2l.3-.4v1.3M49.8 34.8h.9l-.6 1.3M49.9 37.8v.8l.5-.1M50.4 37.8v.9M58.1 45.1a.58 .58 0 0 0-.7 .6 .58 .58 0 0 0 .8 .5v-.5h-.2M59.5 45v1.3l-.8-1.3v1.3M60.1 45a.64 .64 0 0 1 .7 .6 .64 .64 0 0 1-.7 .7zM60.7 50.1v1.3"/>
<path d="M60.7 52.6v1.3M61.3 45a.64 .64 0 0 1 .8 .6 .64 .64 0 0 1-.8 .7zM62 50.1v1.3l-.7-1.3v1.3M62 52.6v1.3l-.7-1.3v1.3M62.5 52.7l.5-.1 .3 .4-.8 .9h.8M62.5 51.4h.8M62.5 50.4l.4-.3v1.3M66.7 58h1.2l-1.2 .7h1.2M66.7 50.4l1.2 .4-1.2 .5M66.7 59.4a.58 .58 0 0 0 .6 .7 .58 .58 0 0 0 .5-.8h-.4v.2M66.7 56.9a.68 .68 0 0 1 .8-.2 .68 .68 0 0 1 .4 .7h-1.2zM67.9 49.1h-1.2l.9 .5-.9 .4h1.2"/>
<path d="M68.4 45.6a.64 .64 0 0 1 .7 .7 .64 .64 0 0 1-.7 .6zM69.7 46.3l.6-.1v-.4l-.6-.2v1.3M69.8 52.8l.3-.2a.43 .43 0 0 1 .5 .4v.5a.42 .42 0 0 1-.4 .4 .42 .42 0 0 1-.4-.4zM69.8 50.3l.3-.2a.43 .43 0 0 1 .5 .4v.4a.42 .42 0 0 1-.4 .5 .42 .42 0 0 1-.4-.5zM70 46.3l.4 .6M70.8 45.6l.4 1.3 .4-1.3M71 57.7v1.3M71.2 52.6v1l.2 .3 .4-.1 .1-.2v-1M71.2 50.1v1l.2 .3 .4-.1 .1-.2v-1M71.6 57.7v1.3h.6M72.2 46.2l-.2-.3 .2-.3h.3l.2 .3-.2 .3M72.2 46.2l-.2 .2v.4l.2 .1 .4-.1 .1-.1v-.3l-.2-.2"/>
<path d="M72.2 46.2h.3M72.3 52.6h.7M72.3 50.1h.7M72.6 57.7v1.3M72.7 50.1v1.3M72.7 52.6v1.3M73.2 59v-1.3l.4 .9 .5-.9v1.3M73.4 52.7l.5-.1 .2 .4-.8 .9h.8M73.4 51.4h.7M73.4 50.4l.4-.3v1.3M73.4 46.2l-.2 .2v.4l.2 .1 .4-.1 .1-.1v-.3l-.2-.2M73.4 46.2l-.2-.3 .2-.3h.3l.2 .3-.2 .3"/>
<path d="M73.4 46.2h.3M74.3 45.6h.9l-.6 1.3M75.6 46.9h.7M75.6 46l.4-.4v1.3M76.9 45.6a.64 .64 0 0 1 .7 .7 .64 .64 0 0 1-.7 .6zM78.1 45.6a.64 .64 0 0 1 .8 .7 .64 .64 0 0 1-.8 .6zM79.2 59.6h.6l.1-.5-.7-.1v1.2M79.2 46.9l.5-1.3 .4 1.3M79.3 46.5h.7M79.5 59.6l.4 .6M80.4 59.3l.4-.3v1.2M82.3 59.5l-.2 .3-.4-.1v-.6l.4-.1 .2 .2v.7l-.2 .3h-.4"/>
<path d="M62.7 62.1v1.1l.2 .2 .4-.1 .1-.1v-1.1M64.3 62.1l-.3 .9h.8M64.6 62.6v.8M79.1 63.4h.8l-.5 .5 .4 .1v.6l-.2 .1-.5-.1M80.4 60.2h.7M80.5 63.5l.1-.1a.68 .68 0 0 1 .5 .6 .68 .68 0 0 1-.5 .7l-.3-.5zM81.6 63.4v1.3M81.8 64l.5 .7M82.3 63.4l-.7 .7"/>
</g>
<path d="M58.1 49.1h.7l-.4 .5 .4 .1v.5l-.2 .2-.5-.2M58.1 51.7l.5-.1 .2 .4-.7 .9h.7M65.7 46.7v.6h.6l-.1-.6h.6l.1 .1-.1 .5M76.1 52.2l-.2-.3 .2-.3h.3l.2 .3-.2 .3M76.1 52.2l-.2 .2v.4l.2 .1 .4-.1 .1-.1v-.3l-.2-.2M76.1 52.2h.3M76.2 56.6l-.3 .9h.8M76.5 49.1h-.4l-.2 .3v.7l.2 .3 .4-.2v-.6h-.4l-.2 .2M76.5 57.1v.9M66.9 61.8v.8M66.9 62.2h-1.2l.3 .4" fill="none" stroke="#a90000" stroke-width=".21"/>
<path d="M51.9 37.3h3" fill="none" stroke="#840000" stroke-width=".38"/>
<path d="M52.1 43.4h2.6v.5h-2.6z" fill-rule="evenodd" fill="#840000"/>
<path d="M52.1 43.4h2.6v.5h-2.6zM179.1 47h15.2v10.1h-15.2zM201.9 53.3l1.3 2.5h-2.6zM202.5 52.7h.7v.6h-2.6v.6h.7M218.4 64.7h2.5M219.7 64.7l1.2 2.6h-2.5z" fill="none" stroke="#840000" stroke-width=".25"/>
<g fill="none" stroke="#840000" stroke-width=".21">
<path d="M53.4 41.9v1.5M172.7 49.5v2M172.7 52.5v2.1M176.5 54.6h2.6M176.5 49.5h2.6M186.7 57.1v2.6M194.3 54.6h2.5M194.3 49.5h2.5M201.9 50.8v7.6M204.4 49.5h.6a.51 .51 0 0 1 .5-.5 .51 .51 0 0 1 .5 .5 .51 .51 0 0 1 .5-.5 .51 .51 0 0 1 .5 .5 .51 .51 0 0 1 .5-.5 .51 .51 0 0 1 .5 .5 .51 .51 0 0 1 .5-.5 .51 .51 0 0 1 .5 .5h.5M211.4 52v2.1M211.4 55.1v2"/>
<path d="M216.2 53.9h3.1v.4h-3.1zM216.2 54.9h3.1v.4h-3.1zM216.5 53.1h.5M216.8 52.8v.5M217.8 52v1.9M217.8 55.3v1.8M190.5 77.4h.7M191.2 76.7h3.6v1.5h-3.6zM194.8 77.4h.8M219.7 62.2v7.6"/>
</g>
<g fill="none" stroke="#006464" stroke-width=".21">
<path d="M51.8 45.1a.58 .58 0 0 0-.7 .6 .58 .58 0 0 0 .8 .5v-.5h-.3M53.1 45v1.3l-.7-1.3v1.3M53.7 45a.64 .64 0 0 1 .8 .6 .64 .64 0 0 1-.8 .7zM55 45a.64 .64 0 0 1 .7 .6 .64 .64 0 0 1-.7 .7zM173.7 56.4h.7M173.7 55.5l.4-.3v1.2M175 55.6v.8l.5-.1M175.5 55.6v.8M175.8 50.2a.56 .56 0 0 0-.8 .5 .56 .56 0 0 0 .8 .5M176.2 51.4h.8M176.2 50.4l.4-.3v1.3M177.7 50l-.3 .9h.8"/>
<path d="M178 50.5v.9M179.8 53.9l.4 1.3 .4-1.3M179.8 48.8l.4 1.3 .4-1.3M181.1 48.8v1.3M181.8 54a.56 .56 0 0 0-.8 .5 .56 .56 0 0 0 .8 .5M182.4 48.8v1.3l-.7-1.3v1.3M183.3 44.4l.9 1.2M184.2 44.4l-.9 1.2M184.6 44.4v1.2h.7M185.7 41.8v1.1l.2 .2 .4-.1 .1-.1v-1.1M185.9 44.3l-.3 .9h.8M186 54.2h1.3l-1.3 .7h1.3"/>
<path d="M186 55.5a.58 .58 0 0 0 .6 .8 .58 .58 0 0 0 .5-.8h-.4v.2M186 53.1a.68 .68 0 0 1 .8-.2 .68 .68 0 0 1 .5 .7h-1.3zM186.2 44.8v.8M186.9 41.8h.9l-.6 1.3M186.9 44.5l.2-.1a.68 .68 0 0 1 .5 .6 .68 .68 0 0 1-.5 .6l-.3-.4zM188 45.6h.8M188 44.7l.4-.3v1.2M189.9 44.4h-.6l-.1 .6 .6-.1 .1 .6-.2 .1-.5-.1M191.6 54.5h.4M192 48.9h-.7v.4l.6 .2 .1 .3-.3 .3-.4-.1M192.2 53.9h-.6v1.3M192.4 48.8l.3 1.3 .3-.9 .2 .9 .3-1.3"/>
<path d="M192.7 54.5h.4M192.7 53.9h.4l.3 .2-.3 .4 .3 .1v.3l-.2 .3h-.5zM203.6 57.1l-.6 .1v.3l.5 .3 .1 .3-.2 .2h-.5M204.2 54.5a.64 .64 0 0 1 .8 .7 .64 .64 0 0 1-.8 .6zM204.8 57.1l-.6 .1v.3l.5 .3 .1 .3-.2 .2h-.5M205.1 46.8l-.3 1h.8M205.4 47.3v.9M205.7 54.5l-.3 .9h.8M205.9 46.9h.9l-.6 1.3M206 57.1h-.6l-.1 .6 .6-.1 .1 .6-.2 .1-.5-.1M206 54.9v.9M206.2 50.1v1.3h.6"/>
<path d="M206.8 57l-.3 .9h.8M207.1 57.5v.8M207.1 51.4h.8M207.1 50.4l.4-.3v1.3M207.3 47.3v.8h.5M207.8 47.3v.9M208.4 46.9v1.3M208.4 47.5h.7M209.1 46.9v1.3M212.4 57.7h.7M212.4 56.8l.4-.4v1.3M213.2 52.1a.56 .56 0 0 0-.8 .5 .56 .56 0 0 0 .8 .5"/>
<path d="M213.7 53.3h.7M213.7 52.3l.3-.3v1.3M213.7 56.5l.2-.1a.68 .68 0 0 1 .5 .7 .68 .68 0 0 1-.5 .6l-.3-.5zM214.9 56.9v.7h.5M215.4 56.9v.8M215.6 52.5l-.2 .3-.4-.1-.1-.6 .5-.1 .2 .2v.8l-.2 .2-.4 .1M219.1 56.4l-.3 .9h.7M219.4 56.9v.8M219.5 52.1a.56 .56 0 0 0-.7 .5 .56 .56 0 0 0 .7 .5M219.9 56.4h.9l-.6 1.3M220 53.3h.8M220 52.3l.4-.3v1.3"/>
<path d="M221.3 56.5l.2-.1a.68 .68 0 0 1 .4 .7 .68 .68 0 0 1-.4 .6l-.3-.5zM221.9 52h-.6l-.1 .6 .6-.1 .1 .6-.2 .2-.5-.2M222.4 56.9l.1 .7h.5M223 56.9v.8M190.8 74.8h.8l-.5 1.3M191.5 73.6l.6-.1v-.5l-.6-.1v1.3M191.8 73.6l.4 .6M192 76.1h.7M192 75.2l.4-.4v1.3M192.7 74.2h.7M192.7 73.3l.3-.4v1.3M193.3 74.8v1.3"/>
<path d="M193.5 75.4l.5 .7M193.8 72.9h.9l-.6 1.3M194 74.8l-.7 .8M195.2 74.8h-.6l-.1 .6h.6l.1 .6-.2 .1-.5-.1M210.6 69.9h.8M210.6 69l.4-.4v1.3M212.6 68.6v1.3l-.7-1.3v1.3M213.5 68.6l-.3 .9h.8M213.8 69v.9M214.4 69.9h.7M214.4 69l.3-.4v1.3M215.6 64a.64 .64 0 0 1 .8 .7 .64 .64 0 0 1-.8 .6z"/>
<path d="M215.9 68.6l-.3 .9h.8M216.2 69v.9M217 69.2l-.2 .2 .1 .4 .1 .1 .4-.1 .1-.2v-.2l-.2-.2M217 69.2l-.2-.3 .2-.3h.3l.2 .3-.2 .3M217 69.2h.3M217.5 64h-.6v.6h.6v.6l-.2 .1-.4-.1M217.9 68.6l.3 1.3 .3-.9 .2 .9 .3-1.3"/>
</g>
<path d="M177.7 52.8l-.3 .9h.8M178 53.3v.9M178.1 47.8h-.6l-.1 .6h.6l.1 .6-.2 .1-.5-.1M186.3 58v.7M186.3 58.4h-1.3l.3 .3M195.1 47.8h.8l-.4 .5 .4 .1v.6l-.2 .1-.6-.1M195.2 53l.5-.1 .2 .4-.8 .9h.8" fill="none" stroke="#a90000" stroke-width=".21"/>
<path d="M171.2 52.5h3M209.9 55.1h3" fill="none" stroke="#840000" stroke-width=".33"/>
<path d="M171.2 51.5h3M209.9 54.1h3" fill="none" stroke="#840000" stroke-width=".3"/>
<path d="M216.2 55.1h3.1" fill="none" stroke="#840000" stroke-width=".38"/>
<path d="M225.4 54.6l1-.4v.8z" fill-rule="evenodd" fill="#840000"/>
<g fill="none" stroke="#840000" stroke-width=".21">
<path d="M224.8 52v.7M224.8 56.5v.6M225.4 54.6h.2M225.4 54.6l1-.4v.8zM226.3 54.6h1M227.3 45.7v2.5M236.2 45.7v2.5M237.4 54.6h2.6M237.4 52h2.6M237.4 49.5h2.6M240 47h5.1v10.1h-5.1zM224 64.2h1.5v3.6h-1.5z"/>
<path d="M224.8 63.5v.7M224.8 67.8v.7M240 61.6h2.5"/>
<circle cx="227.3" cy="44.9" r=".76"/>
<circle cx="236.2" cy="44.9" r=".76"/>
<circle cx="241.3" cy="55.8" r=".38"/>
<circle cx="243.3" cy="61.6" r=".76"/>
</g>
<path d="M224 52.8h1.5v3.6h-1.5z" fill="none" stroke="#840000" stroke-width=".25"/>
<path d="M224.4 56.6h-.3l-.1 .2-.2-.2v.4M224.4 56.6v.1M224.4 56.7v.3M224.4 52.2v.3M224.4 52.4h-.6l.2 .1M226.6 53.7l.3-.1 .1 .2-.4 .4h.4M238.3 47.8h.8l-.4 .5 .3 .1v.6l-.2 .1-.5-.1M238.4 54.2h.7M238.4 53.3l.3-.4v1.3M238.4 50.5l.4-.1 .3 .3-.8 .9h.8" fill="none" stroke="#a90000" stroke-width=".21"/>
<g fill="none" stroke="#006464" stroke-width=".21">
<path d="M227.5 56.4h.8M227.5 55.5l.4-.3v1.2M227.7 53.3l.6-.1 .1-.5-.7-.1v1.3M228 53.3l.4 .6M228.8 52.6l.4 1.3 .5-1.3M228.9 55.3l.2-.1a.68 .68 0 0 1 .4 .6 .68 .68 0 0 1-.4 .6l-.3-.5zM230 52.6h.7l-.4 .5 .4 .1v.6l-.2 .1-.5-.1M230 55.2v1.2M230.2 55.7l.5 .7M230.7 55.2l-.7 .7M240.8 48.8h.8l-.5 .5 .4 .1v.6l-.2 .1-.5-.1M240.8 51.5l.5-.1 .3 .3-.8 .9h.8"/>
<path d="M240.8 55.2h.8M240.8 54.3l.4-.4v1.3M242.3 45v1.3h.6M242.4 57.8a.56 .56 0 0 0-.8 .5 .56 .56 0 0 0 .8 .5M243.3 45.5h.5l.1 .8M243.7 57.7v1.3l-.8-1.3v1.3M243.9 45.7l-.6 .3 .1 .3 .5-.1M244.5 45.5l.3-.1 .2 .2M244.5 45.4v.9M244.5 57.6l-.3 .9h.8M244.8 58.1v.9M245 45.6l.2-.2 .3 .1 .1 .8"/>
<path d="M245 45.6v.7M246.2 45.5l.3-.1 .3 .3-.1 .5h-.5M246.2 45.4v1.3M226.4 66.7l.5-.1 .2 .3-.8 1h.8M226.4 64.7l.6-.1 .1-.4-.7-.2v1.3M226.7 64.7l.5 .6M227.5 66.6h.9l-.6 1.3M227.6 65.3h.8M227.6 64.4l.4-.4v1.3M228.9 66.7l.2-.1a.68 .68 0 0 1 .4 .6 .68 .68 0 0 1-.4 .7l-.3-.5zM229.5 64l-.4 .1-.2 .2v.8l.2 .2 .4-.1v-.6l-.4-.1-.2 .3M230.1 67.2h.6v-.5l-.6-.1v1.3"/>
<path d="M230.4 67.2l.4 .7"/>
</g>
<g fill="none" stroke="#840084" stroke-width=".21">
<path d="M224.9 40.9h.9M225 45.2h.8M225 43.5h1.3M225.1 43.5l-.1-.3 .2-.3 .6 .1v.5M225.2 44.7l-.2 .2 .1 .3M225.2 44.7h.6M225.3 45.8l.2 .6 .3-.2v-.4M225.4 40.4v1M225.8 46.8v.6h-1.2M225.8 45.8l-.7 .1v.5M225.8 44.1l-.7 .1-.1 .3 .2 .2M233.8 47.1a.56 .56 0 0 0 .5 .8 .56 .56 0 0 0 .6-.8"/>
<path d="M234.1 46h.9M234.1 45.1l.3 .3M234.1 45.4h.9M234.1 41.3v.5M234.1 44.3l.3 .3M234.1 44.6h.9M234.1 42.8h.9M234.9 46v.5l-.8 .1M234.9 43.4l.1 .3-.2 .2h-.6v-.5l.2-.1 .2 .6M235 41.3l-.2 .3h-1.1M235 42.2l-.8 .1 .1 .5M241.6 62.8v1.2h.6"/>
<path d="M242.6 63.3h.5l.1 .7M243.2 63.5l-.6 .2 .1 .3h.5M243.8 63.3l.3-.1 .2 .2M243.8 63.2v.8M244.3 63.4l.2-.2 .3 .1v.7M244.3 63.4v.6M245.5 63.3l.3-.1 .3 .2-.2 .6h-.4M245.5 63.2v1.3M247.6 63.6h.9"/>
</g>
<path d="M66.1 67.5h2.5v.5h-2.5z" fill-rule="evenodd" fill="#840000"/>
<path d="M66.1 67.5h2.5v.5h-2.5z" fill="none" stroke="#840000" stroke-width=".25"/>
<g fill="none" stroke="#840000" stroke-width=".21">
<path d="M67.4 66v1.5M49.6 97.1l-1.9 1.9M53.4 93.3h2.5M53.4 90.8h2.5M53.4 88.2h2.5M55.9 85.7h5.1v10.1h-5.1zM47.7 100.3l1.9 1.9M49.6 102.2h.1"/>
<circle cx="57.2" cy="94.6" r=".38"/>
</g>
<g fill="none" stroke="#006464" stroke-width=".21">
<path d="M65.8 69.2a.58 .58 0 0 0-.8 .6 .58 .58 0 0 0 .8 .5v-.5h-.2M67.1 69.1v1.3l-.7-1.3v1.3M67.7 69.1a.64 .64 0 0 1 .7 .7 .64 .64 0 0 1-.7 .6zM69 69.1a.64 .64 0 0 1 .7 .7 .64 .64 0 0 1-.7 .6zM56.7 87.5h.8l-.4 .5 .4 .1v.6l-.2 .1-.6-.1M56.8 93.9h.7M56.8 93l.3-.4v1.3M56.8 90.2l.5-.1 .2 .3-.8 .9h.8M58.3 84.3h.4M58.3 96.5a.56 .56 0 0 0-.7 .5 .56 .56 0 0 0 .7 .6M58.9 83.7h-.6v1.3M59.3 84.2h.5l.1 .8"/>
<path d="M59.6 96.4v1.3l-.7-1.3v1.3M59.9 84.4l-.6 .3 .2 .3 .4-.1M60.1 96.4h.8l-.4 .5 .3 .1v.6l-.2 .1-.5-.1M60.5 84.3l.5-.1v.8M60.5 84.1v.9"/>
</g>
<path d="M54.2 86.5h.8l-.4 .5 .4 .1v.6l-.2 .1-.6-.1M54.3 92.9h.7M54.3 92l.4-.4v1.3M54.3 89.2l.5-.1 .2 .3-.8 .9h.8" fill="none" stroke="#a90000" stroke-width=".21"/>
<path d="M47.7 97.7v3.8" fill="none" stroke="#840000" stroke-width=".51"/>
<circle cx="47.7" cy="101.5" r=".25" fill="#840000"/>
<path d="M48.3 101.4l.5-.5 .5 1z" fill-rule="evenodd" fill="#840000"/>
<path d="M42 99.6h5.7M49.6 85.7v7.6M49.6 94.6v2.5M48.3 101.4h.1M48.8 100.9l.5 1-1-.5zM49.6 102.2v2.5" fill="none" stroke="#840000" stroke-width=".21"/>
<g fill="none" stroke="#840000" stroke-width=".25">
<path d="M48.3 88.2h2.6M49.6 88.2l1.3 2.6h-2.6z"/>
<circle cx="48.3" cy="99.6" r="2.82"/>
</g>
<path d="M49.9 96.3v-.8l.5 .4 .1-.4h.5l.2 .2-.2 .6M44.5 101.2h.7M44.5 100.3l.3-.4v1.3M51.2 103.1v.8l-.9-.8-.4 .2 .1 .5" fill="none" stroke="#a90000" stroke-width=".21"/>
<g fill="none" stroke="#006464" stroke-width=".21">
<path d="M39.8 91.3h.7M39.8 90.4l.4-.3v1.2M41.8 90.1v1.2l-.7-1.2v1.2M42.6 90l-.3 .9h.8M42.9 90.5v.8M43.7 90.2l.1-.1a.68 .68 0 0 1 .5 .6 .68 .68 0 0 1-.5 .6l-.3-.5zM44.9 90.2l.1-.1a.68 .68 0 0 1 .5 .6 .68 .68 0 0 1-.5 .6l-.3-.5zM44.9 87.5a.64 .64 0 0 1 .8 .7 .64 .64 0 0 1-.8 .6zM45.9 90.1h.8l-.5 1.2M46.4 88.1l-.3-.3 .3-.3h.2l.3 .3-.3 .3M46.4 88.1l-.3 .2 .1 .4 .2 .1 .3-.1 .2-.1v-.3l-.3-.2M46.4 88.1h.2"/>
<path d="M52.4 97.8h.2a.43 .43 0 0 1 .5 .4v.4a.42 .42 0 0 1-.4 .5 .42 .42 0 0 1-.4-.5zM52.5 98.7l.7 .5M53.8 98.3l-.2-.2 .2-.3h.3l.2 .2-.2 .3M53.8 98.3l-.2 .3v.3l.2 .2 .4-.1 .1-.2v-.2l-.2-.3M53.8 98.3h.3M53 100.2h-.7v.4l.6 .2 .1 .3-.3 .3-.4-.1M54.2 100.2h-.7v.4l.6 .2 .1 .3-.3 .3-.4-.1M54.9 100.6l-.2-.2 .2-.3h.3l.2 .2-.2 .3M54.9 100.6l-.2 .3v.3l.2 .2 .4-.1 .1-.2v-.2l-.2-.3M54.9 100.6h.3M56.1 100.2l.1-.1a.68 .68 0 0 1 .4 .6 .68 .68 0 0 1-.4 .7 .84 .84 0 0 1-.1-1.2zM57.8 100.1h-.7v.6l.6-.1 .1 .6-.2 .2-.5-.2"/>
<path d="M58.4 100.2l.2-.1a.68 .68 0 0 1 .4 .6 .68 .68 0 0 1-.4 .7l-.3-.5z"/>
</g>
<path d="M48.3 107.5h2.6v.5h-2.6z" fill-rule="evenodd" fill="#840000"/>
<path d="M48.3 107.5h2.6v.5h-2.6z" fill="none" stroke="#840000" stroke-width=".25"/>
<path d="M35.6 99.6h.8M36.4 98.9h3.5v1.5h-3.5zM39.9 99.6h.8M49.6 106v1.5" fill="none" stroke="#840000" stroke-width=".21"/>
<g fill="none" stroke="#006464" stroke-width=".21">
<path d="M36.6 97.1l.6-.1 .1-.5-.7-.1v1.3M36.9 97.1l.5 .6M37.8 96.4h.8l-.5 .5 .4 .1v.6l-.2 .1-.5-.1M39.3 97l-.3-.3 .3-.3h.2l.3 .3-.3 .3M39.3 97l-.3 .2 .1 .4 .2 .1 .3-.1 .2-.2v-.2l-.3-.2M39.3 97h.2M36.6 101.6l.4-.1 .3 .3-.8 1h.8M37.8 101.5v1.3M38 102l.6 .8M38.6 101.5l-.8 .7M39 101.6l.5-.1 .3 .3-.8 1h.8M48 109.2a.58 .58 0 0 0-.7 .5 .58 .58 0 0 0 .7 .6v-.5h-.2"/>
<path d="M49.3 109.1v1.3l-.7-1.3v1.3M49.9 109.1a.64 .64 0 0 1 .8 .6 .64 .64 0 0 1-.8 .7zM51.2 109.1a.64 .64 0 0 1 .7 .6 .64 .64 0 0 1-.7 .7z"/>
</g>
<g fill="#009600">
<circle cx="187.3" cy="77.4" r=".46"/>
<circle cx="198.1" cy="97.1" r=".46"/>
<circle cx="176.5" cy="77.4" r=".46"/>
<circle cx="183.5" cy="77.4" r=".46"/>
<circle cx="183.5" cy="81.9" r=".46"/>
<circle cx="187.3" cy="97.1" r=".46"/>
<circle cx="183.5" cy="97.1" r=".46"/>
<circle cx="167.6" cy="97.1" r=".46"/>
<circle cx="176.5" cy="97.1" r=".46"/>
<circle cx="203.2" cy="85" r=".46"/>
<circle cx="136.5" cy="83.1" r=".46"/>
<circle cx="156.2" cy="77.4" r=".46"/>
<circle cx="144.2" cy="83.1" r=".46"/>
<circle cx="156.2" cy="97.1" r=".46"/>
<circle cx="151.8" cy="97.1" r=".46"/>
<circle cx="136.5" cy="97.1" r=".46"/>
<circle cx="156.2" cy="49.5" r=".46"/>
<circle cx="136.5" cy="57.1" r=".46"/>
<circle cx="172.7" cy="49.5" r=".46"/>
<circle cx="167.6" cy="49.5" r=".46"/>
<circle cx="167.6" cy="59.7" r=".46"/>
<circle cx="209.5" cy="97.1" r=".46"/>
<circle cx="219.7" cy="89.5" r=".46"/>
<circle cx="219.7" cy="80" r=".46"/>
<circle cx="237.4" cy="71.1" r=".46"/>
<circle cx="224.8" cy="97.1" r=".46"/>
<circle cx="80.1" cy="50.8" r=".46"/>
<circle cx="80.1" cy="53.3" r=".46"/>
<circle cx="59.7" cy="29.2" r=".46"/>
<circle cx="67.4" cy="64.7" r=".46"/>
<circle cx="53.4" cy="29.2" r=".46"/>
<circle cx="211.4" cy="59.7" r=".46"/>
<circle cx="201.9" cy="59.7" r=".46"/>
<circle cx="186.7" cy="59.7" r=".46"/>
<circle cx="201.9" cy="49.5" r=".46"/>
<circle cx="211.4" cy="49.5" r=".46"/>
<circle cx="224.8" cy="49.5" r=".46"/>
<circle cx="217.8" cy="49.5" r=".46"/>
<circle cx="224.8" cy="61.6" r=".46"/>
<circle cx="227.3" cy="49.5" r=".46"/>
<circle cx="219.7" cy="61.6" r=".46"/>
<circle cx="237.4" cy="61.6" r=".46"/>
<circle cx="49.6" cy="85.7" r=".46"/>
<circle cx="49.6" cy="93.3" r=".46"/>
</g>
</svg>
